VERSION 5.8 ;
BUSBITCHARS "[]" ;
DIVIDERCHAR "/" ;
UNITS
    DATABASE MICRONS 1000 ;
END UNITS

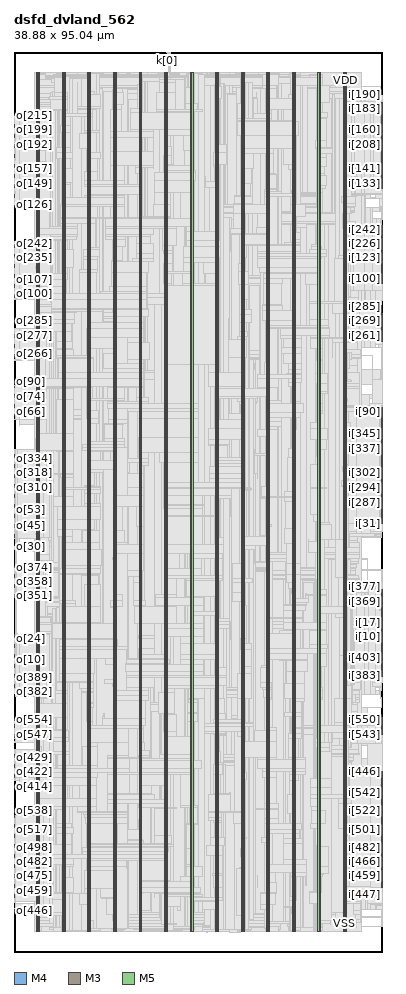
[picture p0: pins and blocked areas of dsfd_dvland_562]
MACRO dsfd_dvland_562
  FOREIGN dsfd_dvland_562 0 0 ;
  CLASS BLOCK ;
  SIZE 38.88 BY 95.04 ;
  PIN ck
    DIRECTION INPUT ;
    USE SIGNAL ;
    PORT
      LAYER M4 ;
        RECT  0 30.576 0.084 30.6 ;
    END
  END ck
  PIN ck_f
    DIRECTION INPUT ;
    USE SIGNAL ;
    PORT
      LAYER M4 ;
        RECT  38.796 32.208 38.88 32.232 ;
    END
  END ck_f
  PIN fault
    DIRECTION OUTPUT ;
    USE SIGNAL ;
    PORT
      LAYER M4 ;
        RECT  0 30.672 0.084 30.696 ;
    END
  END fault
  PIN i[0]
    DIRECTION INPUT ;
    USE SIGNAL ;
    PORT
      LAYER M4 ;
        RECT  38.796 32.304 38.88 32.328 ;
    END
  END i[0]
  PIN i[100]
    DIRECTION INPUT ;
    USE SIGNAL ;
    PORT
      LAYER M4 ;
        RECT  38.796 71.088 38.88 71.112 ;
    END
  END i[100]
  PIN i[101]
    DIRECTION INPUT ;
    USE SIGNAL ;
    PORT
      LAYER M4 ;
        RECT  38.796 71.184 38.88 71.208 ;
    END
  END i[101]
  PIN i[102]
    DIRECTION INPUT ;
    USE SIGNAL ;
    PORT
      LAYER M4 ;
        RECT  38.796 71.28 38.88 71.304 ;
    END
  END i[102]
  PIN i[103]
    DIRECTION INPUT ;
    USE SIGNAL ;
    PORT
      LAYER M4 ;
        RECT  38.796 71.376 38.88 71.4 ;
    END
  END i[103]
  PIN i[104]
    DIRECTION INPUT ;
    USE SIGNAL ;
    PORT
      LAYER M4 ;
        RECT  38.796 71.472 38.88 71.496 ;
    END
  END i[104]
  PIN i[105]
    DIRECTION INPUT ;
    USE SIGNAL ;
    PORT
      LAYER M4 ;
        RECT  38.796 71.568 38.88 71.592 ;
    END
  END i[105]
  PIN i[106]
    DIRECTION INPUT ;
    USE SIGNAL ;
    PORT
      LAYER M4 ;
        RECT  38.796 71.664 38.88 71.688 ;
    END
  END i[106]
  PIN i[107]
    DIRECTION INPUT ;
    USE SIGNAL ;
    PORT
      LAYER M4 ;
        RECT  38.796 71.76 38.88 71.784 ;
    END
  END i[107]
  PIN i[108]
    DIRECTION INPUT ;
    USE SIGNAL ;
    PORT
      LAYER M4 ;
        RECT  38.796 71.856 38.88 71.88 ;
    END
  END i[108]
  PIN i[109]
    DIRECTION INPUT ;
    USE SIGNAL ;
    PORT
      LAYER M4 ;
        RECT  38.796 71.952 38.88 71.976 ;
    END
  END i[109]
  PIN i[10]
    DIRECTION INPUT ;
    USE SIGNAL ;
    PORT
      LAYER M4 ;
        RECT  38.796 33.264 38.88 33.288 ;
    END
  END i[10]
  PIN i[110]
    DIRECTION INPUT ;
    USE SIGNAL ;
    PORT
      LAYER M4 ;
        RECT  38.796 72.048 38.88 72.072 ;
    END
  END i[110]
  PIN i[111]
    DIRECTION INPUT ;
    USE SIGNAL ;
    PORT
      LAYER M4 ;
        RECT  38.796 72.144 38.88 72.168 ;
    END
  END i[111]
  PIN i[112]
    DIRECTION INPUT ;
    USE SIGNAL ;
    PORT
      LAYER M4 ;
        RECT  38.796 72.24 38.88 72.264 ;
    END
  END i[112]
  PIN i[113]
    DIRECTION INPUT ;
    USE SIGNAL ;
    PORT
      LAYER M4 ;
        RECT  38.796 72.336 38.88 72.36 ;
    END
  END i[113]
  PIN i[114]
    DIRECTION INPUT ;
    USE SIGNAL ;
    PORT
      LAYER M4 ;
        RECT  38.796 72.432 38.88 72.456 ;
    END
  END i[114]
  PIN i[115]
    DIRECTION INPUT ;
    USE SIGNAL ;
    PORT
      LAYER M4 ;
        RECT  38.796 72.528 38.88 72.552 ;
    END
  END i[115]
  PIN i[116]
    DIRECTION INPUT ;
    USE SIGNAL ;
    PORT
      LAYER M4 ;
        RECT  38.796 72.624 38.88 72.648 ;
    END
  END i[116]
  PIN i[117]
    DIRECTION INPUT ;
    USE SIGNAL ;
    PORT
      LAYER M4 ;
        RECT  38.796 72.72 38.88 72.744 ;
    END
  END i[117]
  PIN i[118]
    DIRECTION INPUT ;
    USE SIGNAL ;
    PORT
      LAYER M4 ;
        RECT  38.796 72.816 38.88 72.84 ;
    END
  END i[118]
  PIN i[119]
    DIRECTION INPUT ;
    USE SIGNAL ;
    PORT
      LAYER M4 ;
        RECT  38.796 72.912 38.88 72.936 ;
    END
  END i[119]
  PIN i[11]
    DIRECTION INPUT ;
    USE SIGNAL ;
    PORT
      LAYER M4 ;
        RECT  38.796 33.36 38.88 33.384 ;
    END
  END i[11]
  PIN i[120]
    DIRECTION INPUT ;
    USE SIGNAL ;
    PORT
      LAYER M4 ;
        RECT  38.796 73.008 38.88 73.032 ;
    END
  END i[120]
  PIN i[121]
    DIRECTION INPUT ;
    USE SIGNAL ;
    PORT
      LAYER M4 ;
        RECT  38.796 73.104 38.88 73.128 ;
    END
  END i[121]
  PIN i[122]
    DIRECTION INPUT ;
    USE SIGNAL ;
    PORT
      LAYER M4 ;
        RECT  38.796 73.2 38.88 73.224 ;
    END
  END i[122]
  PIN i[123]
    DIRECTION INPUT ;
    USE SIGNAL ;
    PORT
      LAYER M4 ;
        RECT  38.796 73.296 38.88 73.32 ;
    END
  END i[123]
  PIN i[124]
    DIRECTION INPUT ;
    USE SIGNAL ;
    PORT
      LAYER M4 ;
        RECT  38.796 73.392 38.88 73.416 ;
    END
  END i[124]
  PIN i[125]
    DIRECTION INPUT ;
    USE SIGNAL ;
    PORT
      LAYER M4 ;
        RECT  38.796 73.488 38.88 73.512 ;
    END
  END i[125]
  PIN i[126]
    DIRECTION INPUT ;
    USE SIGNAL ;
    PORT
      LAYER M4 ;
        RECT  38.796 73.584 38.88 73.608 ;
    END
  END i[126]
  PIN i[127]
    DIRECTION INPUT ;
    USE SIGNAL ;
    PORT
      LAYER M4 ;
        RECT  38.796 80.592 38.88 80.616 ;
    END
  END i[127]
  PIN i[128]
    DIRECTION INPUT ;
    USE SIGNAL ;
    PORT
      LAYER M4 ;
        RECT  38.796 80.688 38.88 80.712 ;
    END
  END i[128]
  PIN i[129]
    DIRECTION INPUT ;
    USE SIGNAL ;
    PORT
      LAYER M4 ;
        RECT  38.796 80.784 38.88 80.808 ;
    END
  END i[129]
  PIN i[12]
    DIRECTION INPUT ;
    USE SIGNAL ;
    PORT
      LAYER M4 ;
        RECT  38.796 33.456 38.88 33.48 ;
    END
  END i[12]
  PIN i[130]
    DIRECTION INPUT ;
    USE SIGNAL ;
    PORT
      LAYER M4 ;
        RECT  38.796 80.88 38.88 80.904 ;
    END
  END i[130]
  PIN i[131]
    DIRECTION INPUT ;
    USE SIGNAL ;
    PORT
      LAYER M4 ;
        RECT  38.796 80.976 38.88 81 ;
    END
  END i[131]
  PIN i[132]
    DIRECTION INPUT ;
    USE SIGNAL ;
    PORT
      LAYER M4 ;
        RECT  38.796 81.072 38.88 81.096 ;
    END
  END i[132]
  PIN i[133]
    DIRECTION INPUT ;
    USE SIGNAL ;
    PORT
      LAYER M4 ;
        RECT  38.796 81.168 38.88 81.192 ;
    END
  END i[133]
  PIN i[134]
    DIRECTION INPUT ;
    USE SIGNAL ;
    PORT
      LAYER M4 ;
        RECT  38.796 81.264 38.88 81.288 ;
    END
  END i[134]
  PIN i[135]
    DIRECTION INPUT ;
    USE SIGNAL ;
    PORT
      LAYER M4 ;
        RECT  38.796 81.36 38.88 81.384 ;
    END
  END i[135]
  PIN i[136]
    DIRECTION INPUT ;
    USE SIGNAL ;
    PORT
      LAYER M4 ;
        RECT  38.796 81.456 38.88 81.48 ;
    END
  END i[136]
  PIN i[137]
    DIRECTION INPUT ;
    USE SIGNAL ;
    PORT
      LAYER M4 ;
        RECT  38.796 81.552 38.88 81.576 ;
    END
  END i[137]
  PIN i[138]
    DIRECTION INPUT ;
    USE SIGNAL ;
    PORT
      LAYER M4 ;
        RECT  38.796 81.648 38.88 81.672 ;
    END
  END i[138]
  PIN i[139]
    DIRECTION INPUT ;
    USE SIGNAL ;
    PORT
      LAYER M4 ;
        RECT  38.796 81.744 38.88 81.768 ;
    END
  END i[139]
  PIN i[13]
    DIRECTION INPUT ;
    USE SIGNAL ;
    PORT
      LAYER M4 ;
        RECT  38.796 33.552 38.88 33.576 ;
    END
  END i[13]
  PIN i[140]
    DIRECTION INPUT ;
    USE SIGNAL ;
    PORT
      LAYER M4 ;
        RECT  38.796 81.84 38.88 81.864 ;
    END
  END i[140]
  PIN i[141]
    DIRECTION INPUT ;
    USE SIGNAL ;
    PORT
      LAYER M4 ;
        RECT  38.796 81.936 38.88 81.96 ;
    END
  END i[141]
  PIN i[142]
    DIRECTION INPUT ;
    USE SIGNAL ;
    PORT
      LAYER M4 ;
        RECT  38.796 82.032 38.88 82.056 ;
    END
  END i[142]
  PIN i[143]
    DIRECTION INPUT ;
    USE SIGNAL ;
    PORT
      LAYER M4 ;
        RECT  38.796 82.128 38.88 82.152 ;
    END
  END i[143]
  PIN i[144]
    DIRECTION INPUT ;
    USE SIGNAL ;
    PORT
      LAYER M4 ;
        RECT  38.796 82.224 38.88 82.248 ;
    END
  END i[144]
  PIN i[145]
    DIRECTION INPUT ;
    USE SIGNAL ;
    PORT
      LAYER M4 ;
        RECT  38.796 82.32 38.88 82.344 ;
    END
  END i[145]
  PIN i[146]
    DIRECTION INPUT ;
    USE SIGNAL ;
    PORT
      LAYER M4 ;
        RECT  38.796 82.416 38.88 82.44 ;
    END
  END i[146]
  PIN i[147]
    DIRECTION INPUT ;
    USE SIGNAL ;
    PORT
      LAYER M4 ;
        RECT  38.796 82.512 38.88 82.536 ;
    END
  END i[147]
  PIN i[148]
    DIRECTION INPUT ;
    USE SIGNAL ;
    PORT
      LAYER M4 ;
        RECT  38.796 82.608 38.88 82.632 ;
    END
  END i[148]
  PIN i[149]
    DIRECTION INPUT ;
    USE SIGNAL ;
    PORT
      LAYER M4 ;
        RECT  38.796 82.704 38.88 82.728 ;
    END
  END i[149]
  PIN i[14]
    DIRECTION INPUT ;
    USE SIGNAL ;
    PORT
      LAYER M4 ;
        RECT  38.796 33.648 38.88 33.672 ;
    END
  END i[14]
  PIN i[150]
    DIRECTION INPUT ;
    USE SIGNAL ;
    PORT
      LAYER M4 ;
        RECT  38.796 82.8 38.88 82.824 ;
    END
  END i[150]
  PIN i[151]
    DIRECTION INPUT ;
    USE SIGNAL ;
    PORT
      LAYER M4 ;
        RECT  38.796 82.896 38.88 82.92 ;
    END
  END i[151]
  PIN i[152]
    DIRECTION INPUT ;
    USE SIGNAL ;
    PORT
      LAYER M4 ;
        RECT  38.796 82.992 38.88 83.016 ;
    END
  END i[152]
  PIN i[153]
    DIRECTION INPUT ;
    USE SIGNAL ;
    PORT
      LAYER M4 ;
        RECT  38.796 83.088 38.88 83.112 ;
    END
  END i[153]
  PIN i[154]
    DIRECTION INPUT ;
    USE SIGNAL ;
    PORT
      LAYER M4 ;
        RECT  38.796 83.184 38.88 83.208 ;
    END
  END i[154]
  PIN i[155]
    DIRECTION INPUT ;
    USE SIGNAL ;
    PORT
      LAYER M4 ;
        RECT  38.796 83.28 38.88 83.304 ;
    END
  END i[155]
  PIN i[156]
    DIRECTION INPUT ;
    USE SIGNAL ;
    PORT
      LAYER M4 ;
        RECT  38.796 83.376 38.88 83.4 ;
    END
  END i[156]
  PIN i[157]
    DIRECTION INPUT ;
    USE SIGNAL ;
    PORT
      LAYER M4 ;
        RECT  38.796 83.472 38.88 83.496 ;
    END
  END i[157]
  PIN i[158]
    DIRECTION INPUT ;
    USE SIGNAL ;
    PORT
      LAYER M4 ;
        RECT  38.796 83.568 38.88 83.592 ;
    END
  END i[158]
  PIN i[159]
    DIRECTION INPUT ;
    USE SIGNAL ;
    PORT
      LAYER M4 ;
        RECT  38.796 86.736 38.88 86.76 ;
    END
  END i[159]
  PIN i[15]
    DIRECTION INPUT ;
    USE SIGNAL ;
    PORT
      LAYER M4 ;
        RECT  38.796 33.744 38.88 33.768 ;
    END
  END i[15]
  PIN i[160]
    DIRECTION INPUT ;
    USE SIGNAL ;
    PORT
      LAYER M4 ;
        RECT  38.796 86.832 38.88 86.856 ;
    END
  END i[160]
  PIN i[161]
    DIRECTION INPUT ;
    USE SIGNAL ;
    PORT
      LAYER M4 ;
        RECT  38.796 86.928 38.88 86.952 ;
    END
  END i[161]
  PIN i[162]
    DIRECTION INPUT ;
    USE SIGNAL ;
    PORT
      LAYER M4 ;
        RECT  38.796 87.024 38.88 87.048 ;
    END
  END i[162]
  PIN i[163]
    DIRECTION INPUT ;
    USE SIGNAL ;
    PORT
      LAYER M4 ;
        RECT  38.796 87.12 38.88 87.144 ;
    END
  END i[163]
  PIN i[164]
    DIRECTION INPUT ;
    USE SIGNAL ;
    PORT
      LAYER M4 ;
        RECT  38.796 87.216 38.88 87.24 ;
    END
  END i[164]
  PIN i[165]
    DIRECTION INPUT ;
    USE SIGNAL ;
    PORT
      LAYER M4 ;
        RECT  38.796 87.312 38.88 87.336 ;
    END
  END i[165]
  PIN i[166]
    DIRECTION INPUT ;
    USE SIGNAL ;
    PORT
      LAYER M4 ;
        RECT  38.796 87.408 38.88 87.432 ;
    END
  END i[166]
  PIN i[167]
    DIRECTION INPUT ;
    USE SIGNAL ;
    PORT
      LAYER M4 ;
        RECT  38.796 87.504 38.88 87.528 ;
    END
  END i[167]
  PIN i[168]
    DIRECTION INPUT ;
    USE SIGNAL ;
    PORT
      LAYER M4 ;
        RECT  38.796 87.6 38.88 87.624 ;
    END
  END i[168]
  PIN i[169]
    DIRECTION INPUT ;
    USE SIGNAL ;
    PORT
      LAYER M4 ;
        RECT  38.796 87.696 38.88 87.72 ;
    END
  END i[169]
  PIN i[16]
    DIRECTION INPUT ;
    USE SIGNAL ;
    PORT
      LAYER M4 ;
        RECT  38.796 33.84 38.88 33.864 ;
    END
  END i[16]
  PIN i[170]
    DIRECTION INPUT ;
    USE SIGNAL ;
    PORT
      LAYER M4 ;
        RECT  38.796 87.792 38.88 87.816 ;
    END
  END i[170]
  PIN i[171]
    DIRECTION INPUT ;
    USE SIGNAL ;
    PORT
      LAYER M4 ;
        RECT  38.796 87.888 38.88 87.912 ;
    END
  END i[171]
  PIN i[172]
    DIRECTION INPUT ;
    USE SIGNAL ;
    PORT
      LAYER M4 ;
        RECT  38.796 87.984 38.88 88.008 ;
    END
  END i[172]
  PIN i[173]
    DIRECTION INPUT ;
    USE SIGNAL ;
    PORT
      LAYER M4 ;
        RECT  38.796 88.08 38.88 88.104 ;
    END
  END i[173]
  PIN i[174]
    DIRECTION INPUT ;
    USE SIGNAL ;
    PORT
      LAYER M4 ;
        RECT  38.796 88.176 38.88 88.2 ;
    END
  END i[174]
  PIN i[175]
    DIRECTION INPUT ;
    USE SIGNAL ;
    PORT
      LAYER M4 ;
        RECT  38.796 88.272 38.88 88.296 ;
    END
  END i[175]
  PIN i[176]
    DIRECTION INPUT ;
    USE SIGNAL ;
    PORT
      LAYER M4 ;
        RECT  38.796 88.368 38.88 88.392 ;
    END
  END i[176]
  PIN i[177]
    DIRECTION INPUT ;
    USE SIGNAL ;
    PORT
      LAYER M4 ;
        RECT  38.796 88.464 38.88 88.488 ;
    END
  END i[177]
  PIN i[178]
    DIRECTION INPUT ;
    USE SIGNAL ;
    PORT
      LAYER M4 ;
        RECT  38.796 88.56 38.88 88.584 ;
    END
  END i[178]
  PIN i[179]
    DIRECTION INPUT ;
    USE SIGNAL ;
    PORT
      LAYER M4 ;
        RECT  38.796 88.656 38.88 88.68 ;
    END
  END i[179]
  PIN i[17]
    DIRECTION INPUT ;
    USE SIGNAL ;
    PORT
      LAYER M4 ;
        RECT  38.796 33.936 38.88 33.96 ;
    END
  END i[17]
  PIN i[180]
    DIRECTION INPUT ;
    USE SIGNAL ;
    PORT
      LAYER M4 ;
        RECT  38.796 88.752 38.88 88.776 ;
    END
  END i[180]
  PIN i[181]
    DIRECTION INPUT ;
    USE SIGNAL ;
    PORT
      LAYER M4 ;
        RECT  38.796 88.848 38.88 88.872 ;
    END
  END i[181]
  PIN i[182]
    DIRECTION INPUT ;
    USE SIGNAL ;
    PORT
      LAYER M4 ;
        RECT  38.796 88.944 38.88 88.968 ;
    END
  END i[182]
  PIN i[183]
    DIRECTION INPUT ;
    USE SIGNAL ;
    PORT
      LAYER M4 ;
        RECT  38.796 89.04 38.88 89.064 ;
    END
  END i[183]
  PIN i[184]
    DIRECTION INPUT ;
    USE SIGNAL ;
    PORT
      LAYER M4 ;
        RECT  38.796 89.136 38.88 89.16 ;
    END
  END i[184]
  PIN i[185]
    DIRECTION INPUT ;
    USE SIGNAL ;
    PORT
      LAYER M4 ;
        RECT  38.796 89.232 38.88 89.256 ;
    END
  END i[185]
  PIN i[186]
    DIRECTION INPUT ;
    USE SIGNAL ;
    PORT
      LAYER M4 ;
        RECT  38.796 89.328 38.88 89.352 ;
    END
  END i[186]
  PIN i[187]
    DIRECTION INPUT ;
    USE SIGNAL ;
    PORT
      LAYER M4 ;
        RECT  38.796 89.424 38.88 89.448 ;
    END
  END i[187]
  PIN i[188]
    DIRECTION INPUT ;
    USE SIGNAL ;
    PORT
      LAYER M4 ;
        RECT  38.796 89.52 38.88 89.544 ;
    END
  END i[188]
  PIN i[189]
    DIRECTION INPUT ;
    USE SIGNAL ;
    PORT
      LAYER M4 ;
        RECT  38.796 89.616 38.88 89.64 ;
    END
  END i[189]
  PIN i[18]
    DIRECTION INPUT ;
    USE SIGNAL ;
    PORT
      LAYER M4 ;
        RECT  38.796 34.032 38.88 34.056 ;
    END
  END i[18]
  PIN i[190]
    DIRECTION INPUT ;
    USE SIGNAL ;
    PORT
      LAYER M4 ;
        RECT  38.796 89.712 38.88 89.736 ;
    END
  END i[190]
  PIN i[191]
    DIRECTION INPUT ;
    USE SIGNAL ;
    PORT
      LAYER M4 ;
        RECT  38.796 83.664 38.88 83.688 ;
    END
  END i[191]
  PIN i[192]
    DIRECTION INPUT ;
    USE SIGNAL ;
    PORT
      LAYER M4 ;
        RECT  38.796 83.76 38.88 83.784 ;
    END
  END i[192]
  PIN i[193]
    DIRECTION INPUT ;
    USE SIGNAL ;
    PORT
      LAYER M4 ;
        RECT  38.796 83.856 38.88 83.88 ;
    END
  END i[193]
  PIN i[194]
    DIRECTION INPUT ;
    USE SIGNAL ;
    PORT
      LAYER M4 ;
        RECT  38.796 83.952 38.88 83.976 ;
    END
  END i[194]
  PIN i[195]
    DIRECTION INPUT ;
    USE SIGNAL ;
    PORT
      LAYER M4 ;
        RECT  38.796 84.048 38.88 84.072 ;
    END
  END i[195]
  PIN i[196]
    DIRECTION INPUT ;
    USE SIGNAL ;
    PORT
      LAYER M4 ;
        RECT  38.796 84.144 38.88 84.168 ;
    END
  END i[196]
  PIN i[197]
    DIRECTION INPUT ;
    USE SIGNAL ;
    PORT
      LAYER M4 ;
        RECT  38.796 84.24 38.88 84.264 ;
    END
  END i[197]
  PIN i[198]
    DIRECTION INPUT ;
    USE SIGNAL ;
    PORT
      LAYER M4 ;
        RECT  38.796 84.336 38.88 84.36 ;
    END
  END i[198]
  PIN i[199]
    DIRECTION INPUT ;
    USE SIGNAL ;
    PORT
      LAYER M4 ;
        RECT  38.796 84.432 38.88 84.456 ;
    END
  END i[199]
  PIN i[19]
    DIRECTION INPUT ;
    USE SIGNAL ;
    PORT
      LAYER M4 ;
        RECT  38.796 34.128 38.88 34.152 ;
    END
  END i[19]
  PIN i[1]
    DIRECTION INPUT ;
    USE SIGNAL ;
    PORT
      LAYER M4 ;
        RECT  38.796 32.4 38.88 32.424 ;
    END
  END i[1]
  PIN i[200]
    DIRECTION INPUT ;
    USE SIGNAL ;
    PORT
      LAYER M4 ;
        RECT  38.796 84.528 38.88 84.552 ;
    END
  END i[200]
  PIN i[201]
    DIRECTION INPUT ;
    USE SIGNAL ;
    PORT
      LAYER M4 ;
        RECT  38.796 84.624 38.88 84.648 ;
    END
  END i[201]
  PIN i[202]
    DIRECTION INPUT ;
    USE SIGNAL ;
    PORT
      LAYER M4 ;
        RECT  38.796 84.72 38.88 84.744 ;
    END
  END i[202]
  PIN i[203]
    DIRECTION INPUT ;
    USE SIGNAL ;
    PORT
      LAYER M4 ;
        RECT  38.796 84.816 38.88 84.84 ;
    END
  END i[203]
  PIN i[204]
    DIRECTION INPUT ;
    USE SIGNAL ;
    PORT
      LAYER M4 ;
        RECT  38.796 84.912 38.88 84.936 ;
    END
  END i[204]
  PIN i[205]
    DIRECTION INPUT ;
    USE SIGNAL ;
    PORT
      LAYER M4 ;
        RECT  38.796 85.008 38.88 85.032 ;
    END
  END i[205]
  PIN i[206]
    DIRECTION INPUT ;
    USE SIGNAL ;
    PORT
      LAYER M4 ;
        RECT  38.796 85.104 38.88 85.128 ;
    END
  END i[206]
  PIN i[207]
    DIRECTION INPUT ;
    USE SIGNAL ;
    PORT
      LAYER M4 ;
        RECT  38.796 85.2 38.88 85.224 ;
    END
  END i[207]
  PIN i[208]
    DIRECTION INPUT ;
    USE SIGNAL ;
    PORT
      LAYER M4 ;
        RECT  38.796 85.296 38.88 85.32 ;
    END
  END i[208]
  PIN i[209]
    DIRECTION INPUT ;
    USE SIGNAL ;
    PORT
      LAYER M4 ;
        RECT  38.796 85.392 38.88 85.416 ;
    END
  END i[209]
  PIN i[20]
    DIRECTION INPUT ;
    USE SIGNAL ;
    PORT
      LAYER M4 ;
        RECT  38.796 34.224 38.88 34.248 ;
    END
  END i[20]
  PIN i[210]
    DIRECTION INPUT ;
    USE SIGNAL ;
    PORT
      LAYER M4 ;
        RECT  38.796 85.488 38.88 85.512 ;
    END
  END i[210]
  PIN i[211]
    DIRECTION INPUT ;
    USE SIGNAL ;
    PORT
      LAYER M4 ;
        RECT  38.796 85.584 38.88 85.608 ;
    END
  END i[211]
  PIN i[212]
    DIRECTION INPUT ;
    USE SIGNAL ;
    PORT
      LAYER M4 ;
        RECT  38.796 85.68 38.88 85.704 ;
    END
  END i[212]
  PIN i[213]
    DIRECTION INPUT ;
    USE SIGNAL ;
    PORT
      LAYER M4 ;
        RECT  38.796 85.776 38.88 85.8 ;
    END
  END i[213]
  PIN i[214]
    DIRECTION INPUT ;
    USE SIGNAL ;
    PORT
      LAYER M4 ;
        RECT  38.796 85.872 38.88 85.896 ;
    END
  END i[214]
  PIN i[215]
    DIRECTION INPUT ;
    USE SIGNAL ;
    PORT
      LAYER M4 ;
        RECT  38.796 85.968 38.88 85.992 ;
    END
  END i[215]
  PIN i[216]
    DIRECTION INPUT ;
    USE SIGNAL ;
    PORT
      LAYER M4 ;
        RECT  38.796 86.064 38.88 86.088 ;
    END
  END i[216]
  PIN i[217]
    DIRECTION INPUT ;
    USE SIGNAL ;
    PORT
      LAYER M4 ;
        RECT  38.796 86.16 38.88 86.184 ;
    END
  END i[217]
  PIN i[218]
    DIRECTION INPUT ;
    USE SIGNAL ;
    PORT
      LAYER M4 ;
        RECT  38.796 86.256 38.88 86.28 ;
    END
  END i[218]
  PIN i[219]
    DIRECTION INPUT ;
    USE SIGNAL ;
    PORT
      LAYER M4 ;
        RECT  38.796 86.352 38.88 86.376 ;
    END
  END i[219]
  PIN i[21]
    DIRECTION INPUT ;
    USE SIGNAL ;
    PORT
      LAYER M4 ;
        RECT  38.796 34.32 38.88 34.344 ;
    END
  END i[21]
  PIN i[220]
    DIRECTION INPUT ;
    USE SIGNAL ;
    PORT
      LAYER M4 ;
        RECT  38.796 86.448 38.88 86.472 ;
    END
  END i[220]
  PIN i[221]
    DIRECTION INPUT ;
    USE SIGNAL ;
    PORT
      LAYER M4 ;
        RECT  38.796 86.544 38.88 86.568 ;
    END
  END i[221]
  PIN i[222]
    DIRECTION INPUT ;
    USE SIGNAL ;
    PORT
      LAYER M4 ;
        RECT  38.796 86.64 38.88 86.664 ;
    END
  END i[222]
  PIN i[223]
    DIRECTION INPUT ;
    USE SIGNAL ;
    PORT
      LAYER M4 ;
        RECT  38.796 73.68 38.88 73.704 ;
    END
  END i[223]
  PIN i[224]
    DIRECTION INPUT ;
    USE SIGNAL ;
    PORT
      LAYER M4 ;
        RECT  38.796 73.776 38.88 73.8 ;
    END
  END i[224]
  PIN i[225]
    DIRECTION INPUT ;
    USE SIGNAL ;
    PORT
      LAYER M4 ;
        RECT  38.796 73.872 38.88 73.896 ;
    END
  END i[225]
  PIN i[226]
    DIRECTION INPUT ;
    USE SIGNAL ;
    PORT
      LAYER M4 ;
        RECT  38.796 73.968 38.88 73.992 ;
    END
  END i[226]
  PIN i[227]
    DIRECTION INPUT ;
    USE SIGNAL ;
    PORT
      LAYER M4 ;
        RECT  38.796 74.064 38.88 74.088 ;
    END
  END i[227]
  PIN i[228]
    DIRECTION INPUT ;
    USE SIGNAL ;
    PORT
      LAYER M4 ;
        RECT  38.796 74.16 38.88 74.184 ;
    END
  END i[228]
  PIN i[229]
    DIRECTION INPUT ;
    USE SIGNAL ;
    PORT
      LAYER M4 ;
        RECT  38.796 74.256 38.88 74.28 ;
    END
  END i[229]
  PIN i[22]
    DIRECTION INPUT ;
    USE SIGNAL ;
    PORT
      LAYER M4 ;
        RECT  38.796 34.416 38.88 34.44 ;
    END
  END i[22]
  PIN i[230]
    DIRECTION INPUT ;
    USE SIGNAL ;
    PORT
      LAYER M4 ;
        RECT  38.796 74.352 38.88 74.376 ;
    END
  END i[230]
  PIN i[231]
    DIRECTION INPUT ;
    USE SIGNAL ;
    PORT
      LAYER M4 ;
        RECT  38.796 74.448 38.88 74.472 ;
    END
  END i[231]
  PIN i[232]
    DIRECTION INPUT ;
    USE SIGNAL ;
    PORT
      LAYER M4 ;
        RECT  38.796 74.544 38.88 74.568 ;
    END
  END i[232]
  PIN i[233]
    DIRECTION INPUT ;
    USE SIGNAL ;
    PORT
      LAYER M4 ;
        RECT  38.796 74.64 38.88 74.664 ;
    END
  END i[233]
  PIN i[234]
    DIRECTION INPUT ;
    USE SIGNAL ;
    PORT
      LAYER M4 ;
        RECT  38.796 74.736 38.88 74.76 ;
    END
  END i[234]
  PIN i[235]
    DIRECTION INPUT ;
    USE SIGNAL ;
    PORT
      LAYER M4 ;
        RECT  38.796 74.832 38.88 74.856 ;
    END
  END i[235]
  PIN i[236]
    DIRECTION INPUT ;
    USE SIGNAL ;
    PORT
      LAYER M4 ;
        RECT  38.796 74.928 38.88 74.952 ;
    END
  END i[236]
  PIN i[237]
    DIRECTION INPUT ;
    USE SIGNAL ;
    PORT
      LAYER M4 ;
        RECT  38.796 75.024 38.88 75.048 ;
    END
  END i[237]
  PIN i[238]
    DIRECTION INPUT ;
    USE SIGNAL ;
    PORT
      LAYER M4 ;
        RECT  38.796 75.12 38.88 75.144 ;
    END
  END i[238]
  PIN i[239]
    DIRECTION INPUT ;
    USE SIGNAL ;
    PORT
      LAYER M4 ;
        RECT  38.796 75.216 38.88 75.24 ;
    END
  END i[239]
  PIN i[23]
    DIRECTION INPUT ;
    USE SIGNAL ;
    PORT
      LAYER M4 ;
        RECT  38.796 34.512 38.88 34.536 ;
    END
  END i[23]
  PIN i[240]
    DIRECTION INPUT ;
    USE SIGNAL ;
    PORT
      LAYER M4 ;
        RECT  38.796 75.312 38.88 75.336 ;
    END
  END i[240]
  PIN i[241]
    DIRECTION INPUT ;
    USE SIGNAL ;
    PORT
      LAYER M4 ;
        RECT  38.796 75.408 38.88 75.432 ;
    END
  END i[241]
  PIN i[242]
    DIRECTION INPUT ;
    USE SIGNAL ;
    PORT
      LAYER M4 ;
        RECT  38.796 75.504 38.88 75.528 ;
    END
  END i[242]
  PIN i[243]
    DIRECTION INPUT ;
    USE SIGNAL ;
    PORT
      LAYER M4 ;
        RECT  38.796 75.6 38.88 75.624 ;
    END
  END i[243]
  PIN i[244]
    DIRECTION INPUT ;
    USE SIGNAL ;
    PORT
      LAYER M4 ;
        RECT  38.796 75.696 38.88 75.72 ;
    END
  END i[244]
  PIN i[245]
    DIRECTION INPUT ;
    USE SIGNAL ;
    PORT
      LAYER M4 ;
        RECT  38.796 75.792 38.88 75.816 ;
    END
  END i[245]
  PIN i[246]
    DIRECTION INPUT ;
    USE SIGNAL ;
    PORT
      LAYER M4 ;
        RECT  38.796 75.888 38.88 75.912 ;
    END
  END i[246]
  PIN i[247]
    DIRECTION INPUT ;
    USE SIGNAL ;
    PORT
      LAYER M4 ;
        RECT  38.796 75.984 38.88 76.008 ;
    END
  END i[247]
  PIN i[248]
    DIRECTION INPUT ;
    USE SIGNAL ;
    PORT
      LAYER M4 ;
        RECT  38.796 76.08 38.88 76.104 ;
    END
  END i[248]
  PIN i[249]
    DIRECTION INPUT ;
    USE SIGNAL ;
    PORT
      LAYER M4 ;
        RECT  38.796 76.176 38.88 76.2 ;
    END
  END i[249]
  PIN i[24]
    DIRECTION INPUT ;
    USE SIGNAL ;
    PORT
      LAYER M4 ;
        RECT  38.796 34.608 38.88 34.632 ;
    END
  END i[24]
  PIN i[250]
    DIRECTION INPUT ;
    USE SIGNAL ;
    PORT
      LAYER M4 ;
        RECT  38.796 76.272 38.88 76.296 ;
    END
  END i[250]
  PIN i[251]
    DIRECTION INPUT ;
    USE SIGNAL ;
    PORT
      LAYER M4 ;
        RECT  38.796 76.368 38.88 76.392 ;
    END
  END i[251]
  PIN i[252]
    DIRECTION INPUT ;
    USE SIGNAL ;
    PORT
      LAYER M4 ;
        RECT  38.796 76.464 38.88 76.488 ;
    END
  END i[252]
  PIN i[253]
    DIRECTION INPUT ;
    USE SIGNAL ;
    PORT
      LAYER M4 ;
        RECT  38.796 76.56 38.88 76.584 ;
    END
  END i[253]
  PIN i[254]
    DIRECTION INPUT ;
    USE SIGNAL ;
    PORT
      LAYER M4 ;
        RECT  38.796 76.656 38.88 76.68 ;
    END
  END i[254]
  PIN i[255]
    DIRECTION INPUT ;
    USE SIGNAL ;
    PORT
      LAYER M4 ;
        RECT  38.796 64.464 38.88 64.488 ;
    END
  END i[255]
  PIN i[256]
    DIRECTION INPUT ;
    USE SIGNAL ;
    PORT
      LAYER M4 ;
        RECT  38.796 64.56 38.88 64.584 ;
    END
  END i[256]
  PIN i[257]
    DIRECTION INPUT ;
    USE SIGNAL ;
    PORT
      LAYER M4 ;
        RECT  38.796 64.656 38.88 64.68 ;
    END
  END i[257]
  PIN i[258]
    DIRECTION INPUT ;
    USE SIGNAL ;
    PORT
      LAYER M4 ;
        RECT  38.796 64.752 38.88 64.776 ;
    END
  END i[258]
  PIN i[259]
    DIRECTION INPUT ;
    USE SIGNAL ;
    PORT
      LAYER M4 ;
        RECT  38.796 64.848 38.88 64.872 ;
    END
  END i[259]
  PIN i[25]
    DIRECTION INPUT ;
    USE SIGNAL ;
    PORT
      LAYER M4 ;
        RECT  38.796 34.704 38.88 34.728 ;
    END
  END i[25]
  PIN i[260]
    DIRECTION INPUT ;
    USE SIGNAL ;
    PORT
      LAYER M4 ;
        RECT  38.796 64.944 38.88 64.968 ;
    END
  END i[260]
  PIN i[261]
    DIRECTION INPUT ;
    USE SIGNAL ;
    PORT
      LAYER M4 ;
        RECT  38.796 65.04 38.88 65.064 ;
    END
  END i[261]
  PIN i[262]
    DIRECTION INPUT ;
    USE SIGNAL ;
    PORT
      LAYER M4 ;
        RECT  38.796 65.136 38.88 65.16 ;
    END
  END i[262]
  PIN i[263]
    DIRECTION INPUT ;
    USE SIGNAL ;
    PORT
      LAYER M4 ;
        RECT  38.796 65.232 38.88 65.256 ;
    END
  END i[263]
  PIN i[264]
    DIRECTION INPUT ;
    USE SIGNAL ;
    PORT
      LAYER M4 ;
        RECT  38.796 65.328 38.88 65.352 ;
    END
  END i[264]
  PIN i[265]
    DIRECTION INPUT ;
    USE SIGNAL ;
    PORT
      LAYER M4 ;
        RECT  38.796 65.424 38.88 65.448 ;
    END
  END i[265]
  PIN i[266]
    DIRECTION INPUT ;
    USE SIGNAL ;
    PORT
      LAYER M4 ;
        RECT  38.796 65.52 38.88 65.544 ;
    END
  END i[266]
  PIN i[267]
    DIRECTION INPUT ;
    USE SIGNAL ;
    PORT
      LAYER M4 ;
        RECT  38.796 65.616 38.88 65.64 ;
    END
  END i[267]
  PIN i[268]
    DIRECTION INPUT ;
    USE SIGNAL ;
    PORT
      LAYER M4 ;
        RECT  38.796 65.712 38.88 65.736 ;
    END
  END i[268]
  PIN i[269]
    DIRECTION INPUT ;
    USE SIGNAL ;
    PORT
      LAYER M4 ;
        RECT  38.796 65.808 38.88 65.832 ;
    END
  END i[269]
  PIN i[26]
    DIRECTION INPUT ;
    USE SIGNAL ;
    PORT
      LAYER M4 ;
        RECT  38.796 34.8 38.88 34.824 ;
    END
  END i[26]
  PIN i[270]
    DIRECTION INPUT ;
    USE SIGNAL ;
    PORT
      LAYER M4 ;
        RECT  38.796 65.904 38.88 65.928 ;
    END
  END i[270]
  PIN i[271]
    DIRECTION INPUT ;
    USE SIGNAL ;
    PORT
      LAYER M4 ;
        RECT  38.796 66 38.88 66.024 ;
    END
  END i[271]
  PIN i[272]
    DIRECTION INPUT ;
    USE SIGNAL ;
    PORT
      LAYER M4 ;
        RECT  38.796 66.096 38.88 66.12 ;
    END
  END i[272]
  PIN i[273]
    DIRECTION INPUT ;
    USE SIGNAL ;
    PORT
      LAYER M4 ;
        RECT  38.796 66.192 38.88 66.216 ;
    END
  END i[273]
  PIN i[274]
    DIRECTION INPUT ;
    USE SIGNAL ;
    PORT
      LAYER M4 ;
        RECT  38.796 66.288 38.88 66.312 ;
    END
  END i[274]
  PIN i[275]
    DIRECTION INPUT ;
    USE SIGNAL ;
    PORT
      LAYER M4 ;
        RECT  38.796 66.384 38.88 66.408 ;
    END
  END i[275]
  PIN i[276]
    DIRECTION INPUT ;
    USE SIGNAL ;
    PORT
      LAYER M4 ;
        RECT  38.796 66.48 38.88 66.504 ;
    END
  END i[276]
  PIN i[277]
    DIRECTION INPUT ;
    USE SIGNAL ;
    PORT
      LAYER M4 ;
        RECT  38.796 66.576 38.88 66.6 ;
    END
  END i[277]
  PIN i[278]
    DIRECTION INPUT ;
    USE SIGNAL ;
    PORT
      LAYER M4 ;
        RECT  38.796 66.672 38.88 66.696 ;
    END
  END i[278]
  PIN i[279]
    DIRECTION INPUT ;
    USE SIGNAL ;
    PORT
      LAYER M4 ;
        RECT  38.796 66.768 38.88 66.792 ;
    END
  END i[279]
  PIN i[27]
    DIRECTION INPUT ;
    USE SIGNAL ;
    PORT
      LAYER M4 ;
        RECT  38.796 34.896 38.88 34.92 ;
    END
  END i[27]
  PIN i[280]
    DIRECTION INPUT ;
    USE SIGNAL ;
    PORT
      LAYER M4 ;
        RECT  38.796 66.864 38.88 66.888 ;
    END
  END i[280]
  PIN i[281]
    DIRECTION INPUT ;
    USE SIGNAL ;
    PORT
      LAYER M4 ;
        RECT  38.796 66.96 38.88 66.984 ;
    END
  END i[281]
  PIN i[282]
    DIRECTION INPUT ;
    USE SIGNAL ;
    PORT
      LAYER M4 ;
        RECT  38.796 67.056 38.88 67.08 ;
    END
  END i[282]
  PIN i[283]
    DIRECTION INPUT ;
    USE SIGNAL ;
    PORT
      LAYER M4 ;
        RECT  38.796 67.152 38.88 67.176 ;
    END
  END i[283]
  PIN i[284]
    DIRECTION INPUT ;
    USE SIGNAL ;
    PORT
      LAYER M4 ;
        RECT  38.796 67.248 38.88 67.272 ;
    END
  END i[284]
  PIN i[285]
    DIRECTION INPUT ;
    USE SIGNAL ;
    PORT
      LAYER M4 ;
        RECT  38.796 67.344 38.88 67.368 ;
    END
  END i[285]
  PIN i[286]
    DIRECTION INPUT ;
    USE SIGNAL ;
    PORT
      LAYER M4 ;
        RECT  38.796 67.44 38.88 67.464 ;
    END
  END i[286]
  PIN i[287]
    DIRECTION INPUT ;
    USE SIGNAL ;
    PORT
      LAYER M4 ;
        RECT  38.796 48.336 38.88 48.36 ;
    END
  END i[287]
  PIN i[288]
    DIRECTION INPUT ;
    USE SIGNAL ;
    PORT
      LAYER M4 ;
        RECT  38.796 48.432 38.88 48.456 ;
    END
  END i[288]
  PIN i[289]
    DIRECTION INPUT ;
    USE SIGNAL ;
    PORT
      LAYER M4 ;
        RECT  38.796 48.528 38.88 48.552 ;
    END
  END i[289]
  PIN i[28]
    DIRECTION INPUT ;
    USE SIGNAL ;
    PORT
      LAYER M4 ;
        RECT  38.796 34.992 38.88 35.016 ;
    END
  END i[28]
  PIN i[290]
    DIRECTION INPUT ;
    USE SIGNAL ;
    PORT
      LAYER M4 ;
        RECT  38.796 48.624 38.88 48.648 ;
    END
  END i[290]
  PIN i[291]
    DIRECTION INPUT ;
    USE SIGNAL ;
    PORT
      LAYER M4 ;
        RECT  38.796 48.72 38.88 48.744 ;
    END
  END i[291]
  PIN i[292]
    DIRECTION INPUT ;
    USE SIGNAL ;
    PORT
      LAYER M4 ;
        RECT  38.796 48.816 38.88 48.84 ;
    END
  END i[292]
  PIN i[293]
    DIRECTION INPUT ;
    USE SIGNAL ;
    PORT
      LAYER M4 ;
        RECT  38.796 48.912 38.88 48.936 ;
    END
  END i[293]
  PIN i[294]
    DIRECTION INPUT ;
    USE SIGNAL ;
    PORT
      LAYER M4 ;
        RECT  38.796 49.008 38.88 49.032 ;
    END
  END i[294]
  PIN i[295]
    DIRECTION INPUT ;
    USE SIGNAL ;
    PORT
      LAYER M4 ;
        RECT  38.796 49.104 38.88 49.128 ;
    END
  END i[295]
  PIN i[296]
    DIRECTION INPUT ;
    USE SIGNAL ;
    PORT
      LAYER M4 ;
        RECT  38.796 49.2 38.88 49.224 ;
    END
  END i[296]
  PIN i[297]
    DIRECTION INPUT ;
    USE SIGNAL ;
    PORT
      LAYER M4 ;
        RECT  38.796 49.296 38.88 49.32 ;
    END
  END i[297]
  PIN i[298]
    DIRECTION INPUT ;
    USE SIGNAL ;
    PORT
      LAYER M4 ;
        RECT  38.796 49.392 38.88 49.416 ;
    END
  END i[298]
  PIN i[299]
    DIRECTION INPUT ;
    USE SIGNAL ;
    PORT
      LAYER M4 ;
        RECT  38.796 49.488 38.88 49.512 ;
    END
  END i[299]
  PIN i[29]
    DIRECTION INPUT ;
    USE SIGNAL ;
    PORT
      LAYER M4 ;
        RECT  38.796 35.088 38.88 35.112 ;
    END
  END i[29]
  PIN i[2]
    DIRECTION INPUT ;
    USE SIGNAL ;
    PORT
      LAYER M4 ;
        RECT  38.796 32.496 38.88 32.52 ;
    END
  END i[2]
  PIN i[300]
    DIRECTION INPUT ;
    USE SIGNAL ;
    PORT
      LAYER M4 ;
        RECT  38.796 49.584 38.88 49.608 ;
    END
  END i[300]
  PIN i[301]
    DIRECTION INPUT ;
    USE SIGNAL ;
    PORT
      LAYER M4 ;
        RECT  38.796 49.68 38.88 49.704 ;
    END
  END i[301]
  PIN i[302]
    DIRECTION INPUT ;
    USE SIGNAL ;
    PORT
      LAYER M4 ;
        RECT  38.796 49.776 38.88 49.8 ;
    END
  END i[302]
  PIN i[303]
    DIRECTION INPUT ;
    USE SIGNAL ;
    PORT
      LAYER M4 ;
        RECT  38.796 49.872 38.88 49.896 ;
    END
  END i[303]
  PIN i[304]
    DIRECTION INPUT ;
    USE SIGNAL ;
    PORT
      LAYER M4 ;
        RECT  38.796 49.968 38.88 49.992 ;
    END
  END i[304]
  PIN i[305]
    DIRECTION INPUT ;
    USE SIGNAL ;
    PORT
      LAYER M4 ;
        RECT  38.796 50.064 38.88 50.088 ;
    END
  END i[305]
  PIN i[306]
    DIRECTION INPUT ;
    USE SIGNAL ;
    PORT
      LAYER M4 ;
        RECT  38.796 50.16 38.88 50.184 ;
    END
  END i[306]
  PIN i[307]
    DIRECTION INPUT ;
    USE SIGNAL ;
    PORT
      LAYER M4 ;
        RECT  38.796 50.256 38.88 50.28 ;
    END
  END i[307]
  PIN i[308]
    DIRECTION INPUT ;
    USE SIGNAL ;
    PORT
      LAYER M4 ;
        RECT  38.796 50.352 38.88 50.376 ;
    END
  END i[308]
  PIN i[309]
    DIRECTION INPUT ;
    USE SIGNAL ;
    PORT
      LAYER M4 ;
        RECT  38.796 50.448 38.88 50.472 ;
    END
  END i[309]
  PIN i[30]
    DIRECTION INPUT ;
    USE SIGNAL ;
    PORT
      LAYER M4 ;
        RECT  38.796 35.184 38.88 35.208 ;
    END
  END i[30]
  PIN i[310]
    DIRECTION INPUT ;
    USE SIGNAL ;
    PORT
      LAYER M4 ;
        RECT  38.796 50.544 38.88 50.568 ;
    END
  END i[310]
  PIN i[311]
    DIRECTION INPUT ;
    USE SIGNAL ;
    PORT
      LAYER M4 ;
        RECT  38.796 50.64 38.88 50.664 ;
    END
  END i[311]
  PIN i[312]
    DIRECTION INPUT ;
    USE SIGNAL ;
    PORT
      LAYER M4 ;
        RECT  38.796 50.736 38.88 50.76 ;
    END
  END i[312]
  PIN i[313]
    DIRECTION INPUT ;
    USE SIGNAL ;
    PORT
      LAYER M4 ;
        RECT  38.796 50.832 38.88 50.856 ;
    END
  END i[313]
  PIN i[314]
    DIRECTION INPUT ;
    USE SIGNAL ;
    PORT
      LAYER M4 ;
        RECT  38.796 50.928 38.88 50.952 ;
    END
  END i[314]
  PIN i[315]
    DIRECTION INPUT ;
    USE SIGNAL ;
    PORT
      LAYER M4 ;
        RECT  38.796 51.024 38.88 51.048 ;
    END
  END i[315]
  PIN i[316]
    DIRECTION INPUT ;
    USE SIGNAL ;
    PORT
      LAYER M4 ;
        RECT  38.796 51.12 38.88 51.144 ;
    END
  END i[316]
  PIN i[317]
    DIRECTION INPUT ;
    USE SIGNAL ;
    PORT
      LAYER M4 ;
        RECT  38.796 51.216 38.88 51.24 ;
    END
  END i[317]
  PIN i[318]
    DIRECTION INPUT ;
    USE SIGNAL ;
    PORT
      LAYER M4 ;
        RECT  38.796 51.312 38.88 51.336 ;
    END
  END i[318]
  PIN i[319]
    DIRECTION INPUT ;
    USE SIGNAL ;
    PORT
      LAYER M4 ;
        RECT  38.796 51.408 38.88 51.432 ;
    END
  END i[319]
  PIN i[31]
    DIRECTION INPUT ;
    USE SIGNAL ;
    PORT
      LAYER M4 ;
        RECT  38.796 45.264 38.88 45.288 ;
    END
  END i[31]
  PIN i[320]
    DIRECTION INPUT ;
    USE SIGNAL ;
    PORT
      LAYER M4 ;
        RECT  38.796 51.504 38.88 51.528 ;
    END
  END i[320]
  PIN i[321]
    DIRECTION INPUT ;
    USE SIGNAL ;
    PORT
      LAYER M4 ;
        RECT  38.796 51.6 38.88 51.624 ;
    END
  END i[321]
  PIN i[322]
    DIRECTION INPUT ;
    USE SIGNAL ;
    PORT
      LAYER M4 ;
        RECT  38.796 51.696 38.88 51.72 ;
    END
  END i[322]
  PIN i[323]
    DIRECTION INPUT ;
    USE SIGNAL ;
    PORT
      LAYER M4 ;
        RECT  38.796 51.792 38.88 51.816 ;
    END
  END i[323]
  PIN i[324]
    DIRECTION INPUT ;
    USE SIGNAL ;
    PORT
      LAYER M4 ;
        RECT  38.796 51.888 38.88 51.912 ;
    END
  END i[324]
  PIN i[325]
    DIRECTION INPUT ;
    USE SIGNAL ;
    PORT
      LAYER M4 ;
        RECT  38.796 51.984 38.88 52.008 ;
    END
  END i[325]
  PIN i[326]
    DIRECTION INPUT ;
    USE SIGNAL ;
    PORT
      LAYER M4 ;
        RECT  38.796 52.08 38.88 52.104 ;
    END
  END i[326]
  PIN i[327]
    DIRECTION INPUT ;
    USE SIGNAL ;
    PORT
      LAYER M4 ;
        RECT  38.796 52.176 38.88 52.2 ;
    END
  END i[327]
  PIN i[328]
    DIRECTION INPUT ;
    USE SIGNAL ;
    PORT
      LAYER M4 ;
        RECT  38.796 52.272 38.88 52.296 ;
    END
  END i[328]
  PIN i[329]
    DIRECTION INPUT ;
    USE SIGNAL ;
    PORT
      LAYER M4 ;
        RECT  38.796 52.368 38.88 52.392 ;
    END
  END i[329]
  PIN i[32]
    DIRECTION INPUT ;
    USE SIGNAL ;
    PORT
      LAYER M4 ;
        RECT  38.796 45.36 38.88 45.384 ;
    END
  END i[32]
  PIN i[330]
    DIRECTION INPUT ;
    USE SIGNAL ;
    PORT
      LAYER M4 ;
        RECT  38.796 52.464 38.88 52.488 ;
    END
  END i[330]
  PIN i[331]
    DIRECTION INPUT ;
    USE SIGNAL ;
    PORT
      LAYER M4 ;
        RECT  38.796 52.56 38.88 52.584 ;
    END
  END i[331]
  PIN i[332]
    DIRECTION INPUT ;
    USE SIGNAL ;
    PORT
      LAYER M4 ;
        RECT  38.796 52.656 38.88 52.68 ;
    END
  END i[332]
  PIN i[333]
    DIRECTION INPUT ;
    USE SIGNAL ;
    PORT
      LAYER M4 ;
        RECT  38.796 52.752 38.88 52.776 ;
    END
  END i[333]
  PIN i[334]
    DIRECTION INPUT ;
    USE SIGNAL ;
    PORT
      LAYER M4 ;
        RECT  38.796 52.848 38.88 52.872 ;
    END
  END i[334]
  PIN i[335]
    DIRECTION INPUT ;
    USE SIGNAL ;
    PORT
      LAYER M4 ;
        RECT  38.796 52.944 38.88 52.968 ;
    END
  END i[335]
  PIN i[336]
    DIRECTION INPUT ;
    USE SIGNAL ;
    PORT
      LAYER M4 ;
        RECT  38.796 53.04 38.88 53.064 ;
    END
  END i[336]
  PIN i[337]
    DIRECTION INPUT ;
    USE SIGNAL ;
    PORT
      LAYER M4 ;
        RECT  38.796 53.136 38.88 53.16 ;
    END
  END i[337]
  PIN i[338]
    DIRECTION INPUT ;
    USE SIGNAL ;
    PORT
      LAYER M4 ;
        RECT  38.796 53.232 38.88 53.256 ;
    END
  END i[338]
  PIN i[339]
    DIRECTION INPUT ;
    USE SIGNAL ;
    PORT
      LAYER M4 ;
        RECT  38.796 53.328 38.88 53.352 ;
    END
  END i[339]
  PIN i[33]
    DIRECTION INPUT ;
    USE SIGNAL ;
    PORT
      LAYER M4 ;
        RECT  38.796 45.456 38.88 45.48 ;
    END
  END i[33]
  PIN i[340]
    DIRECTION INPUT ;
    USE SIGNAL ;
    PORT
      LAYER M4 ;
        RECT  38.796 53.424 38.88 53.448 ;
    END
  END i[340]
  PIN i[341]
    DIRECTION INPUT ;
    USE SIGNAL ;
    PORT
      LAYER M4 ;
        RECT  38.796 53.52 38.88 53.544 ;
    END
  END i[341]
  PIN i[342]
    DIRECTION INPUT ;
    USE SIGNAL ;
    PORT
      LAYER M4 ;
        RECT  38.796 53.616 38.88 53.64 ;
    END
  END i[342]
  PIN i[343]
    DIRECTION INPUT ;
    USE SIGNAL ;
    PORT
      LAYER M4 ;
        RECT  38.796 53.712 38.88 53.736 ;
    END
  END i[343]
  PIN i[344]
    DIRECTION INPUT ;
    USE SIGNAL ;
    PORT
      LAYER M4 ;
        RECT  38.796 53.808 38.88 53.832 ;
    END
  END i[344]
  PIN i[345]
    DIRECTION INPUT ;
    USE SIGNAL ;
    PORT
      LAYER M4 ;
        RECT  38.796 53.904 38.88 53.928 ;
    END
  END i[345]
  PIN i[346]
    DIRECTION INPUT ;
    USE SIGNAL ;
    PORT
      LAYER M4 ;
        RECT  38.796 54 38.88 54.024 ;
    END
  END i[346]
  PIN i[347]
    DIRECTION INPUT ;
    USE SIGNAL ;
    PORT
      LAYER M4 ;
        RECT  38.796 54.096 38.88 54.12 ;
    END
  END i[347]
  PIN i[348]
    DIRECTION INPUT ;
    USE SIGNAL ;
    PORT
      LAYER M4 ;
        RECT  38.796 54.192 38.88 54.216 ;
    END
  END i[348]
  PIN i[349]
    DIRECTION INPUT ;
    USE SIGNAL ;
    PORT
      LAYER M4 ;
        RECT  38.796 54.288 38.88 54.312 ;
    END
  END i[349]
  PIN i[34]
    DIRECTION INPUT ;
    USE SIGNAL ;
    PORT
      LAYER M4 ;
        RECT  38.796 45.552 38.88 45.576 ;
    END
  END i[34]
  PIN i[350]
    DIRECTION INPUT ;
    USE SIGNAL ;
    PORT
      LAYER M4 ;
        RECT  38.796 54.384 38.88 54.408 ;
    END
  END i[350]
  PIN i[351]
    DIRECTION INPUT ;
    USE SIGNAL ;
    PORT
      LAYER M4 ;
        RECT  38.796 35.28 38.88 35.304 ;
    END
  END i[351]
  PIN i[352]
    DIRECTION INPUT ;
    USE SIGNAL ;
    PORT
      LAYER M4 ;
        RECT  38.796 35.376 38.88 35.4 ;
    END
  END i[352]
  PIN i[353]
    DIRECTION INPUT ;
    USE SIGNAL ;
    PORT
      LAYER M4 ;
        RECT  38.796 35.472 38.88 35.496 ;
    END
  END i[353]
  PIN i[354]
    DIRECTION INPUT ;
    USE SIGNAL ;
    PORT
      LAYER M4 ;
        RECT  38.796 35.568 38.88 35.592 ;
    END
  END i[354]
  PIN i[355]
    DIRECTION INPUT ;
    USE SIGNAL ;
    PORT
      LAYER M4 ;
        RECT  38.796 35.664 38.88 35.688 ;
    END
  END i[355]
  PIN i[356]
    DIRECTION INPUT ;
    USE SIGNAL ;
    PORT
      LAYER M4 ;
        RECT  38.796 35.76 38.88 35.784 ;
    END
  END i[356]
  PIN i[357]
    DIRECTION INPUT ;
    USE SIGNAL ;
    PORT
      LAYER M4 ;
        RECT  38.796 35.856 38.88 35.88 ;
    END
  END i[357]
  PIN i[358]
    DIRECTION INPUT ;
    USE SIGNAL ;
    PORT
      LAYER M4 ;
        RECT  38.796 35.952 38.88 35.976 ;
    END
  END i[358]
  PIN i[359]
    DIRECTION INPUT ;
    USE SIGNAL ;
    PORT
      LAYER M4 ;
        RECT  38.796 36.048 38.88 36.072 ;
    END
  END i[359]
  PIN i[35]
    DIRECTION INPUT ;
    USE SIGNAL ;
    PORT
      LAYER M4 ;
        RECT  38.796 45.648 38.88 45.672 ;
    END
  END i[35]
  PIN i[360]
    DIRECTION INPUT ;
    USE SIGNAL ;
    PORT
      LAYER M4 ;
        RECT  38.796 36.144 38.88 36.168 ;
    END
  END i[360]
  PIN i[361]
    DIRECTION INPUT ;
    USE SIGNAL ;
    PORT
      LAYER M4 ;
        RECT  38.796 36.24 38.88 36.264 ;
    END
  END i[361]
  PIN i[362]
    DIRECTION INPUT ;
    USE SIGNAL ;
    PORT
      LAYER M4 ;
        RECT  38.796 36.336 38.88 36.36 ;
    END
  END i[362]
  PIN i[363]
    DIRECTION INPUT ;
    USE SIGNAL ;
    PORT
      LAYER M4 ;
        RECT  38.796 36.432 38.88 36.456 ;
    END
  END i[363]
  PIN i[364]
    DIRECTION INPUT ;
    USE SIGNAL ;
    PORT
      LAYER M4 ;
        RECT  38.796 36.528 38.88 36.552 ;
    END
  END i[364]
  PIN i[365]
    DIRECTION INPUT ;
    USE SIGNAL ;
    PORT
      LAYER M4 ;
        RECT  38.796 36.624 38.88 36.648 ;
    END
  END i[365]
  PIN i[366]
    DIRECTION INPUT ;
    USE SIGNAL ;
    PORT
      LAYER M4 ;
        RECT  38.796 36.72 38.88 36.744 ;
    END
  END i[366]
  PIN i[367]
    DIRECTION INPUT ;
    USE SIGNAL ;
    PORT
      LAYER M4 ;
        RECT  38.796 36.816 38.88 36.84 ;
    END
  END i[367]
  PIN i[368]
    DIRECTION INPUT ;
    USE SIGNAL ;
    PORT
      LAYER M4 ;
        RECT  38.796 36.912 38.88 36.936 ;
    END
  END i[368]
  PIN i[369]
    DIRECTION INPUT ;
    USE SIGNAL ;
    PORT
      LAYER M4 ;
        RECT  38.796 37.008 38.88 37.032 ;
    END
  END i[369]
  PIN i[36]
    DIRECTION INPUT ;
    USE SIGNAL ;
    PORT
      LAYER M4 ;
        RECT  38.796 45.744 38.88 45.768 ;
    END
  END i[36]
  PIN i[370]
    DIRECTION INPUT ;
    USE SIGNAL ;
    PORT
      LAYER M4 ;
        RECT  38.796 37.104 38.88 37.128 ;
    END
  END i[370]
  PIN i[371]
    DIRECTION INPUT ;
    USE SIGNAL ;
    PORT
      LAYER M4 ;
        RECT  38.796 37.2 38.88 37.224 ;
    END
  END i[371]
  PIN i[372]
    DIRECTION INPUT ;
    USE SIGNAL ;
    PORT
      LAYER M4 ;
        RECT  38.796 37.296 38.88 37.32 ;
    END
  END i[372]
  PIN i[373]
    DIRECTION INPUT ;
    USE SIGNAL ;
    PORT
      LAYER M4 ;
        RECT  38.796 37.392 38.88 37.416 ;
    END
  END i[373]
  PIN i[374]
    DIRECTION INPUT ;
    USE SIGNAL ;
    PORT
      LAYER M4 ;
        RECT  38.796 37.488 38.88 37.512 ;
    END
  END i[374]
  PIN i[375]
    DIRECTION INPUT ;
    USE SIGNAL ;
    PORT
      LAYER M4 ;
        RECT  38.796 37.584 38.88 37.608 ;
    END
  END i[375]
  PIN i[376]
    DIRECTION INPUT ;
    USE SIGNAL ;
    PORT
      LAYER M4 ;
        RECT  38.796 37.68 38.88 37.704 ;
    END
  END i[376]
  PIN i[377]
    DIRECTION INPUT ;
    USE SIGNAL ;
    PORT
      LAYER M4 ;
        RECT  38.796 37.776 38.88 37.8 ;
    END
  END i[377]
  PIN i[378]
    DIRECTION INPUT ;
    USE SIGNAL ;
    PORT
      LAYER M4 ;
        RECT  38.796 37.872 38.88 37.896 ;
    END
  END i[378]
  PIN i[379]
    DIRECTION INPUT ;
    USE SIGNAL ;
    PORT
      LAYER M4 ;
        RECT  38.796 37.968 38.88 37.992 ;
    END
  END i[379]
  PIN i[37]
    DIRECTION INPUT ;
    USE SIGNAL ;
    PORT
      LAYER M4 ;
        RECT  38.796 45.84 38.88 45.864 ;
    END
  END i[37]
  PIN i[380]
    DIRECTION INPUT ;
    USE SIGNAL ;
    PORT
      LAYER M4 ;
        RECT  38.796 38.064 38.88 38.088 ;
    END
  END i[380]
  PIN i[381]
    DIRECTION INPUT ;
    USE SIGNAL ;
    PORT
      LAYER M4 ;
        RECT  38.796 38.16 38.88 38.184 ;
    END
  END i[381]
  PIN i[382]
    DIRECTION INPUT ;
    USE SIGNAL ;
    PORT
      LAYER M4 ;
        RECT  38.796 38.256 38.88 38.28 ;
    END
  END i[382]
  PIN i[383]
    DIRECTION INPUT ;
    USE SIGNAL ;
    PORT
      LAYER M4 ;
        RECT  38.796 29.136 38.88 29.16 ;
    END
  END i[383]
  PIN i[384]
    DIRECTION INPUT ;
    USE SIGNAL ;
    PORT
      LAYER M4 ;
        RECT  38.796 29.232 38.88 29.256 ;
    END
  END i[384]
  PIN i[385]
    DIRECTION INPUT ;
    USE SIGNAL ;
    PORT
      LAYER M4 ;
        RECT  38.796 29.328 38.88 29.352 ;
    END
  END i[385]
  PIN i[386]
    DIRECTION INPUT ;
    USE SIGNAL ;
    PORT
      LAYER M4 ;
        RECT  38.796 29.424 38.88 29.448 ;
    END
  END i[386]
  PIN i[387]
    DIRECTION INPUT ;
    USE SIGNAL ;
    PORT
      LAYER M4 ;
        RECT  38.796 29.52 38.88 29.544 ;
    END
  END i[387]
  PIN i[388]
    DIRECTION INPUT ;
    USE SIGNAL ;
    PORT
      LAYER M4 ;
        RECT  38.796 29.616 38.88 29.64 ;
    END
  END i[388]
  PIN i[389]
    DIRECTION INPUT ;
    USE SIGNAL ;
    PORT
      LAYER M4 ;
        RECT  38.796 29.712 38.88 29.736 ;
    END
  END i[389]
  PIN i[38]
    DIRECTION INPUT ;
    USE SIGNAL ;
    PORT
      LAYER M4 ;
        RECT  38.796 45.936 38.88 45.96 ;
    END
  END i[38]
  PIN i[390]
    DIRECTION INPUT ;
    USE SIGNAL ;
    PORT
      LAYER M4 ;
        RECT  38.796 29.808 38.88 29.832 ;
    END
  END i[390]
  PIN i[391]
    DIRECTION INPUT ;
    USE SIGNAL ;
    PORT
      LAYER M4 ;
        RECT  38.796 29.904 38.88 29.928 ;
    END
  END i[391]
  PIN i[392]
    DIRECTION INPUT ;
    USE SIGNAL ;
    PORT
      LAYER M4 ;
        RECT  38.796 30 38.88 30.024 ;
    END
  END i[392]
  PIN i[393]
    DIRECTION INPUT ;
    USE SIGNAL ;
    PORT
      LAYER M4 ;
        RECT  38.796 30.096 38.88 30.12 ;
    END
  END i[393]
  PIN i[394]
    DIRECTION INPUT ;
    USE SIGNAL ;
    PORT
      LAYER M4 ;
        RECT  38.796 30.192 38.88 30.216 ;
    END
  END i[394]
  PIN i[395]
    DIRECTION INPUT ;
    USE SIGNAL ;
    PORT
      LAYER M4 ;
        RECT  38.796 30.288 38.88 30.312 ;
    END
  END i[395]
  PIN i[396]
    DIRECTION INPUT ;
    USE SIGNAL ;
    PORT
      LAYER M4 ;
        RECT  38.796 30.384 38.88 30.408 ;
    END
  END i[396]
  PIN i[397]
    DIRECTION INPUT ;
    USE SIGNAL ;
    PORT
      LAYER M4 ;
        RECT  38.796 30.48 38.88 30.504 ;
    END
  END i[397]
  PIN i[398]
    DIRECTION INPUT ;
    USE SIGNAL ;
    PORT
      LAYER M4 ;
        RECT  38.796 30.576 38.88 30.6 ;
    END
  END i[398]
  PIN i[399]
    DIRECTION INPUT ;
    USE SIGNAL ;
    PORT
      LAYER M4 ;
        RECT  38.796 30.672 38.88 30.696 ;
    END
  END i[399]
  PIN i[39]
    DIRECTION INPUT ;
    USE SIGNAL ;
    PORT
      LAYER M4 ;
        RECT  38.796 46.032 38.88 46.056 ;
    END
  END i[39]
  PIN i[3]
    DIRECTION INPUT ;
    USE SIGNAL ;
    PORT
      LAYER M4 ;
        RECT  38.796 32.592 38.88 32.616 ;
    END
  END i[3]
  PIN i[400]
    DIRECTION INPUT ;
    USE SIGNAL ;
    PORT
      LAYER M4 ;
        RECT  38.796 30.768 38.88 30.792 ;
    END
  END i[400]
  PIN i[401]
    DIRECTION INPUT ;
    USE SIGNAL ;
    PORT
      LAYER M4 ;
        RECT  38.796 30.864 38.88 30.888 ;
    END
  END i[401]
  PIN i[402]
    DIRECTION INPUT ;
    USE SIGNAL ;
    PORT
      LAYER M4 ;
        RECT  38.796 30.96 38.88 30.984 ;
    END
  END i[402]
  PIN i[403]
    DIRECTION INPUT ;
    USE SIGNAL ;
    PORT
      LAYER M4 ;
        RECT  38.796 31.056 38.88 31.08 ;
    END
  END i[403]
  PIN i[404]
    DIRECTION INPUT ;
    USE SIGNAL ;
    PORT
      LAYER M4 ;
        RECT  38.796 31.152 38.88 31.176 ;
    END
  END i[404]
  PIN i[405]
    DIRECTION INPUT ;
    USE SIGNAL ;
    PORT
      LAYER M4 ;
        RECT  38.796 31.248 38.88 31.272 ;
    END
  END i[405]
  PIN i[406]
    DIRECTION INPUT ;
    USE SIGNAL ;
    PORT
      LAYER M4 ;
        RECT  38.796 31.344 38.88 31.368 ;
    END
  END i[406]
  PIN i[407]
    DIRECTION INPUT ;
    USE SIGNAL ;
    PORT
      LAYER M4 ;
        RECT  38.796 31.44 38.88 31.464 ;
    END
  END i[407]
  PIN i[408]
    DIRECTION INPUT ;
    USE SIGNAL ;
    PORT
      LAYER M4 ;
        RECT  38.796 31.536 38.88 31.56 ;
    END
  END i[408]
  PIN i[409]
    DIRECTION INPUT ;
    USE SIGNAL ;
    PORT
      LAYER M4 ;
        RECT  38.796 31.632 38.88 31.656 ;
    END
  END i[409]
  PIN i[40]
    DIRECTION INPUT ;
    USE SIGNAL ;
    PORT
      LAYER M4 ;
        RECT  38.796 46.128 38.88 46.152 ;
    END
  END i[40]
  PIN i[410]
    DIRECTION INPUT ;
    USE SIGNAL ;
    PORT
      LAYER M4 ;
        RECT  38.796 31.728 38.88 31.752 ;
    END
  END i[410]
  PIN i[411]
    DIRECTION INPUT ;
    USE SIGNAL ;
    PORT
      LAYER M4 ;
        RECT  38.796 31.824 38.88 31.848 ;
    END
  END i[411]
  PIN i[412]
    DIRECTION INPUT ;
    USE SIGNAL ;
    PORT
      LAYER M4 ;
        RECT  38.796 31.92 38.88 31.944 ;
    END
  END i[412]
  PIN i[413]
    DIRECTION INPUT ;
    USE SIGNAL ;
    PORT
      LAYER M4 ;
        RECT  38.796 32.016 38.88 32.04 ;
    END
  END i[413]
  PIN i[414]
    DIRECTION INPUT ;
    USE SIGNAL ;
    PORT
      LAYER M4 ;
        RECT  38.796 32.112 38.88 32.136 ;
    END
  END i[414]
  PIN i[415]
    DIRECTION INPUT ;
    USE SIGNAL ;
    PORT
      LAYER M4 ;
        RECT  38.796 16.08 38.88 16.104 ;
    END
  END i[415]
  PIN i[416]
    DIRECTION INPUT ;
    USE SIGNAL ;
    PORT
      LAYER M4 ;
        RECT  38.796 16.176 38.88 16.2 ;
    END
  END i[416]
  PIN i[417]
    DIRECTION INPUT ;
    USE SIGNAL ;
    PORT
      LAYER M4 ;
        RECT  38.796 16.272 38.88 16.296 ;
    END
  END i[417]
  PIN i[418]
    DIRECTION INPUT ;
    USE SIGNAL ;
    PORT
      LAYER M4 ;
        RECT  38.796 16.368 38.88 16.392 ;
    END
  END i[418]
  PIN i[419]
    DIRECTION INPUT ;
    USE SIGNAL ;
    PORT
      LAYER M4 ;
        RECT  38.796 16.464 38.88 16.488 ;
    END
  END i[419]
  PIN i[41]
    DIRECTION INPUT ;
    USE SIGNAL ;
    PORT
      LAYER M4 ;
        RECT  38.796 46.224 38.88 46.248 ;
    END
  END i[41]
  PIN i[420]
    DIRECTION INPUT ;
    USE SIGNAL ;
    PORT
      LAYER M4 ;
        RECT  38.796 16.56 38.88 16.584 ;
    END
  END i[420]
  PIN i[421]
    DIRECTION INPUT ;
    USE SIGNAL ;
    PORT
      LAYER M4 ;
        RECT  38.796 16.656 38.88 16.68 ;
    END
  END i[421]
  PIN i[422]
    DIRECTION INPUT ;
    USE SIGNAL ;
    PORT
      LAYER M4 ;
        RECT  38.796 16.752 38.88 16.776 ;
    END
  END i[422]
  PIN i[423]
    DIRECTION INPUT ;
    USE SIGNAL ;
    PORT
      LAYER M4 ;
        RECT  38.796 16.848 38.88 16.872 ;
    END
  END i[423]
  PIN i[424]
    DIRECTION INPUT ;
    USE SIGNAL ;
    PORT
      LAYER M4 ;
        RECT  38.796 16.944 38.88 16.968 ;
    END
  END i[424]
  PIN i[425]
    DIRECTION INPUT ;
    USE SIGNAL ;
    PORT
      LAYER M4 ;
        RECT  38.796 17.04 38.88 17.064 ;
    END
  END i[425]
  PIN i[426]
    DIRECTION INPUT ;
    USE SIGNAL ;
    PORT
      LAYER M4 ;
        RECT  38.796 17.136 38.88 17.16 ;
    END
  END i[426]
  PIN i[427]
    DIRECTION INPUT ;
    USE SIGNAL ;
    PORT
      LAYER M4 ;
        RECT  38.796 17.232 38.88 17.256 ;
    END
  END i[427]
  PIN i[428]
    DIRECTION INPUT ;
    USE SIGNAL ;
    PORT
      LAYER M4 ;
        RECT  38.796 17.328 38.88 17.352 ;
    END
  END i[428]
  PIN i[429]
    DIRECTION INPUT ;
    USE SIGNAL ;
    PORT
      LAYER M4 ;
        RECT  38.796 17.424 38.88 17.448 ;
    END
  END i[429]
  PIN i[42]
    DIRECTION INPUT ;
    USE SIGNAL ;
    PORT
      LAYER M4 ;
        RECT  38.796 46.32 38.88 46.344 ;
    END
  END i[42]
  PIN i[430]
    DIRECTION INPUT ;
    USE SIGNAL ;
    PORT
      LAYER M4 ;
        RECT  38.796 17.52 38.88 17.544 ;
    END
  END i[430]
  PIN i[431]
    DIRECTION INPUT ;
    USE SIGNAL ;
    PORT
      LAYER M4 ;
        RECT  38.796 17.616 38.88 17.64 ;
    END
  END i[431]
  PIN i[432]
    DIRECTION INPUT ;
    USE SIGNAL ;
    PORT
      LAYER M4 ;
        RECT  38.796 17.712 38.88 17.736 ;
    END
  END i[432]
  PIN i[433]
    DIRECTION INPUT ;
    USE SIGNAL ;
    PORT
      LAYER M4 ;
        RECT  38.796 17.808 38.88 17.832 ;
    END
  END i[433]
  PIN i[434]
    DIRECTION INPUT ;
    USE SIGNAL ;
    PORT
      LAYER M4 ;
        RECT  38.796 17.904 38.88 17.928 ;
    END
  END i[434]
  PIN i[435]
    DIRECTION INPUT ;
    USE SIGNAL ;
    PORT
      LAYER M4 ;
        RECT  38.796 18 38.88 18.024 ;
    END
  END i[435]
  PIN i[436]
    DIRECTION INPUT ;
    USE SIGNAL ;
    PORT
      LAYER M4 ;
        RECT  38.796 18.096 38.88 18.12 ;
    END
  END i[436]
  PIN i[437]
    DIRECTION INPUT ;
    USE SIGNAL ;
    PORT
      LAYER M4 ;
        RECT  38.796 18.192 38.88 18.216 ;
    END
  END i[437]
  PIN i[438]
    DIRECTION INPUT ;
    USE SIGNAL ;
    PORT
      LAYER M4 ;
        RECT  38.796 18.288 38.88 18.312 ;
    END
  END i[438]
  PIN i[439]
    DIRECTION INPUT ;
    USE SIGNAL ;
    PORT
      LAYER M4 ;
        RECT  38.796 18.384 38.88 18.408 ;
    END
  END i[439]
  PIN i[43]
    DIRECTION INPUT ;
    USE SIGNAL ;
    PORT
      LAYER M4 ;
        RECT  38.796 46.416 38.88 46.44 ;
    END
  END i[43]
  PIN i[440]
    DIRECTION INPUT ;
    USE SIGNAL ;
    PORT
      LAYER M4 ;
        RECT  38.796 18.48 38.88 18.504 ;
    END
  END i[440]
  PIN i[441]
    DIRECTION INPUT ;
    USE SIGNAL ;
    PORT
      LAYER M4 ;
        RECT  38.796 18.576 38.88 18.6 ;
    END
  END i[441]
  PIN i[442]
    DIRECTION INPUT ;
    USE SIGNAL ;
    PORT
      LAYER M4 ;
        RECT  38.796 18.672 38.88 18.696 ;
    END
  END i[442]
  PIN i[443]
    DIRECTION INPUT ;
    USE SIGNAL ;
    PORT
      LAYER M4 ;
        RECT  38.796 18.768 38.88 18.792 ;
    END
  END i[443]
  PIN i[444]
    DIRECTION INPUT ;
    USE SIGNAL ;
    PORT
      LAYER M4 ;
        RECT  38.796 18.864 38.88 18.888 ;
    END
  END i[444]
  PIN i[445]
    DIRECTION INPUT ;
    USE SIGNAL ;
    PORT
      LAYER M4 ;
        RECT  38.796 18.96 38.88 18.984 ;
    END
  END i[445]
  PIN i[446]
    DIRECTION INPUT ;
    USE SIGNAL ;
    PORT
      LAYER M4 ;
        RECT  38.796 19.056 38.88 19.08 ;
    END
  END i[446]
  PIN i[447]
    DIRECTION INPUT ;
    USE SIGNAL ;
    PORT
      LAYER M4 ;
        RECT  38.796 6.864 38.88 6.888 ;
    END
  END i[447]
  PIN i[448]
    DIRECTION INPUT ;
    USE SIGNAL ;
    PORT
      LAYER M4 ;
        RECT  38.796 6.96 38.88 6.984 ;
    END
  END i[448]
  PIN i[449]
    DIRECTION INPUT ;
    USE SIGNAL ;
    PORT
      LAYER M4 ;
        RECT  38.796 7.056 38.88 7.08 ;
    END
  END i[449]
  PIN i[44]
    DIRECTION INPUT ;
    USE SIGNAL ;
    PORT
      LAYER M4 ;
        RECT  38.796 46.512 38.88 46.536 ;
    END
  END i[44]
  PIN i[450]
    DIRECTION INPUT ;
    USE SIGNAL ;
    PORT
      LAYER M4 ;
        RECT  38.796 7.152 38.88 7.176 ;
    END
  END i[450]
  PIN i[451]
    DIRECTION INPUT ;
    USE SIGNAL ;
    PORT
      LAYER M4 ;
        RECT  38.796 7.248 38.88 7.272 ;
    END
  END i[451]
  PIN i[452]
    DIRECTION INPUT ;
    USE SIGNAL ;
    PORT
      LAYER M4 ;
        RECT  38.796 7.344 38.88 7.368 ;
    END
  END i[452]
  PIN i[453]
    DIRECTION INPUT ;
    USE SIGNAL ;
    PORT
      LAYER M4 ;
        RECT  38.796 7.44 38.88 7.464 ;
    END
  END i[453]
  PIN i[454]
    DIRECTION INPUT ;
    USE SIGNAL ;
    PORT
      LAYER M4 ;
        RECT  38.796 7.536 38.88 7.56 ;
    END
  END i[454]
  PIN i[455]
    DIRECTION INPUT ;
    USE SIGNAL ;
    PORT
      LAYER M4 ;
        RECT  38.796 7.632 38.88 7.656 ;
    END
  END i[455]
  PIN i[456]
    DIRECTION INPUT ;
    USE SIGNAL ;
    PORT
      LAYER M4 ;
        RECT  38.796 7.728 38.88 7.752 ;
    END
  END i[456]
  PIN i[457]
    DIRECTION INPUT ;
    USE SIGNAL ;
    PORT
      LAYER M4 ;
        RECT  38.796 7.824 38.88 7.848 ;
    END
  END i[457]
  PIN i[458]
    DIRECTION INPUT ;
    USE SIGNAL ;
    PORT
      LAYER M4 ;
        RECT  38.796 7.92 38.88 7.944 ;
    END
  END i[458]
  PIN i[459]
    DIRECTION INPUT ;
    USE SIGNAL ;
    PORT
      LAYER M4 ;
        RECT  38.796 8.016 38.88 8.04 ;
    END
  END i[459]
  PIN i[45]
    DIRECTION INPUT ;
    USE SIGNAL ;
    PORT
      LAYER M4 ;
        RECT  38.796 46.608 38.88 46.632 ;
    END
  END i[45]
  PIN i[460]
    DIRECTION INPUT ;
    USE SIGNAL ;
    PORT
      LAYER M4 ;
        RECT  38.796 8.112 38.88 8.136 ;
    END
  END i[460]
  PIN i[461]
    DIRECTION INPUT ;
    USE SIGNAL ;
    PORT
      LAYER M4 ;
        RECT  38.796 8.208 38.88 8.232 ;
    END
  END i[461]
  PIN i[462]
    DIRECTION INPUT ;
    USE SIGNAL ;
    PORT
      LAYER M4 ;
        RECT  38.796 8.304 38.88 8.328 ;
    END
  END i[462]
  PIN i[463]
    DIRECTION INPUT ;
    USE SIGNAL ;
    PORT
      LAYER M4 ;
        RECT  38.796 8.4 38.88 8.424 ;
    END
  END i[463]
  PIN i[464]
    DIRECTION INPUT ;
    USE SIGNAL ;
    PORT
      LAYER M4 ;
        RECT  38.796 8.496 38.88 8.52 ;
    END
  END i[464]
  PIN i[465]
    DIRECTION INPUT ;
    USE SIGNAL ;
    PORT
      LAYER M4 ;
        RECT  38.796 8.592 38.88 8.616 ;
    END
  END i[465]
  PIN i[466]
    DIRECTION INPUT ;
    USE SIGNAL ;
    PORT
      LAYER M4 ;
        RECT  38.796 8.688 38.88 8.712 ;
    END
  END i[466]
  PIN i[467]
    DIRECTION INPUT ;
    USE SIGNAL ;
    PORT
      LAYER M4 ;
        RECT  38.796 8.784 38.88 8.808 ;
    END
  END i[467]
  PIN i[468]
    DIRECTION INPUT ;
    USE SIGNAL ;
    PORT
      LAYER M4 ;
        RECT  38.796 8.88 38.88 8.904 ;
    END
  END i[468]
  PIN i[469]
    DIRECTION INPUT ;
    USE SIGNAL ;
    PORT
      LAYER M4 ;
        RECT  38.796 8.976 38.88 9 ;
    END
  END i[469]
  PIN i[46]
    DIRECTION INPUT ;
    USE SIGNAL ;
    PORT
      LAYER M4 ;
        RECT  38.796 46.704 38.88 46.728 ;
    END
  END i[46]
  PIN i[470]
    DIRECTION INPUT ;
    USE SIGNAL ;
    PORT
      LAYER M4 ;
        RECT  38.796 9.072 38.88 9.096 ;
    END
  END i[470]
  PIN i[471]
    DIRECTION INPUT ;
    USE SIGNAL ;
    PORT
      LAYER M4 ;
        RECT  38.796 9.168 38.88 9.192 ;
    END
  END i[471]
  PIN i[472]
    DIRECTION INPUT ;
    USE SIGNAL ;
    PORT
      LAYER M4 ;
        RECT  38.796 9.264 38.88 9.288 ;
    END
  END i[472]
  PIN i[473]
    DIRECTION INPUT ;
    USE SIGNAL ;
    PORT
      LAYER M4 ;
        RECT  38.796 9.36 38.88 9.384 ;
    END
  END i[473]
  PIN i[474]
    DIRECTION INPUT ;
    USE SIGNAL ;
    PORT
      LAYER M4 ;
        RECT  38.796 9.456 38.88 9.48 ;
    END
  END i[474]
  PIN i[475]
    DIRECTION INPUT ;
    USE SIGNAL ;
    PORT
      LAYER M4 ;
        RECT  38.796 9.552 38.88 9.576 ;
    END
  END i[475]
  PIN i[476]
    DIRECTION INPUT ;
    USE SIGNAL ;
    PORT
      LAYER M4 ;
        RECT  38.796 9.648 38.88 9.672 ;
    END
  END i[476]
  PIN i[477]
    DIRECTION INPUT ;
    USE SIGNAL ;
    PORT
      LAYER M4 ;
        RECT  38.796 9.744 38.88 9.768 ;
    END
  END i[477]
  PIN i[478]
    DIRECTION INPUT ;
    USE SIGNAL ;
    PORT
      LAYER M4 ;
        RECT  38.796 9.84 38.88 9.864 ;
    END
  END i[478]
  PIN i[479]
    DIRECTION INPUT ;
    USE SIGNAL ;
    PORT
      LAYER M4 ;
        RECT  38.796 9.936 38.88 9.96 ;
    END
  END i[479]
  PIN i[47]
    DIRECTION INPUT ;
    USE SIGNAL ;
    PORT
      LAYER M4 ;
        RECT  38.796 46.8 38.88 46.824 ;
    END
  END i[47]
  PIN i[480]
    DIRECTION INPUT ;
    USE SIGNAL ;
    PORT
      LAYER M4 ;
        RECT  38.796 10.032 38.88 10.056 ;
    END
  END i[480]
  PIN i[481]
    DIRECTION INPUT ;
    USE SIGNAL ;
    PORT
      LAYER M4 ;
        RECT  38.796 10.128 38.88 10.152 ;
    END
  END i[481]
  PIN i[482]
    DIRECTION INPUT ;
    USE SIGNAL ;
    PORT
      LAYER M4 ;
        RECT  38.796 10.224 38.88 10.248 ;
    END
  END i[482]
  PIN i[483]
    DIRECTION INPUT ;
    USE SIGNAL ;
    PORT
      LAYER M4 ;
        RECT  38.796 10.32 38.88 10.344 ;
    END
  END i[483]
  PIN i[484]
    DIRECTION INPUT ;
    USE SIGNAL ;
    PORT
      LAYER M4 ;
        RECT  38.796 10.416 38.88 10.44 ;
    END
  END i[484]
  PIN i[485]
    DIRECTION INPUT ;
    USE SIGNAL ;
    PORT
      LAYER M4 ;
        RECT  38.796 10.512 38.88 10.536 ;
    END
  END i[485]
  PIN i[486]
    DIRECTION INPUT ;
    USE SIGNAL ;
    PORT
      LAYER M4 ;
        RECT  38.796 10.608 38.88 10.632 ;
    END
  END i[486]
  PIN i[487]
    DIRECTION INPUT ;
    USE SIGNAL ;
    PORT
      LAYER M4 ;
        RECT  38.796 10.704 38.88 10.728 ;
    END
  END i[487]
  PIN i[488]
    DIRECTION INPUT ;
    USE SIGNAL ;
    PORT
      LAYER M4 ;
        RECT  38.796 10.8 38.88 10.824 ;
    END
  END i[488]
  PIN i[489]
    DIRECTION INPUT ;
    USE SIGNAL ;
    PORT
      LAYER M4 ;
        RECT  38.796 10.896 38.88 10.92 ;
    END
  END i[489]
  PIN i[48]
    DIRECTION INPUT ;
    USE SIGNAL ;
    PORT
      LAYER M4 ;
        RECT  38.796 46.896 38.88 46.92 ;
    END
  END i[48]
  PIN i[490]
    DIRECTION INPUT ;
    USE SIGNAL ;
    PORT
      LAYER M4 ;
        RECT  38.796 10.992 38.88 11.016 ;
    END
  END i[490]
  PIN i[491]
    DIRECTION INPUT ;
    USE SIGNAL ;
    PORT
      LAYER M4 ;
        RECT  38.796 11.088 38.88 11.112 ;
    END
  END i[491]
  PIN i[492]
    DIRECTION INPUT ;
    USE SIGNAL ;
    PORT
      LAYER M4 ;
        RECT  38.796 11.184 38.88 11.208 ;
    END
  END i[492]
  PIN i[493]
    DIRECTION INPUT ;
    USE SIGNAL ;
    PORT
      LAYER M4 ;
        RECT  38.796 11.28 38.88 11.304 ;
    END
  END i[493]
  PIN i[494]
    DIRECTION INPUT ;
    USE SIGNAL ;
    PORT
      LAYER M4 ;
        RECT  38.796 11.376 38.88 11.4 ;
    END
  END i[494]
  PIN i[495]
    DIRECTION INPUT ;
    USE SIGNAL ;
    PORT
      LAYER M4 ;
        RECT  38.796 11.472 38.88 11.496 ;
    END
  END i[495]
  PIN i[496]
    DIRECTION INPUT ;
    USE SIGNAL ;
    PORT
      LAYER M4 ;
        RECT  38.796 11.568 38.88 11.592 ;
    END
  END i[496]
  PIN i[497]
    DIRECTION INPUT ;
    USE SIGNAL ;
    PORT
      LAYER M4 ;
        RECT  38.796 11.664 38.88 11.688 ;
    END
  END i[497]
  PIN i[498]
    DIRECTION INPUT ;
    USE SIGNAL ;
    PORT
      LAYER M4 ;
        RECT  38.796 11.76 38.88 11.784 ;
    END
  END i[498]
  PIN i[499]
    DIRECTION INPUT ;
    USE SIGNAL ;
    PORT
      LAYER M4 ;
        RECT  38.796 11.856 38.88 11.88 ;
    END
  END i[499]
  PIN i[49]
    DIRECTION INPUT ;
    USE SIGNAL ;
    PORT
      LAYER M4 ;
        RECT  38.796 46.992 38.88 47.016 ;
    END
  END i[49]
  PIN i[4]
    DIRECTION INPUT ;
    USE SIGNAL ;
    PORT
      LAYER M4 ;
        RECT  38.796 32.688 38.88 32.712 ;
    END
  END i[4]
  PIN i[500]
    DIRECTION INPUT ;
    USE SIGNAL ;
    PORT
      LAYER M4 ;
        RECT  38.796 11.952 38.88 11.976 ;
    END
  END i[500]
  PIN i[501]
    DIRECTION INPUT ;
    USE SIGNAL ;
    PORT
      LAYER M4 ;
        RECT  38.796 12.048 38.88 12.072 ;
    END
  END i[501]
  PIN i[502]
    DIRECTION INPUT ;
    USE SIGNAL ;
    PORT
      LAYER M4 ;
        RECT  38.796 12.144 38.88 12.168 ;
    END
  END i[502]
  PIN i[503]
    DIRECTION INPUT ;
    USE SIGNAL ;
    PORT
      LAYER M4 ;
        RECT  38.796 12.24 38.88 12.264 ;
    END
  END i[503]
  PIN i[504]
    DIRECTION INPUT ;
    USE SIGNAL ;
    PORT
      LAYER M4 ;
        RECT  38.796 12.336 38.88 12.36 ;
    END
  END i[504]
  PIN i[505]
    DIRECTION INPUT ;
    USE SIGNAL ;
    PORT
      LAYER M4 ;
        RECT  38.796 12.432 38.88 12.456 ;
    END
  END i[505]
  PIN i[506]
    DIRECTION INPUT ;
    USE SIGNAL ;
    PORT
      LAYER M4 ;
        RECT  38.796 12.528 38.88 12.552 ;
    END
  END i[506]
  PIN i[507]
    DIRECTION INPUT ;
    USE SIGNAL ;
    PORT
      LAYER M4 ;
        RECT  38.796 12.624 38.88 12.648 ;
    END
  END i[507]
  PIN i[508]
    DIRECTION INPUT ;
    USE SIGNAL ;
    PORT
      LAYER M4 ;
        RECT  38.796 12.72 38.88 12.744 ;
    END
  END i[508]
  PIN i[509]
    DIRECTION INPUT ;
    USE SIGNAL ;
    PORT
      LAYER M4 ;
        RECT  38.796 12.816 38.88 12.84 ;
    END
  END i[509]
  PIN i[50]
    DIRECTION INPUT ;
    USE SIGNAL ;
    PORT
      LAYER M4 ;
        RECT  38.796 47.088 38.88 47.112 ;
    END
  END i[50]
  PIN i[510]
    DIRECTION INPUT ;
    USE SIGNAL ;
    PORT
      LAYER M4 ;
        RECT  38.796 12.912 38.88 12.936 ;
    END
  END i[510]
  PIN i[511]
    DIRECTION INPUT ;
    USE SIGNAL ;
    PORT
      LAYER M4 ;
        RECT  38.796 13.008 38.88 13.032 ;
    END
  END i[511]
  PIN i[512]
    DIRECTION INPUT ;
    USE SIGNAL ;
    PORT
      LAYER M4 ;
        RECT  38.796 13.104 38.88 13.128 ;
    END
  END i[512]
  PIN i[513]
    DIRECTION INPUT ;
    USE SIGNAL ;
    PORT
      LAYER M4 ;
        RECT  38.796 13.2 38.88 13.224 ;
    END
  END i[513]
  PIN i[514]
    DIRECTION INPUT ;
    USE SIGNAL ;
    PORT
      LAYER M4 ;
        RECT  38.796 13.296 38.88 13.32 ;
    END
  END i[514]
  PIN i[515]
    DIRECTION INPUT ;
    USE SIGNAL ;
    PORT
      LAYER M4 ;
        RECT  38.796 13.392 38.88 13.416 ;
    END
  END i[515]
  PIN i[516]
    DIRECTION INPUT ;
    USE SIGNAL ;
    PORT
      LAYER M4 ;
        RECT  38.796 13.488 38.88 13.512 ;
    END
  END i[516]
  PIN i[517]
    DIRECTION INPUT ;
    USE SIGNAL ;
    PORT
      LAYER M4 ;
        RECT  38.796 13.584 38.88 13.608 ;
    END
  END i[517]
  PIN i[518]
    DIRECTION INPUT ;
    USE SIGNAL ;
    PORT
      LAYER M4 ;
        RECT  38.796 13.68 38.88 13.704 ;
    END
  END i[518]
  PIN i[519]
    DIRECTION INPUT ;
    USE SIGNAL ;
    PORT
      LAYER M4 ;
        RECT  38.796 13.776 38.88 13.8 ;
    END
  END i[519]
  PIN i[51]
    DIRECTION INPUT ;
    USE SIGNAL ;
    PORT
      LAYER M4 ;
        RECT  38.796 47.184 38.88 47.208 ;
    END
  END i[51]
  PIN i[520]
    DIRECTION INPUT ;
    USE SIGNAL ;
    PORT
      LAYER M4 ;
        RECT  38.796 13.872 38.88 13.896 ;
    END
  END i[520]
  PIN i[521]
    DIRECTION INPUT ;
    USE SIGNAL ;
    PORT
      LAYER M4 ;
        RECT  38.796 13.968 38.88 13.992 ;
    END
  END i[521]
  PIN i[522]
    DIRECTION INPUT ;
    USE SIGNAL ;
    PORT
      LAYER M4 ;
        RECT  38.796 14.064 38.88 14.088 ;
    END
  END i[522]
  PIN i[523]
    DIRECTION INPUT ;
    USE SIGNAL ;
    PORT
      LAYER M4 ;
        RECT  38.796 14.16 38.88 14.184 ;
    END
  END i[523]
  PIN i[524]
    DIRECTION INPUT ;
    USE SIGNAL ;
    PORT
      LAYER M4 ;
        RECT  38.796 14.256 38.88 14.28 ;
    END
  END i[524]
  PIN i[525]
    DIRECTION INPUT ;
    USE SIGNAL ;
    PORT
      LAYER M4 ;
        RECT  38.796 14.352 38.88 14.376 ;
    END
  END i[525]
  PIN i[526]
    DIRECTION INPUT ;
    USE SIGNAL ;
    PORT
      LAYER M4 ;
        RECT  38.796 14.448 38.88 14.472 ;
    END
  END i[526]
  PIN i[527]
    DIRECTION INPUT ;
    USE SIGNAL ;
    PORT
      LAYER M4 ;
        RECT  38.796 14.544 38.88 14.568 ;
    END
  END i[527]
  PIN i[528]
    DIRECTION INPUT ;
    USE SIGNAL ;
    PORT
      LAYER M4 ;
        RECT  38.796 14.64 38.88 14.664 ;
    END
  END i[528]
  PIN i[529]
    DIRECTION INPUT ;
    USE SIGNAL ;
    PORT
      LAYER M4 ;
        RECT  38.796 14.736 38.88 14.76 ;
    END
  END i[529]
  PIN i[52]
    DIRECTION INPUT ;
    USE SIGNAL ;
    PORT
      LAYER M4 ;
        RECT  38.796 47.28 38.88 47.304 ;
    END
  END i[52]
  PIN i[530]
    DIRECTION INPUT ;
    USE SIGNAL ;
    PORT
      LAYER M4 ;
        RECT  38.796 14.832 38.88 14.856 ;
    END
  END i[530]
  PIN i[531]
    DIRECTION INPUT ;
    USE SIGNAL ;
    PORT
      LAYER M4 ;
        RECT  38.796 14.928 38.88 14.952 ;
    END
  END i[531]
  PIN i[532]
    DIRECTION INPUT ;
    USE SIGNAL ;
    PORT
      LAYER M4 ;
        RECT  38.796 15.024 38.88 15.048 ;
    END
  END i[532]
  PIN i[533]
    DIRECTION INPUT ;
    USE SIGNAL ;
    PORT
      LAYER M4 ;
        RECT  38.796 15.12 38.88 15.144 ;
    END
  END i[533]
  PIN i[534]
    DIRECTION INPUT ;
    USE SIGNAL ;
    PORT
      LAYER M4 ;
        RECT  38.796 15.216 38.88 15.24 ;
    END
  END i[534]
  PIN i[535]
    DIRECTION INPUT ;
    USE SIGNAL ;
    PORT
      LAYER M4 ;
        RECT  38.796 15.312 38.88 15.336 ;
    END
  END i[535]
  PIN i[536]
    DIRECTION INPUT ;
    USE SIGNAL ;
    PORT
      LAYER M4 ;
        RECT  38.796 15.408 38.88 15.432 ;
    END
  END i[536]
  PIN i[537]
    DIRECTION INPUT ;
    USE SIGNAL ;
    PORT
      LAYER M4 ;
        RECT  38.796 15.504 38.88 15.528 ;
    END
  END i[537]
  PIN i[538]
    DIRECTION INPUT ;
    USE SIGNAL ;
    PORT
      LAYER M4 ;
        RECT  38.796 15.6 38.88 15.624 ;
    END
  END i[538]
  PIN i[539]
    DIRECTION INPUT ;
    USE SIGNAL ;
    PORT
      LAYER M4 ;
        RECT  38.796 15.696 38.88 15.72 ;
    END
  END i[539]
  PIN i[53]
    DIRECTION INPUT ;
    USE SIGNAL ;
    PORT
      LAYER M4 ;
        RECT  38.796 47.376 38.88 47.4 ;
    END
  END i[53]
  PIN i[540]
    DIRECTION INPUT ;
    USE SIGNAL ;
    PORT
      LAYER M4 ;
        RECT  38.796 15.792 38.88 15.816 ;
    END
  END i[540]
  PIN i[541]
    DIRECTION INPUT ;
    USE SIGNAL ;
    PORT
      LAYER M4 ;
        RECT  38.796 15.888 38.88 15.912 ;
    END
  END i[541]
  PIN i[542]
    DIRECTION INPUT ;
    USE SIGNAL ;
    PORT
      LAYER M4 ;
        RECT  38.796 15.984 38.88 16.008 ;
    END
  END i[542]
  PIN i[543]
    DIRECTION INPUT ;
    USE SIGNAL ;
    PORT
      LAYER M4 ;
        RECT  38.796 22.992 38.88 23.016 ;
    END
  END i[543]
  PIN i[544]
    DIRECTION INPUT ;
    USE SIGNAL ;
    PORT
      LAYER M4 ;
        RECT  38.796 23.088 38.88 23.112 ;
    END
  END i[544]
  PIN i[545]
    DIRECTION INPUT ;
    USE SIGNAL ;
    PORT
      LAYER M4 ;
        RECT  38.796 23.184 38.88 23.208 ;
    END
  END i[545]
  PIN i[546]
    DIRECTION INPUT ;
    USE SIGNAL ;
    PORT
      LAYER M4 ;
        RECT  38.796 23.28 38.88 23.304 ;
    END
  END i[546]
  PIN i[547]
    DIRECTION INPUT ;
    USE SIGNAL ;
    PORT
      LAYER M4 ;
        RECT  38.796 23.376 38.88 23.4 ;
    END
  END i[547]
  PIN i[548]
    DIRECTION INPUT ;
    USE SIGNAL ;
    PORT
      LAYER M4 ;
        RECT  38.796 23.472 38.88 23.496 ;
    END
  END i[548]
  PIN i[549]
    DIRECTION INPUT ;
    USE SIGNAL ;
    PORT
      LAYER M4 ;
        RECT  38.796 23.568 38.88 23.592 ;
    END
  END i[549]
  PIN i[54]
    DIRECTION INPUT ;
    USE SIGNAL ;
    PORT
      LAYER M4 ;
        RECT  38.796 47.472 38.88 47.496 ;
    END
  END i[54]
  PIN i[550]
    DIRECTION INPUT ;
    USE SIGNAL ;
    PORT
      LAYER M4 ;
        RECT  38.796 23.664 38.88 23.688 ;
    END
  END i[550]
  PIN i[551]
    DIRECTION INPUT ;
    USE SIGNAL ;
    PORT
      LAYER M4 ;
        RECT  38.796 23.76 38.88 23.784 ;
    END
  END i[551]
  PIN i[552]
    DIRECTION INPUT ;
    USE SIGNAL ;
    PORT
      LAYER M4 ;
        RECT  38.796 23.856 38.88 23.88 ;
    END
  END i[552]
  PIN i[553]
    DIRECTION INPUT ;
    USE SIGNAL ;
    PORT
      LAYER M4 ;
        RECT  38.796 23.952 38.88 23.976 ;
    END
  END i[553]
  PIN i[554]
    DIRECTION INPUT ;
    USE SIGNAL ;
    PORT
      LAYER M4 ;
        RECT  38.796 24.048 38.88 24.072 ;
    END
  END i[554]
  PIN i[555]
    DIRECTION INPUT ;
    USE SIGNAL ;
    PORT
      LAYER M4 ;
        RECT  38.796 24.144 38.88 24.168 ;
    END
  END i[555]
  PIN i[556]
    DIRECTION INPUT ;
    USE SIGNAL ;
    PORT
      LAYER M4 ;
        RECT  38.796 24.24 38.88 24.264 ;
    END
  END i[556]
  PIN i[557]
    DIRECTION INPUT ;
    USE SIGNAL ;
    PORT
      LAYER M4 ;
        RECT  38.796 24.336 38.88 24.36 ;
    END
  END i[557]
  PIN i[558]
    DIRECTION INPUT ;
    USE SIGNAL ;
    PORT
      LAYER M4 ;
        RECT  38.796 24.432 38.88 24.456 ;
    END
  END i[558]
  PIN i[559]
    DIRECTION INPUT ;
    USE SIGNAL ;
    PORT
      LAYER M4 ;
        RECT  38.796 24.528 38.88 24.552 ;
    END
  END i[559]
  PIN i[55]
    DIRECTION INPUT ;
    USE SIGNAL ;
    PORT
      LAYER M4 ;
        RECT  38.796 47.568 38.88 47.592 ;
    END
  END i[55]
  PIN i[560]
    DIRECTION INPUT ;
    USE SIGNAL ;
    PORT
      LAYER M4 ;
        RECT  38.796 24.624 38.88 24.648 ;
    END
  END i[560]
  PIN i[561]
    DIRECTION INPUT ;
    USE SIGNAL ;
    PORT
      LAYER M4 ;
        RECT  38.796 24.72 38.88 24.744 ;
    END
  END i[561]
  PIN i[56]
    DIRECTION INPUT ;
    USE SIGNAL ;
    PORT
      LAYER M4 ;
        RECT  38.796 47.664 38.88 47.688 ;
    END
  END i[56]
  PIN i[57]
    DIRECTION INPUT ;
    USE SIGNAL ;
    PORT
      LAYER M4 ;
        RECT  38.796 47.76 38.88 47.784 ;
    END
  END i[57]
  PIN i[58]
    DIRECTION INPUT ;
    USE SIGNAL ;
    PORT
      LAYER M4 ;
        RECT  38.796 47.856 38.88 47.88 ;
    END
  END i[58]
  PIN i[59]
    DIRECTION INPUT ;
    USE SIGNAL ;
    PORT
      LAYER M4 ;
        RECT  38.796 47.952 38.88 47.976 ;
    END
  END i[59]
  PIN i[5]
    DIRECTION INPUT ;
    USE SIGNAL ;
    PORT
      LAYER M4 ;
        RECT  38.796 32.784 38.88 32.808 ;
    END
  END i[5]
  PIN i[60]
    DIRECTION INPUT ;
    USE SIGNAL ;
    PORT
      LAYER M4 ;
        RECT  38.796 48.048 38.88 48.072 ;
    END
  END i[60]
  PIN i[61]
    DIRECTION INPUT ;
    USE SIGNAL ;
    PORT
      LAYER M4 ;
        RECT  38.796 48.144 38.88 48.168 ;
    END
  END i[61]
  PIN i[62]
    DIRECTION INPUT ;
    USE SIGNAL ;
    PORT
      LAYER M4 ;
        RECT  38.796 48.24 38.88 48.264 ;
    END
  END i[62]
  PIN i[63]
    DIRECTION INPUT ;
    USE SIGNAL ;
    PORT
      LAYER M4 ;
        RECT  38.796 54.48 38.88 54.504 ;
    END
  END i[63]
  PIN i[64]
    DIRECTION INPUT ;
    USE SIGNAL ;
    PORT
      LAYER M4 ;
        RECT  38.796 54.576 38.88 54.6 ;
    END
  END i[64]
  PIN i[65]
    DIRECTION INPUT ;
    USE SIGNAL ;
    PORT
      LAYER M4 ;
        RECT  38.796 54.672 38.88 54.696 ;
    END
  END i[65]
  PIN i[66]
    DIRECTION INPUT ;
    USE SIGNAL ;
    PORT
      LAYER M4 ;
        RECT  38.796 54.768 38.88 54.792 ;
    END
  END i[66]
  PIN i[67]
    DIRECTION INPUT ;
    USE SIGNAL ;
    PORT
      LAYER M4 ;
        RECT  38.796 54.864 38.88 54.888 ;
    END
  END i[67]
  PIN i[68]
    DIRECTION INPUT ;
    USE SIGNAL ;
    PORT
      LAYER M4 ;
        RECT  38.796 54.96 38.88 54.984 ;
    END
  END i[68]
  PIN i[69]
    DIRECTION INPUT ;
    USE SIGNAL ;
    PORT
      LAYER M4 ;
        RECT  38.796 55.056 38.88 55.08 ;
    END
  END i[69]
  PIN i[6]
    DIRECTION INPUT ;
    USE SIGNAL ;
    PORT
      LAYER M4 ;
        RECT  38.796 32.88 38.88 32.904 ;
    END
  END i[6]
  PIN i[70]
    DIRECTION INPUT ;
    USE SIGNAL ;
    PORT
      LAYER M4 ;
        RECT  38.796 55.152 38.88 55.176 ;
    END
  END i[70]
  PIN i[71]
    DIRECTION INPUT ;
    USE SIGNAL ;
    PORT
      LAYER M4 ;
        RECT  38.796 55.248 38.88 55.272 ;
    END
  END i[71]
  PIN i[72]
    DIRECTION INPUT ;
    USE SIGNAL ;
    PORT
      LAYER M4 ;
        RECT  38.796 55.344 38.88 55.368 ;
    END
  END i[72]
  PIN i[73]
    DIRECTION INPUT ;
    USE SIGNAL ;
    PORT
      LAYER M4 ;
        RECT  38.796 55.44 38.88 55.464 ;
    END
  END i[73]
  PIN i[74]
    DIRECTION INPUT ;
    USE SIGNAL ;
    PORT
      LAYER M4 ;
        RECT  38.796 55.536 38.88 55.56 ;
    END
  END i[74]
  PIN i[75]
    DIRECTION INPUT ;
    USE SIGNAL ;
    PORT
      LAYER M4 ;
        RECT  38.796 55.632 38.88 55.656 ;
    END
  END i[75]
  PIN i[76]
    DIRECTION INPUT ;
    USE SIGNAL ;
    PORT
      LAYER M4 ;
        RECT  38.796 55.728 38.88 55.752 ;
    END
  END i[76]
  PIN i[77]
    DIRECTION INPUT ;
    USE SIGNAL ;
    PORT
      LAYER M4 ;
        RECT  38.796 55.824 38.88 55.848 ;
    END
  END i[77]
  PIN i[78]
    DIRECTION INPUT ;
    USE SIGNAL ;
    PORT
      LAYER M4 ;
        RECT  38.796 55.92 38.88 55.944 ;
    END
  END i[78]
  PIN i[79]
    DIRECTION INPUT ;
    USE SIGNAL ;
    PORT
      LAYER M4 ;
        RECT  38.796 56.016 38.88 56.04 ;
    END
  END i[79]
  PIN i[7]
    DIRECTION INPUT ;
    USE SIGNAL ;
    PORT
      LAYER M4 ;
        RECT  38.796 32.976 38.88 33 ;
    END
  END i[7]
  PIN i[80]
    DIRECTION INPUT ;
    USE SIGNAL ;
    PORT
      LAYER M4 ;
        RECT  38.796 56.112 38.88 56.136 ;
    END
  END i[80]
  PIN i[81]
    DIRECTION INPUT ;
    USE SIGNAL ;
    PORT
      LAYER M4 ;
        RECT  38.796 56.208 38.88 56.232 ;
    END
  END i[81]
  PIN i[82]
    DIRECTION INPUT ;
    USE SIGNAL ;
    PORT
      LAYER M4 ;
        RECT  38.796 56.304 38.88 56.328 ;
    END
  END i[82]
  PIN i[83]
    DIRECTION INPUT ;
    USE SIGNAL ;
    PORT
      LAYER M4 ;
        RECT  38.796 56.4 38.88 56.424 ;
    END
  END i[83]
  PIN i[84]
    DIRECTION INPUT ;
    USE SIGNAL ;
    PORT
      LAYER M4 ;
        RECT  38.796 56.496 38.88 56.52 ;
    END
  END i[84]
  PIN i[85]
    DIRECTION INPUT ;
    USE SIGNAL ;
    PORT
      LAYER M4 ;
        RECT  38.796 56.592 38.88 56.616 ;
    END
  END i[85]
  PIN i[86]
    DIRECTION INPUT ;
    USE SIGNAL ;
    PORT
      LAYER M4 ;
        RECT  38.796 56.688 38.88 56.712 ;
    END
  END i[86]
  PIN i[87]
    DIRECTION INPUT ;
    USE SIGNAL ;
    PORT
      LAYER M4 ;
        RECT  38.796 56.784 38.88 56.808 ;
    END
  END i[87]
  PIN i[88]
    DIRECTION INPUT ;
    USE SIGNAL ;
    PORT
      LAYER M4 ;
        RECT  38.796 56.88 38.88 56.904 ;
    END
  END i[88]
  PIN i[89]
    DIRECTION INPUT ;
    USE SIGNAL ;
    PORT
      LAYER M4 ;
        RECT  38.796 56.976 38.88 57 ;
    END
  END i[89]
  PIN i[8]
    DIRECTION INPUT ;
    USE SIGNAL ;
    PORT
      LAYER M4 ;
        RECT  38.796 33.072 38.88 33.096 ;
    END
  END i[8]
  PIN i[90]
    DIRECTION INPUT ;
    USE SIGNAL ;
    PORT
      LAYER M4 ;
        RECT  38.796 57.072 38.88 57.096 ;
    END
  END i[90]
  PIN i[91]
    DIRECTION INPUT ;
    USE SIGNAL ;
    PORT
      LAYER M4 ;
        RECT  38.796 57.168 38.88 57.192 ;
    END
  END i[91]
  PIN i[92]
    DIRECTION INPUT ;
    USE SIGNAL ;
    PORT
      LAYER M4 ;
        RECT  38.796 57.264 38.88 57.288 ;
    END
  END i[92]
  PIN i[93]
    DIRECTION INPUT ;
    USE SIGNAL ;
    PORT
      LAYER M4 ;
        RECT  38.796 57.36 38.88 57.384 ;
    END
  END i[93]
  PIN i[94]
    DIRECTION INPUT ;
    USE SIGNAL ;
    PORT
      LAYER M4 ;
        RECT  38.796 57.456 38.88 57.48 ;
    END
  END i[94]
  PIN i[95]
    DIRECTION INPUT ;
    USE SIGNAL ;
    PORT
      LAYER M4 ;
        RECT  38.796 70.608 38.88 70.632 ;
    END
  END i[95]
  PIN i[96]
    DIRECTION INPUT ;
    USE SIGNAL ;
    PORT
      LAYER M4 ;
        RECT  38.796 70.704 38.88 70.728 ;
    END
  END i[96]
  PIN i[97]
    DIRECTION INPUT ;
    USE SIGNAL ;
    PORT
      LAYER M4 ;
        RECT  38.796 70.8 38.88 70.824 ;
    END
  END i[97]
  PIN i[98]
    DIRECTION INPUT ;
    USE SIGNAL ;
    PORT
      LAYER M4 ;
        RECT  38.796 70.896 38.88 70.92 ;
    END
  END i[98]
  PIN i[99]
    DIRECTION INPUT ;
    USE SIGNAL ;
    PORT
      LAYER M4 ;
        RECT  38.796 70.992 38.88 71.016 ;
    END
  END i[99]
  PIN i[9]
    DIRECTION INPUT ;
    USE SIGNAL ;
    PORT
      LAYER M4 ;
        RECT  38.796 33.168 38.88 33.192 ;
    END
  END i[9]
  PIN k[0]
    DIRECTION INPUT ;
    USE SIGNAL ;
    PORT
      LAYER M3 ;
        RECT  16.164 95.003 16.182 95.04 ;
    END
  END k[0]
  PIN k[1]
    DIRECTION INPUT ;
    USE SIGNAL ;
    PORT
      LAYER M3 ;
        RECT  16.236 95.003 16.254 95.04 ;
    END
  END k[1]
  PIN k[2]
    DIRECTION INPUT ;
    USE SIGNAL ;
    PORT
      LAYER M3 ;
        RECT  16.308 95.003 16.326 95.04 ;
    END
  END k[2]
  PIN o[0]
    DIRECTION OUTPUT ;
    USE SIGNAL ;
    PORT
      LAYER M4 ;
        RECT  0 30.768 0.084 30.792 ;
    END
  END o[0]
  PIN o[100]
    DIRECTION OUTPUT ;
    USE SIGNAL ;
    PORT
      LAYER M4 ;
        RECT  0 69.552 0.084 69.576 ;
    END
  END o[100]
  PIN o[101]
    DIRECTION OUTPUT ;
    USE SIGNAL ;
    PORT
      LAYER M4 ;
        RECT  0 69.648 0.084 69.672 ;
    END
  END o[101]
  PIN o[102]
    DIRECTION OUTPUT ;
    USE SIGNAL ;
    PORT
      LAYER M4 ;
        RECT  0 69.744 0.084 69.768 ;
    END
  END o[102]
  PIN o[103]
    DIRECTION OUTPUT ;
    USE SIGNAL ;
    PORT
      LAYER M4 ;
        RECT  0 69.84 0.084 69.864 ;
    END
  END o[103]
  PIN o[104]
    DIRECTION OUTPUT ;
    USE SIGNAL ;
    PORT
      LAYER M4 ;
        RECT  0 69.936 0.084 69.96 ;
    END
  END o[104]
  PIN o[105]
    DIRECTION OUTPUT ;
    USE SIGNAL ;
    PORT
      LAYER M4 ;
        RECT  0 70.032 0.084 70.056 ;
    END
  END o[105]
  PIN o[106]
    DIRECTION OUTPUT ;
    USE SIGNAL ;
    PORT
      LAYER M4 ;
        RECT  0 70.128 0.084 70.152 ;
    END
  END o[106]
  PIN o[107]
    DIRECTION OUTPUT ;
    USE SIGNAL ;
    PORT
      LAYER M4 ;
        RECT  0 70.224 0.084 70.248 ;
    END
  END o[107]
  PIN o[108]
    DIRECTION OUTPUT ;
    USE SIGNAL ;
    PORT
      LAYER M4 ;
        RECT  0 70.32 0.084 70.344 ;
    END
  END o[108]
  PIN o[109]
    DIRECTION OUTPUT ;
    USE SIGNAL ;
    PORT
      LAYER M4 ;
        RECT  0 70.416 0.084 70.44 ;
    END
  END o[109]
  PIN o[10]
    DIRECTION OUTPUT ;
    USE SIGNAL ;
    PORT
      LAYER M4 ;
        RECT  0 31.728 0.084 31.752 ;
    END
  END o[10]
  PIN o[110]
    DIRECTION OUTPUT ;
    USE SIGNAL ;
    PORT
      LAYER M4 ;
        RECT  0 70.512 0.084 70.536 ;
    END
  END o[110]
  PIN o[111]
    DIRECTION OUTPUT ;
    USE SIGNAL ;
    PORT
      LAYER M4 ;
        RECT  0 70.608 0.084 70.632 ;
    END
  END o[111]
  PIN o[112]
    DIRECTION OUTPUT ;
    USE SIGNAL ;
    PORT
      LAYER M4 ;
        RECT  0 70.704 0.084 70.728 ;
    END
  END o[112]
  PIN o[113]
    DIRECTION OUTPUT ;
    USE SIGNAL ;
    PORT
      LAYER M4 ;
        RECT  0 70.8 0.084 70.824 ;
    END
  END o[113]
  PIN o[114]
    DIRECTION OUTPUT ;
    USE SIGNAL ;
    PORT
      LAYER M4 ;
        RECT  0 70.896 0.084 70.92 ;
    END
  END o[114]
  PIN o[115]
    DIRECTION OUTPUT ;
    USE SIGNAL ;
    PORT
      LAYER M4 ;
        RECT  0 70.992 0.084 71.016 ;
    END
  END o[115]
  PIN o[116]
    DIRECTION OUTPUT ;
    USE SIGNAL ;
    PORT
      LAYER M4 ;
        RECT  0 71.088 0.084 71.112 ;
    END
  END o[116]
  PIN o[117]
    DIRECTION OUTPUT ;
    USE SIGNAL ;
    PORT
      LAYER M4 ;
        RECT  0 71.184 0.084 71.208 ;
    END
  END o[117]
  PIN o[118]
    DIRECTION OUTPUT ;
    USE SIGNAL ;
    PORT
      LAYER M4 ;
        RECT  0 71.28 0.084 71.304 ;
    END
  END o[118]
  PIN o[119]
    DIRECTION OUTPUT ;
    USE SIGNAL ;
    PORT
      LAYER M4 ;
        RECT  0 71.376 0.084 71.4 ;
    END
  END o[119]
  PIN o[11]
    DIRECTION OUTPUT ;
    USE SIGNAL ;
    PORT
      LAYER M4 ;
        RECT  0 31.824 0.084 31.848 ;
    END
  END o[11]
  PIN o[120]
    DIRECTION OUTPUT ;
    USE SIGNAL ;
    PORT
      LAYER M4 ;
        RECT  0 71.472 0.084 71.496 ;
    END
  END o[120]
  PIN o[121]
    DIRECTION OUTPUT ;
    USE SIGNAL ;
    PORT
      LAYER M4 ;
        RECT  0 71.568 0.084 71.592 ;
    END
  END o[121]
  PIN o[122]
    DIRECTION OUTPUT ;
    USE SIGNAL ;
    PORT
      LAYER M4 ;
        RECT  0 71.664 0.084 71.688 ;
    END
  END o[122]
  PIN o[123]
    DIRECTION OUTPUT ;
    USE SIGNAL ;
    PORT
      LAYER M4 ;
        RECT  0 71.76 0.084 71.784 ;
    END
  END o[123]
  PIN o[124]
    DIRECTION OUTPUT ;
    USE SIGNAL ;
    PORT
      LAYER M4 ;
        RECT  0 71.856 0.084 71.88 ;
    END
  END o[124]
  PIN o[125]
    DIRECTION OUTPUT ;
    USE SIGNAL ;
    PORT
      LAYER M4 ;
        RECT  0 71.952 0.084 71.976 ;
    END
  END o[125]
  PIN o[126]
    DIRECTION OUTPUT ;
    USE SIGNAL ;
    PORT
      LAYER M4 ;
        RECT  0 78.96 0.084 78.984 ;
    END
  END o[126]
  PIN o[127]
    DIRECTION OUTPUT ;
    USE SIGNAL ;
    PORT
      LAYER M4 ;
        RECT  0 79.056 0.084 79.08 ;
    END
  END o[127]
  PIN o[128]
    DIRECTION OUTPUT ;
    USE SIGNAL ;
    PORT
      LAYER M4 ;
        RECT  0 79.152 0.084 79.176 ;
    END
  END o[128]
  PIN o[129]
    DIRECTION OUTPUT ;
    USE SIGNAL ;
    PORT
      LAYER M4 ;
        RECT  0 79.248 0.084 79.272 ;
    END
  END o[129]
  PIN o[12]
    DIRECTION OUTPUT ;
    USE SIGNAL ;
    PORT
      LAYER M4 ;
        RECT  0 31.92 0.084 31.944 ;
    END
  END o[12]
  PIN o[130]
    DIRECTION OUTPUT ;
    USE SIGNAL ;
    PORT
      LAYER M4 ;
        RECT  0 79.344 0.084 79.368 ;
    END
  END o[130]
  PIN o[131]
    DIRECTION OUTPUT ;
    USE SIGNAL ;
    PORT
      LAYER M4 ;
        RECT  0 79.44 0.084 79.464 ;
    END
  END o[131]
  PIN o[132]
    DIRECTION OUTPUT ;
    USE SIGNAL ;
    PORT
      LAYER M4 ;
        RECT  0 79.536 0.084 79.56 ;
    END
  END o[132]
  PIN o[133]
    DIRECTION OUTPUT ;
    USE SIGNAL ;
    PORT
      LAYER M4 ;
        RECT  0 79.632 0.084 79.656 ;
    END
  END o[133]
  PIN o[134]
    DIRECTION OUTPUT ;
    USE SIGNAL ;
    PORT
      LAYER M4 ;
        RECT  0 79.728 0.084 79.752 ;
    END
  END o[134]
  PIN o[135]
    DIRECTION OUTPUT ;
    USE SIGNAL ;
    PORT
      LAYER M4 ;
        RECT  0 79.824 0.084 79.848 ;
    END
  END o[135]
  PIN o[136]
    DIRECTION OUTPUT ;
    USE SIGNAL ;
    PORT
      LAYER M4 ;
        RECT  0 79.92 0.084 79.944 ;
    END
  END o[136]
  PIN o[137]
    DIRECTION OUTPUT ;
    USE SIGNAL ;
    PORT
      LAYER M4 ;
        RECT  0 80.016 0.084 80.04 ;
    END
  END o[137]
  PIN o[138]
    DIRECTION OUTPUT ;
    USE SIGNAL ;
    PORT
      LAYER M4 ;
        RECT  0 80.112 0.084 80.136 ;
    END
  END o[138]
  PIN o[139]
    DIRECTION OUTPUT ;
    USE SIGNAL ;
    PORT
      LAYER M4 ;
        RECT  0 80.208 0.084 80.232 ;
    END
  END o[139]
  PIN o[13]
    DIRECTION OUTPUT ;
    USE SIGNAL ;
    PORT
      LAYER M4 ;
        RECT  0 32.016 0.084 32.04 ;
    END
  END o[13]
  PIN o[140]
    DIRECTION OUTPUT ;
    USE SIGNAL ;
    PORT
      LAYER M4 ;
        RECT  0 80.304 0.084 80.328 ;
    END
  END o[140]
  PIN o[141]
    DIRECTION OUTPUT ;
    USE SIGNAL ;
    PORT
      LAYER M4 ;
        RECT  0 80.4 0.084 80.424 ;
    END
  END o[141]
  PIN o[142]
    DIRECTION OUTPUT ;
    USE SIGNAL ;
    PORT
      LAYER M4 ;
        RECT  0 80.496 0.084 80.52 ;
    END
  END o[142]
  PIN o[143]
    DIRECTION OUTPUT ;
    USE SIGNAL ;
    PORT
      LAYER M4 ;
        RECT  0 80.592 0.084 80.616 ;
    END
  END o[143]
  PIN o[144]
    DIRECTION OUTPUT ;
    USE SIGNAL ;
    PORT
      LAYER M4 ;
        RECT  0 80.688 0.084 80.712 ;
    END
  END o[144]
  PIN o[145]
    DIRECTION OUTPUT ;
    USE SIGNAL ;
    PORT
      LAYER M4 ;
        RECT  0 80.784 0.084 80.808 ;
    END
  END o[145]
  PIN o[146]
    DIRECTION OUTPUT ;
    USE SIGNAL ;
    PORT
      LAYER M4 ;
        RECT  0 80.88 0.084 80.904 ;
    END
  END o[146]
  PIN o[147]
    DIRECTION OUTPUT ;
    USE SIGNAL ;
    PORT
      LAYER M4 ;
        RECT  0 80.976 0.084 81 ;
    END
  END o[147]
  PIN o[148]
    DIRECTION OUTPUT ;
    USE SIGNAL ;
    PORT
      LAYER M4 ;
        RECT  0 81.072 0.084 81.096 ;
    END
  END o[148]
  PIN o[149]
    DIRECTION OUTPUT ;
    USE SIGNAL ;
    PORT
      LAYER M4 ;
        RECT  0 81.168 0.084 81.192 ;
    END
  END o[149]
  PIN o[14]
    DIRECTION OUTPUT ;
    USE SIGNAL ;
    PORT
      LAYER M4 ;
        RECT  0 32.112 0.084 32.136 ;
    END
  END o[14]
  PIN o[150]
    DIRECTION OUTPUT ;
    USE SIGNAL ;
    PORT
      LAYER M4 ;
        RECT  0 81.264 0.084 81.288 ;
    END
  END o[150]
  PIN o[151]
    DIRECTION OUTPUT ;
    USE SIGNAL ;
    PORT
      LAYER M4 ;
        RECT  0 81.36 0.084 81.384 ;
    END
  END o[151]
  PIN o[152]
    DIRECTION OUTPUT ;
    USE SIGNAL ;
    PORT
      LAYER M4 ;
        RECT  0 81.456 0.084 81.48 ;
    END
  END o[152]
  PIN o[153]
    DIRECTION OUTPUT ;
    USE SIGNAL ;
    PORT
      LAYER M4 ;
        RECT  0 81.552 0.084 81.576 ;
    END
  END o[153]
  PIN o[154]
    DIRECTION OUTPUT ;
    USE SIGNAL ;
    PORT
      LAYER M4 ;
        RECT  0 81.648 0.084 81.672 ;
    END
  END o[154]
  PIN o[155]
    DIRECTION OUTPUT ;
    USE SIGNAL ;
    PORT
      LAYER M4 ;
        RECT  0 81.744 0.084 81.768 ;
    END
  END o[155]
  PIN o[156]
    DIRECTION OUTPUT ;
    USE SIGNAL ;
    PORT
      LAYER M4 ;
        RECT  0 81.84 0.084 81.864 ;
    END
  END o[156]
  PIN o[157]
    DIRECTION OUTPUT ;
    USE SIGNAL ;
    PORT
      LAYER M4 ;
        RECT  0 81.936 0.084 81.96 ;
    END
  END o[157]
  PIN o[158]
    DIRECTION OUTPUT ;
    USE SIGNAL ;
    PORT
      LAYER M4 ;
        RECT  0 82.032 0.084 82.056 ;
    END
  END o[158]
  PIN o[159]
    DIRECTION OUTPUT ;
    USE SIGNAL ;
    PORT
      LAYER M4 ;
        RECT  0 82.128 0.084 82.152 ;
    END
  END o[159]
  PIN o[15]
    DIRECTION OUTPUT ;
    USE SIGNAL ;
    PORT
      LAYER M4 ;
        RECT  0 32.208 0.084 32.232 ;
    END
  END o[15]
  PIN o[160]
    DIRECTION OUTPUT ;
    USE SIGNAL ;
    PORT
      LAYER M4 ;
        RECT  0 82.224 0.084 82.248 ;
    END
  END o[160]
  PIN o[161]
    DIRECTION OUTPUT ;
    USE SIGNAL ;
    PORT
      LAYER M4 ;
        RECT  0 82.32 0.084 82.344 ;
    END
  END o[161]
  PIN o[162]
    DIRECTION OUTPUT ;
    USE SIGNAL ;
    PORT
      LAYER M4 ;
        RECT  0 82.416 0.084 82.44 ;
    END
  END o[162]
  PIN o[163]
    DIRECTION OUTPUT ;
    USE SIGNAL ;
    PORT
      LAYER M4 ;
        RECT  0 82.512 0.084 82.536 ;
    END
  END o[163]
  PIN o[164]
    DIRECTION OUTPUT ;
    USE SIGNAL ;
    PORT
      LAYER M4 ;
        RECT  0 82.608 0.084 82.632 ;
    END
  END o[164]
  PIN o[165]
    DIRECTION OUTPUT ;
    USE SIGNAL ;
    PORT
      LAYER M4 ;
        RECT  0 82.704 0.084 82.728 ;
    END
  END o[165]
  PIN o[166]
    DIRECTION OUTPUT ;
    USE SIGNAL ;
    PORT
      LAYER M4 ;
        RECT  0 82.8 0.084 82.824 ;
    END
  END o[166]
  PIN o[167]
    DIRECTION OUTPUT ;
    USE SIGNAL ;
    PORT
      LAYER M4 ;
        RECT  0 82.896 0.084 82.92 ;
    END
  END o[167]
  PIN o[168]
    DIRECTION OUTPUT ;
    USE SIGNAL ;
    PORT
      LAYER M4 ;
        RECT  0 82.992 0.084 83.016 ;
    END
  END o[168]
  PIN o[169]
    DIRECTION OUTPUT ;
    USE SIGNAL ;
    PORT
      LAYER M4 ;
        RECT  0 83.088 0.084 83.112 ;
    END
  END o[169]
  PIN o[16]
    DIRECTION OUTPUT ;
    USE SIGNAL ;
    PORT
      LAYER M4 ;
        RECT  0 32.304 0.084 32.328 ;
    END
  END o[16]
  PIN o[170]
    DIRECTION OUTPUT ;
    USE SIGNAL ;
    PORT
      LAYER M4 ;
        RECT  0 83.184 0.084 83.208 ;
    END
  END o[170]
  PIN o[171]
    DIRECTION OUTPUT ;
    USE SIGNAL ;
    PORT
      LAYER M4 ;
        RECT  0 83.28 0.084 83.304 ;
    END
  END o[171]
  PIN o[172]
    DIRECTION OUTPUT ;
    USE SIGNAL ;
    PORT
      LAYER M4 ;
        RECT  0 83.376 0.084 83.4 ;
    END
  END o[172]
  PIN o[173]
    DIRECTION OUTPUT ;
    USE SIGNAL ;
    PORT
      LAYER M4 ;
        RECT  0 83.472 0.084 83.496 ;
    END
  END o[173]
  PIN o[174]
    DIRECTION OUTPUT ;
    USE SIGNAL ;
    PORT
      LAYER M4 ;
        RECT  0 83.568 0.084 83.592 ;
    END
  END o[174]
  PIN o[175]
    DIRECTION OUTPUT ;
    USE SIGNAL ;
    PORT
      LAYER M4 ;
        RECT  0 83.664 0.084 83.688 ;
    END
  END o[175]
  PIN o[176]
    DIRECTION OUTPUT ;
    USE SIGNAL ;
    PORT
      LAYER M4 ;
        RECT  0 83.76 0.084 83.784 ;
    END
  END o[176]
  PIN o[177]
    DIRECTION OUTPUT ;
    USE SIGNAL ;
    PORT
      LAYER M4 ;
        RECT  0 83.856 0.084 83.88 ;
    END
  END o[177]
  PIN o[178]
    DIRECTION OUTPUT ;
    USE SIGNAL ;
    PORT
      LAYER M4 ;
        RECT  0 83.952 0.084 83.976 ;
    END
  END o[178]
  PIN o[179]
    DIRECTION OUTPUT ;
    USE SIGNAL ;
    PORT
      LAYER M4 ;
        RECT  0 84.048 0.084 84.072 ;
    END
  END o[179]
  PIN o[17]
    DIRECTION OUTPUT ;
    USE SIGNAL ;
    PORT
      LAYER M4 ;
        RECT  0 32.4 0.084 32.424 ;
    END
  END o[17]
  PIN o[180]
    DIRECTION OUTPUT ;
    USE SIGNAL ;
    PORT
      LAYER M4 ;
        RECT  0 84.144 0.084 84.168 ;
    END
  END o[180]
  PIN o[181]
    DIRECTION OUTPUT ;
    USE SIGNAL ;
    PORT
      LAYER M4 ;
        RECT  0 84.24 0.084 84.264 ;
    END
  END o[181]
  PIN o[182]
    DIRECTION OUTPUT ;
    USE SIGNAL ;
    PORT
      LAYER M4 ;
        RECT  0 84.336 0.084 84.36 ;
    END
  END o[182]
  PIN o[183]
    DIRECTION OUTPUT ;
    USE SIGNAL ;
    PORT
      LAYER M4 ;
        RECT  0 84.432 0.084 84.456 ;
    END
  END o[183]
  PIN o[184]
    DIRECTION OUTPUT ;
    USE SIGNAL ;
    PORT
      LAYER M4 ;
        RECT  0 84.528 0.084 84.552 ;
    END
  END o[184]
  PIN o[185]
    DIRECTION OUTPUT ;
    USE SIGNAL ;
    PORT
      LAYER M4 ;
        RECT  0 84.624 0.084 84.648 ;
    END
  END o[185]
  PIN o[186]
    DIRECTION OUTPUT ;
    USE SIGNAL ;
    PORT
      LAYER M4 ;
        RECT  0 84.72 0.084 84.744 ;
    END
  END o[186]
  PIN o[187]
    DIRECTION OUTPUT ;
    USE SIGNAL ;
    PORT
      LAYER M4 ;
        RECT  0 84.816 0.084 84.84 ;
    END
  END o[187]
  PIN o[188]
    DIRECTION OUTPUT ;
    USE SIGNAL ;
    PORT
      LAYER M4 ;
        RECT  0 84.912 0.084 84.936 ;
    END
  END o[188]
  PIN o[189]
    DIRECTION OUTPUT ;
    USE SIGNAL ;
    PORT
      LAYER M4 ;
        RECT  0 85.008 0.084 85.032 ;
    END
  END o[189]
  PIN o[18]
    DIRECTION OUTPUT ;
    USE SIGNAL ;
    PORT
      LAYER M4 ;
        RECT  0 32.496 0.084 32.52 ;
    END
  END o[18]
  PIN o[190]
    DIRECTION OUTPUT ;
    USE SIGNAL ;
    PORT
      LAYER M4 ;
        RECT  0 85.104 0.084 85.128 ;
    END
  END o[190]
  PIN o[191]
    DIRECTION OUTPUT ;
    USE SIGNAL ;
    PORT
      LAYER M4 ;
        RECT  0 85.2 0.084 85.224 ;
    END
  END o[191]
  PIN o[192]
    DIRECTION OUTPUT ;
    USE SIGNAL ;
    PORT
      LAYER M4 ;
        RECT  0 85.296 0.084 85.32 ;
    END
  END o[192]
  PIN o[193]
    DIRECTION OUTPUT ;
    USE SIGNAL ;
    PORT
      LAYER M4 ;
        RECT  0 85.392 0.084 85.416 ;
    END
  END o[193]
  PIN o[194]
    DIRECTION OUTPUT ;
    USE SIGNAL ;
    PORT
      LAYER M4 ;
        RECT  0 85.488 0.084 85.512 ;
    END
  END o[194]
  PIN o[195]
    DIRECTION OUTPUT ;
    USE SIGNAL ;
    PORT
      LAYER M4 ;
        RECT  0 85.584 0.084 85.608 ;
    END
  END o[195]
  PIN o[196]
    DIRECTION OUTPUT ;
    USE SIGNAL ;
    PORT
      LAYER M4 ;
        RECT  0 85.68 0.084 85.704 ;
    END
  END o[196]
  PIN o[197]
    DIRECTION OUTPUT ;
    USE SIGNAL ;
    PORT
      LAYER M4 ;
        RECT  0 85.776 0.084 85.8 ;
    END
  END o[197]
  PIN o[198]
    DIRECTION OUTPUT ;
    USE SIGNAL ;
    PORT
      LAYER M4 ;
        RECT  0 85.872 0.084 85.896 ;
    END
  END o[198]
  PIN o[199]
    DIRECTION OUTPUT ;
    USE SIGNAL ;
    PORT
      LAYER M4 ;
        RECT  0 85.968 0.084 85.992 ;
    END
  END o[199]
  PIN o[19]
    DIRECTION OUTPUT ;
    USE SIGNAL ;
    PORT
      LAYER M4 ;
        RECT  0 32.592 0.084 32.616 ;
    END
  END o[19]
  PIN o[1]
    DIRECTION OUTPUT ;
    USE SIGNAL ;
    PORT
      LAYER M4 ;
        RECT  0 30.864 0.084 30.888 ;
    END
  END o[1]
  PIN o[200]
    DIRECTION OUTPUT ;
    USE SIGNAL ;
    PORT
      LAYER M4 ;
        RECT  0 86.064 0.084 86.088 ;
    END
  END o[200]
  PIN o[201]
    DIRECTION OUTPUT ;
    USE SIGNAL ;
    PORT
      LAYER M4 ;
        RECT  0 86.16 0.084 86.184 ;
    END
  END o[201]
  PIN o[202]
    DIRECTION OUTPUT ;
    USE SIGNAL ;
    PORT
      LAYER M4 ;
        RECT  0 86.256 0.084 86.28 ;
    END
  END o[202]
  PIN o[203]
    DIRECTION OUTPUT ;
    USE SIGNAL ;
    PORT
      LAYER M4 ;
        RECT  0 86.352 0.084 86.376 ;
    END
  END o[203]
  PIN o[204]
    DIRECTION OUTPUT ;
    USE SIGNAL ;
    PORT
      LAYER M4 ;
        RECT  0 86.448 0.084 86.472 ;
    END
  END o[204]
  PIN o[205]
    DIRECTION OUTPUT ;
    USE SIGNAL ;
    PORT
      LAYER M4 ;
        RECT  0 86.544 0.084 86.568 ;
    END
  END o[205]
  PIN o[206]
    DIRECTION OUTPUT ;
    USE SIGNAL ;
    PORT
      LAYER M4 ;
        RECT  0 86.64 0.084 86.664 ;
    END
  END o[206]
  PIN o[207]
    DIRECTION OUTPUT ;
    USE SIGNAL ;
    PORT
      LAYER M4 ;
        RECT  0 86.736 0.084 86.76 ;
    END
  END o[207]
  PIN o[208]
    DIRECTION OUTPUT ;
    USE SIGNAL ;
    PORT
      LAYER M4 ;
        RECT  0 86.832 0.084 86.856 ;
    END
  END o[208]
  PIN o[209]
    DIRECTION OUTPUT ;
    USE SIGNAL ;
    PORT
      LAYER M4 ;
        RECT  0 86.928 0.084 86.952 ;
    END
  END o[209]
  PIN o[20]
    DIRECTION OUTPUT ;
    USE SIGNAL ;
    PORT
      LAYER M4 ;
        RECT  0 32.688 0.084 32.712 ;
    END
  END o[20]
  PIN o[210]
    DIRECTION OUTPUT ;
    USE SIGNAL ;
    PORT
      LAYER M4 ;
        RECT  0 87.024 0.084 87.048 ;
    END
  END o[210]
  PIN o[211]
    DIRECTION OUTPUT ;
    USE SIGNAL ;
    PORT
      LAYER M4 ;
        RECT  0 87.12 0.084 87.144 ;
    END
  END o[211]
  PIN o[212]
    DIRECTION OUTPUT ;
    USE SIGNAL ;
    PORT
      LAYER M4 ;
        RECT  0 87.216 0.084 87.24 ;
    END
  END o[212]
  PIN o[213]
    DIRECTION OUTPUT ;
    USE SIGNAL ;
    PORT
      LAYER M4 ;
        RECT  0 87.312 0.084 87.336 ;
    END
  END o[213]
  PIN o[214]
    DIRECTION OUTPUT ;
    USE SIGNAL ;
    PORT
      LAYER M4 ;
        RECT  0 87.408 0.084 87.432 ;
    END
  END o[214]
  PIN o[215]
    DIRECTION OUTPUT ;
    USE SIGNAL ;
    PORT
      LAYER M4 ;
        RECT  0 87.504 0.084 87.528 ;
    END
  END o[215]
  PIN o[216]
    DIRECTION OUTPUT ;
    USE SIGNAL ;
    PORT
      LAYER M4 ;
        RECT  0 87.6 0.084 87.624 ;
    END
  END o[216]
  PIN o[217]
    DIRECTION OUTPUT ;
    USE SIGNAL ;
    PORT
      LAYER M4 ;
        RECT  0 87.696 0.084 87.72 ;
    END
  END o[217]
  PIN o[218]
    DIRECTION OUTPUT ;
    USE SIGNAL ;
    PORT
      LAYER M4 ;
        RECT  0 87.792 0.084 87.816 ;
    END
  END o[218]
  PIN o[219]
    DIRECTION OUTPUT ;
    USE SIGNAL ;
    PORT
      LAYER M4 ;
        RECT  0 87.888 0.084 87.912 ;
    END
  END o[219]
  PIN o[21]
    DIRECTION OUTPUT ;
    USE SIGNAL ;
    PORT
      LAYER M4 ;
        RECT  0 32.784 0.084 32.808 ;
    END
  END o[21]
  PIN o[220]
    DIRECTION OUTPUT ;
    USE SIGNAL ;
    PORT
      LAYER M4 ;
        RECT  0 87.984 0.084 88.008 ;
    END
  END o[220]
  PIN o[221]
    DIRECTION OUTPUT ;
    USE SIGNAL ;
    PORT
      LAYER M4 ;
        RECT  0 88.08 0.084 88.104 ;
    END
  END o[221]
  PIN o[222]
    DIRECTION OUTPUT ;
    USE SIGNAL ;
    PORT
      LAYER M4 ;
        RECT  0 72.048 0.084 72.072 ;
    END
  END o[222]
  PIN o[223]
    DIRECTION OUTPUT ;
    USE SIGNAL ;
    PORT
      LAYER M4 ;
        RECT  0 72.144 0.084 72.168 ;
    END
  END o[223]
  PIN o[224]
    DIRECTION OUTPUT ;
    USE SIGNAL ;
    PORT
      LAYER M4 ;
        RECT  0 72.24 0.084 72.264 ;
    END
  END o[224]
  PIN o[225]
    DIRECTION OUTPUT ;
    USE SIGNAL ;
    PORT
      LAYER M4 ;
        RECT  0 72.336 0.084 72.36 ;
    END
  END o[225]
  PIN o[226]
    DIRECTION OUTPUT ;
    USE SIGNAL ;
    PORT
      LAYER M4 ;
        RECT  0 72.432 0.084 72.456 ;
    END
  END o[226]
  PIN o[227]
    DIRECTION OUTPUT ;
    USE SIGNAL ;
    PORT
      LAYER M4 ;
        RECT  0 72.528 0.084 72.552 ;
    END
  END o[227]
  PIN o[228]
    DIRECTION OUTPUT ;
    USE SIGNAL ;
    PORT
      LAYER M4 ;
        RECT  0 72.624 0.084 72.648 ;
    END
  END o[228]
  PIN o[229]
    DIRECTION OUTPUT ;
    USE SIGNAL ;
    PORT
      LAYER M4 ;
        RECT  0 72.72 0.084 72.744 ;
    END
  END o[229]
  PIN o[22]
    DIRECTION OUTPUT ;
    USE SIGNAL ;
    PORT
      LAYER M4 ;
        RECT  0 32.88 0.084 32.904 ;
    END
  END o[22]
  PIN o[230]
    DIRECTION OUTPUT ;
    USE SIGNAL ;
    PORT
      LAYER M4 ;
        RECT  0 72.816 0.084 72.84 ;
    END
  END o[230]
  PIN o[231]
    DIRECTION OUTPUT ;
    USE SIGNAL ;
    PORT
      LAYER M4 ;
        RECT  0 72.912 0.084 72.936 ;
    END
  END o[231]
  PIN o[232]
    DIRECTION OUTPUT ;
    USE SIGNAL ;
    PORT
      LAYER M4 ;
        RECT  0 73.008 0.084 73.032 ;
    END
  END o[232]
  PIN o[233]
    DIRECTION OUTPUT ;
    USE SIGNAL ;
    PORT
      LAYER M4 ;
        RECT  0 73.104 0.084 73.128 ;
    END
  END o[233]
  PIN o[234]
    DIRECTION OUTPUT ;
    USE SIGNAL ;
    PORT
      LAYER M4 ;
        RECT  0 73.2 0.084 73.224 ;
    END
  END o[234]
  PIN o[235]
    DIRECTION OUTPUT ;
    USE SIGNAL ;
    PORT
      LAYER M4 ;
        RECT  0 73.296 0.084 73.32 ;
    END
  END o[235]
  PIN o[236]
    DIRECTION OUTPUT ;
    USE SIGNAL ;
    PORT
      LAYER M4 ;
        RECT  0 73.392 0.084 73.416 ;
    END
  END o[236]
  PIN o[237]
    DIRECTION OUTPUT ;
    USE SIGNAL ;
    PORT
      LAYER M4 ;
        RECT  0 73.488 0.084 73.512 ;
    END
  END o[237]
  PIN o[238]
    DIRECTION OUTPUT ;
    USE SIGNAL ;
    PORT
      LAYER M4 ;
        RECT  0 73.584 0.084 73.608 ;
    END
  END o[238]
  PIN o[239]
    DIRECTION OUTPUT ;
    USE SIGNAL ;
    PORT
      LAYER M4 ;
        RECT  0 73.68 0.084 73.704 ;
    END
  END o[239]
  PIN o[23]
    DIRECTION OUTPUT ;
    USE SIGNAL ;
    PORT
      LAYER M4 ;
        RECT  0 32.976 0.084 33 ;
    END
  END o[23]
  PIN o[240]
    DIRECTION OUTPUT ;
    USE SIGNAL ;
    PORT
      LAYER M4 ;
        RECT  0 73.776 0.084 73.8 ;
    END
  END o[240]
  PIN o[241]
    DIRECTION OUTPUT ;
    USE SIGNAL ;
    PORT
      LAYER M4 ;
        RECT  0 73.872 0.084 73.896 ;
    END
  END o[241]
  PIN o[242]
    DIRECTION OUTPUT ;
    USE SIGNAL ;
    PORT
      LAYER M4 ;
        RECT  0 73.968 0.084 73.992 ;
    END
  END o[242]
  PIN o[243]
    DIRECTION OUTPUT ;
    USE SIGNAL ;
    PORT
      LAYER M4 ;
        RECT  0 74.064 0.084 74.088 ;
    END
  END o[243]
  PIN o[244]
    DIRECTION OUTPUT ;
    USE SIGNAL ;
    PORT
      LAYER M4 ;
        RECT  0 74.16 0.084 74.184 ;
    END
  END o[244]
  PIN o[245]
    DIRECTION OUTPUT ;
    USE SIGNAL ;
    PORT
      LAYER M4 ;
        RECT  0 74.256 0.084 74.28 ;
    END
  END o[245]
  PIN o[246]
    DIRECTION OUTPUT ;
    USE SIGNAL ;
    PORT
      LAYER M4 ;
        RECT  0 74.352 0.084 74.376 ;
    END
  END o[246]
  PIN o[247]
    DIRECTION OUTPUT ;
    USE SIGNAL ;
    PORT
      LAYER M4 ;
        RECT  0 74.448 0.084 74.472 ;
    END
  END o[247]
  PIN o[248]
    DIRECTION OUTPUT ;
    USE SIGNAL ;
    PORT
      LAYER M4 ;
        RECT  0 74.544 0.084 74.568 ;
    END
  END o[248]
  PIN o[249]
    DIRECTION OUTPUT ;
    USE SIGNAL ;
    PORT
      LAYER M4 ;
        RECT  0 74.64 0.084 74.664 ;
    END
  END o[249]
  PIN o[24]
    DIRECTION OUTPUT ;
    USE SIGNAL ;
    PORT
      LAYER M4 ;
        RECT  0 33.072 0.084 33.096 ;
    END
  END o[24]
  PIN o[250]
    DIRECTION OUTPUT ;
    USE SIGNAL ;
    PORT
      LAYER M4 ;
        RECT  0 74.736 0.084 74.76 ;
    END
  END o[250]
  PIN o[251]
    DIRECTION OUTPUT ;
    USE SIGNAL ;
    PORT
      LAYER M4 ;
        RECT  0 74.832 0.084 74.856 ;
    END
  END o[251]
  PIN o[252]
    DIRECTION OUTPUT ;
    USE SIGNAL ;
    PORT
      LAYER M4 ;
        RECT  0 74.928 0.084 74.952 ;
    END
  END o[252]
  PIN o[253]
    DIRECTION OUTPUT ;
    USE SIGNAL ;
    PORT
      LAYER M4 ;
        RECT  0 75.024 0.084 75.048 ;
    END
  END o[253]
  PIN o[254]
    DIRECTION OUTPUT ;
    USE SIGNAL ;
    PORT
      LAYER M4 ;
        RECT  0 62.832 0.084 62.856 ;
    END
  END o[254]
  PIN o[255]
    DIRECTION OUTPUT ;
    USE SIGNAL ;
    PORT
      LAYER M4 ;
        RECT  0 62.928 0.084 62.952 ;
    END
  END o[255]
  PIN o[256]
    DIRECTION OUTPUT ;
    USE SIGNAL ;
    PORT
      LAYER M4 ;
        RECT  0 63.024 0.084 63.048 ;
    END
  END o[256]
  PIN o[257]
    DIRECTION OUTPUT ;
    USE SIGNAL ;
    PORT
      LAYER M4 ;
        RECT  0 63.12 0.084 63.144 ;
    END
  END o[257]
  PIN o[258]
    DIRECTION OUTPUT ;
    USE SIGNAL ;
    PORT
      LAYER M4 ;
        RECT  0 63.216 0.084 63.24 ;
    END
  END o[258]
  PIN o[259]
    DIRECTION OUTPUT ;
    USE SIGNAL ;
    PORT
      LAYER M4 ;
        RECT  0 63.312 0.084 63.336 ;
    END
  END o[259]
  PIN o[25]
    DIRECTION OUTPUT ;
    USE SIGNAL ;
    PORT
      LAYER M4 ;
        RECT  0 33.168 0.084 33.192 ;
    END
  END o[25]
  PIN o[260]
    DIRECTION OUTPUT ;
    USE SIGNAL ;
    PORT
      LAYER M4 ;
        RECT  0 63.408 0.084 63.432 ;
    END
  END o[260]
  PIN o[261]
    DIRECTION OUTPUT ;
    USE SIGNAL ;
    PORT
      LAYER M4 ;
        RECT  0 63.504 0.084 63.528 ;
    END
  END o[261]
  PIN o[262]
    DIRECTION OUTPUT ;
    USE SIGNAL ;
    PORT
      LAYER M4 ;
        RECT  0 63.6 0.084 63.624 ;
    END
  END o[262]
  PIN o[263]
    DIRECTION OUTPUT ;
    USE SIGNAL ;
    PORT
      LAYER M4 ;
        RECT  0 63.696 0.084 63.72 ;
    END
  END o[263]
  PIN o[264]
    DIRECTION OUTPUT ;
    USE SIGNAL ;
    PORT
      LAYER M4 ;
        RECT  0 63.792 0.084 63.816 ;
    END
  END o[264]
  PIN o[265]
    DIRECTION OUTPUT ;
    USE SIGNAL ;
    PORT
      LAYER M4 ;
        RECT  0 63.888 0.084 63.912 ;
    END
  END o[265]
  PIN o[266]
    DIRECTION OUTPUT ;
    USE SIGNAL ;
    PORT
      LAYER M4 ;
        RECT  0 63.984 0.084 64.008 ;
    END
  END o[266]
  PIN o[267]
    DIRECTION OUTPUT ;
    USE SIGNAL ;
    PORT
      LAYER M4 ;
        RECT  0 64.08 0.084 64.104 ;
    END
  END o[267]
  PIN o[268]
    DIRECTION OUTPUT ;
    USE SIGNAL ;
    PORT
      LAYER M4 ;
        RECT  0 64.176 0.084 64.2 ;
    END
  END o[268]
  PIN o[269]
    DIRECTION OUTPUT ;
    USE SIGNAL ;
    PORT
      LAYER M4 ;
        RECT  0 64.272 0.084 64.296 ;
    END
  END o[269]
  PIN o[26]
    DIRECTION OUTPUT ;
    USE SIGNAL ;
    PORT
      LAYER M4 ;
        RECT  0 33.264 0.084 33.288 ;
    END
  END o[26]
  PIN o[270]
    DIRECTION OUTPUT ;
    USE SIGNAL ;
    PORT
      LAYER M4 ;
        RECT  0 64.368 0.084 64.392 ;
    END
  END o[270]
  PIN o[271]
    DIRECTION OUTPUT ;
    USE SIGNAL ;
    PORT
      LAYER M4 ;
        RECT  0 64.464 0.084 64.488 ;
    END
  END o[271]
  PIN o[272]
    DIRECTION OUTPUT ;
    USE SIGNAL ;
    PORT
      LAYER M4 ;
        RECT  0 64.56 0.084 64.584 ;
    END
  END o[272]
  PIN o[273]
    DIRECTION OUTPUT ;
    USE SIGNAL ;
    PORT
      LAYER M4 ;
        RECT  0 64.656 0.084 64.68 ;
    END
  END o[273]
  PIN o[274]
    DIRECTION OUTPUT ;
    USE SIGNAL ;
    PORT
      LAYER M4 ;
        RECT  0 64.752 0.084 64.776 ;
    END
  END o[274]
  PIN o[275]
    DIRECTION OUTPUT ;
    USE SIGNAL ;
    PORT
      LAYER M4 ;
        RECT  0 64.848 0.084 64.872 ;
    END
  END o[275]
  PIN o[276]
    DIRECTION OUTPUT ;
    USE SIGNAL ;
    PORT
      LAYER M4 ;
        RECT  0 64.944 0.084 64.968 ;
    END
  END o[276]
  PIN o[277]
    DIRECTION OUTPUT ;
    USE SIGNAL ;
    PORT
      LAYER M4 ;
        RECT  0 65.04 0.084 65.064 ;
    END
  END o[277]
  PIN o[278]
    DIRECTION OUTPUT ;
    USE SIGNAL ;
    PORT
      LAYER M4 ;
        RECT  0 65.136 0.084 65.16 ;
    END
  END o[278]
  PIN o[279]
    DIRECTION OUTPUT ;
    USE SIGNAL ;
    PORT
      LAYER M4 ;
        RECT  0 65.232 0.084 65.256 ;
    END
  END o[279]
  PIN o[27]
    DIRECTION OUTPUT ;
    USE SIGNAL ;
    PORT
      LAYER M4 ;
        RECT  0 33.36 0.084 33.384 ;
    END
  END o[27]
  PIN o[280]
    DIRECTION OUTPUT ;
    USE SIGNAL ;
    PORT
      LAYER M4 ;
        RECT  0 65.328 0.084 65.352 ;
    END
  END o[280]
  PIN o[281]
    DIRECTION OUTPUT ;
    USE SIGNAL ;
    PORT
      LAYER M4 ;
        RECT  0 65.424 0.084 65.448 ;
    END
  END o[281]
  PIN o[282]
    DIRECTION OUTPUT ;
    USE SIGNAL ;
    PORT
      LAYER M4 ;
        RECT  0 65.52 0.084 65.544 ;
    END
  END o[282]
  PIN o[283]
    DIRECTION OUTPUT ;
    USE SIGNAL ;
    PORT
      LAYER M4 ;
        RECT  0 65.616 0.084 65.64 ;
    END
  END o[283]
  PIN o[284]
    DIRECTION OUTPUT ;
    USE SIGNAL ;
    PORT
      LAYER M4 ;
        RECT  0 65.712 0.084 65.736 ;
    END
  END o[284]
  PIN o[285]
    DIRECTION OUTPUT ;
    USE SIGNAL ;
    PORT
      LAYER M4 ;
        RECT  0 65.808 0.084 65.832 ;
    END
  END o[285]
  PIN o[286]
    DIRECTION OUTPUT ;
    USE SIGNAL ;
    PORT
      LAYER M4 ;
        RECT  0 46.704 0.084 46.728 ;
    END
  END o[286]
  PIN o[287]
    DIRECTION OUTPUT ;
    USE SIGNAL ;
    PORT
      LAYER M4 ;
        RECT  0 46.8 0.084 46.824 ;
    END
  END o[287]
  PIN o[288]
    DIRECTION OUTPUT ;
    USE SIGNAL ;
    PORT
      LAYER M4 ;
        RECT  0 46.896 0.084 46.92 ;
    END
  END o[288]
  PIN o[289]
    DIRECTION OUTPUT ;
    USE SIGNAL ;
    PORT
      LAYER M4 ;
        RECT  0 46.992 0.084 47.016 ;
    END
  END o[289]
  PIN o[28]
    DIRECTION OUTPUT ;
    USE SIGNAL ;
    PORT
      LAYER M4 ;
        RECT  0 33.456 0.084 33.48 ;
    END
  END o[28]
  PIN o[290]
    DIRECTION OUTPUT ;
    USE SIGNAL ;
    PORT
      LAYER M4 ;
        RECT  0 47.088 0.084 47.112 ;
    END
  END o[290]
  PIN o[291]
    DIRECTION OUTPUT ;
    USE SIGNAL ;
    PORT
      LAYER M4 ;
        RECT  0 47.184 0.084 47.208 ;
    END
  END o[291]
  PIN o[292]
    DIRECTION OUTPUT ;
    USE SIGNAL ;
    PORT
      LAYER M4 ;
        RECT  0 47.28 0.084 47.304 ;
    END
  END o[292]
  PIN o[293]
    DIRECTION OUTPUT ;
    USE SIGNAL ;
    PORT
      LAYER M4 ;
        RECT  0 47.376 0.084 47.4 ;
    END
  END o[293]
  PIN o[294]
    DIRECTION OUTPUT ;
    USE SIGNAL ;
    PORT
      LAYER M4 ;
        RECT  0 47.472 0.084 47.496 ;
    END
  END o[294]
  PIN o[295]
    DIRECTION OUTPUT ;
    USE SIGNAL ;
    PORT
      LAYER M4 ;
        RECT  0 47.568 0.084 47.592 ;
    END
  END o[295]
  PIN o[296]
    DIRECTION OUTPUT ;
    USE SIGNAL ;
    PORT
      LAYER M4 ;
        RECT  0 47.664 0.084 47.688 ;
    END
  END o[296]
  PIN o[297]
    DIRECTION OUTPUT ;
    USE SIGNAL ;
    PORT
      LAYER M4 ;
        RECT  0 47.76 0.084 47.784 ;
    END
  END o[297]
  PIN o[298]
    DIRECTION OUTPUT ;
    USE SIGNAL ;
    PORT
      LAYER M4 ;
        RECT  0 47.856 0.084 47.88 ;
    END
  END o[298]
  PIN o[299]
    DIRECTION OUTPUT ;
    USE SIGNAL ;
    PORT
      LAYER M4 ;
        RECT  0 47.952 0.084 47.976 ;
    END
  END o[299]
  PIN o[29]
    DIRECTION OUTPUT ;
    USE SIGNAL ;
    PORT
      LAYER M4 ;
        RECT  0 33.552 0.084 33.576 ;
    END
  END o[29]
  PIN o[2]
    DIRECTION OUTPUT ;
    USE SIGNAL ;
    PORT
      LAYER M4 ;
        RECT  0 30.96 0.084 30.984 ;
    END
  END o[2]
  PIN o[300]
    DIRECTION OUTPUT ;
    USE SIGNAL ;
    PORT
      LAYER M4 ;
        RECT  0 48.048 0.084 48.072 ;
    END
  END o[300]
  PIN o[301]
    DIRECTION OUTPUT ;
    USE SIGNAL ;
    PORT
      LAYER M4 ;
        RECT  0 48.144 0.084 48.168 ;
    END
  END o[301]
  PIN o[302]
    DIRECTION OUTPUT ;
    USE SIGNAL ;
    PORT
      LAYER M4 ;
        RECT  0 48.24 0.084 48.264 ;
    END
  END o[302]
  PIN o[303]
    DIRECTION OUTPUT ;
    USE SIGNAL ;
    PORT
      LAYER M4 ;
        RECT  0 48.336 0.084 48.36 ;
    END
  END o[303]
  PIN o[304]
    DIRECTION OUTPUT ;
    USE SIGNAL ;
    PORT
      LAYER M4 ;
        RECT  0 48.432 0.084 48.456 ;
    END
  END o[304]
  PIN o[305]
    DIRECTION OUTPUT ;
    USE SIGNAL ;
    PORT
      LAYER M4 ;
        RECT  0 48.528 0.084 48.552 ;
    END
  END o[305]
  PIN o[306]
    DIRECTION OUTPUT ;
    USE SIGNAL ;
    PORT
      LAYER M4 ;
        RECT  0 48.624 0.084 48.648 ;
    END
  END o[306]
  PIN o[307]
    DIRECTION OUTPUT ;
    USE SIGNAL ;
    PORT
      LAYER M4 ;
        RECT  0 48.72 0.084 48.744 ;
    END
  END o[307]
  PIN o[308]
    DIRECTION OUTPUT ;
    USE SIGNAL ;
    PORT
      LAYER M4 ;
        RECT  0 48.816 0.084 48.84 ;
    END
  END o[308]
  PIN o[309]
    DIRECTION OUTPUT ;
    USE SIGNAL ;
    PORT
      LAYER M4 ;
        RECT  0 48.912 0.084 48.936 ;
    END
  END o[309]
  PIN o[30]
    DIRECTION OUTPUT ;
    USE SIGNAL ;
    PORT
      LAYER M4 ;
        RECT  0 43.632 0.084 43.656 ;
    END
  END o[30]
  PIN o[310]
    DIRECTION OUTPUT ;
    USE SIGNAL ;
    PORT
      LAYER M4 ;
        RECT  0 49.008 0.084 49.032 ;
    END
  END o[310]
  PIN o[311]
    DIRECTION OUTPUT ;
    USE SIGNAL ;
    PORT
      LAYER M4 ;
        RECT  0 49.104 0.084 49.128 ;
    END
  END o[311]
  PIN o[312]
    DIRECTION OUTPUT ;
    USE SIGNAL ;
    PORT
      LAYER M4 ;
        RECT  0 49.2 0.084 49.224 ;
    END
  END o[312]
  PIN o[313]
    DIRECTION OUTPUT ;
    USE SIGNAL ;
    PORT
      LAYER M4 ;
        RECT  0 49.296 0.084 49.32 ;
    END
  END o[313]
  PIN o[314]
    DIRECTION OUTPUT ;
    USE SIGNAL ;
    PORT
      LAYER M4 ;
        RECT  0 49.392 0.084 49.416 ;
    END
  END o[314]
  PIN o[315]
    DIRECTION OUTPUT ;
    USE SIGNAL ;
    PORT
      LAYER M4 ;
        RECT  0 49.488 0.084 49.512 ;
    END
  END o[315]
  PIN o[316]
    DIRECTION OUTPUT ;
    USE SIGNAL ;
    PORT
      LAYER M4 ;
        RECT  0 49.584 0.084 49.608 ;
    END
  END o[316]
  PIN o[317]
    DIRECTION OUTPUT ;
    USE SIGNAL ;
    PORT
      LAYER M4 ;
        RECT  0 49.68 0.084 49.704 ;
    END
  END o[317]
  PIN o[318]
    DIRECTION OUTPUT ;
    USE SIGNAL ;
    PORT
      LAYER M4 ;
        RECT  0 49.776 0.084 49.8 ;
    END
  END o[318]
  PIN o[319]
    DIRECTION OUTPUT ;
    USE SIGNAL ;
    PORT
      LAYER M4 ;
        RECT  0 49.872 0.084 49.896 ;
    END
  END o[319]
  PIN o[31]
    DIRECTION OUTPUT ;
    USE SIGNAL ;
    PORT
      LAYER M4 ;
        RECT  0 43.728 0.084 43.752 ;
    END
  END o[31]
  PIN o[320]
    DIRECTION OUTPUT ;
    USE SIGNAL ;
    PORT
      LAYER M4 ;
        RECT  0 49.968 0.084 49.992 ;
    END
  END o[320]
  PIN o[321]
    DIRECTION OUTPUT ;
    USE SIGNAL ;
    PORT
      LAYER M4 ;
        RECT  0 50.064 0.084 50.088 ;
    END
  END o[321]
  PIN o[322]
    DIRECTION OUTPUT ;
    USE SIGNAL ;
    PORT
      LAYER M4 ;
        RECT  0 50.16 0.084 50.184 ;
    END
  END o[322]
  PIN o[323]
    DIRECTION OUTPUT ;
    USE SIGNAL ;
    PORT
      LAYER M4 ;
        RECT  0 50.256 0.084 50.28 ;
    END
  END o[323]
  PIN o[324]
    DIRECTION OUTPUT ;
    USE SIGNAL ;
    PORT
      LAYER M4 ;
        RECT  0 50.352 0.084 50.376 ;
    END
  END o[324]
  PIN o[325]
    DIRECTION OUTPUT ;
    USE SIGNAL ;
    PORT
      LAYER M4 ;
        RECT  0 50.448 0.084 50.472 ;
    END
  END o[325]
  PIN o[326]
    DIRECTION OUTPUT ;
    USE SIGNAL ;
    PORT
      LAYER M4 ;
        RECT  0 50.544 0.084 50.568 ;
    END
  END o[326]
  PIN o[327]
    DIRECTION OUTPUT ;
    USE SIGNAL ;
    PORT
      LAYER M4 ;
        RECT  0 50.64 0.084 50.664 ;
    END
  END o[327]
  PIN o[328]
    DIRECTION OUTPUT ;
    USE SIGNAL ;
    PORT
      LAYER M4 ;
        RECT  0 50.736 0.084 50.76 ;
    END
  END o[328]
  PIN o[329]
    DIRECTION OUTPUT ;
    USE SIGNAL ;
    PORT
      LAYER M4 ;
        RECT  0 50.832 0.084 50.856 ;
    END
  END o[329]
  PIN o[32]
    DIRECTION OUTPUT ;
    USE SIGNAL ;
    PORT
      LAYER M4 ;
        RECT  0 43.824 0.084 43.848 ;
    END
  END o[32]
  PIN o[330]
    DIRECTION OUTPUT ;
    USE SIGNAL ;
    PORT
      LAYER M4 ;
        RECT  0 50.928 0.084 50.952 ;
    END
  END o[330]
  PIN o[331]
    DIRECTION OUTPUT ;
    USE SIGNAL ;
    PORT
      LAYER M4 ;
        RECT  0 51.024 0.084 51.048 ;
    END
  END o[331]
  PIN o[332]
    DIRECTION OUTPUT ;
    USE SIGNAL ;
    PORT
      LAYER M4 ;
        RECT  0 51.12 0.084 51.144 ;
    END
  END o[332]
  PIN o[333]
    DIRECTION OUTPUT ;
    USE SIGNAL ;
    PORT
      LAYER M4 ;
        RECT  0 51.216 0.084 51.24 ;
    END
  END o[333]
  PIN o[334]
    DIRECTION OUTPUT ;
    USE SIGNAL ;
    PORT
      LAYER M4 ;
        RECT  0 51.312 0.084 51.336 ;
    END
  END o[334]
  PIN o[335]
    DIRECTION OUTPUT ;
    USE SIGNAL ;
    PORT
      LAYER M4 ;
        RECT  0 51.408 0.084 51.432 ;
    END
  END o[335]
  PIN o[336]
    DIRECTION OUTPUT ;
    USE SIGNAL ;
    PORT
      LAYER M4 ;
        RECT  0 51.504 0.084 51.528 ;
    END
  END o[336]
  PIN o[337]
    DIRECTION OUTPUT ;
    USE SIGNAL ;
    PORT
      LAYER M4 ;
        RECT  0 51.6 0.084 51.624 ;
    END
  END o[337]
  PIN o[338]
    DIRECTION OUTPUT ;
    USE SIGNAL ;
    PORT
      LAYER M4 ;
        RECT  0 51.696 0.084 51.72 ;
    END
  END o[338]
  PIN o[339]
    DIRECTION OUTPUT ;
    USE SIGNAL ;
    PORT
      LAYER M4 ;
        RECT  0 51.792 0.084 51.816 ;
    END
  END o[339]
  PIN o[33]
    DIRECTION OUTPUT ;
    USE SIGNAL ;
    PORT
      LAYER M4 ;
        RECT  0 43.92 0.084 43.944 ;
    END
  END o[33]
  PIN o[340]
    DIRECTION OUTPUT ;
    USE SIGNAL ;
    PORT
      LAYER M4 ;
        RECT  0 51.888 0.084 51.912 ;
    END
  END o[340]
  PIN o[341]
    DIRECTION OUTPUT ;
    USE SIGNAL ;
    PORT
      LAYER M4 ;
        RECT  0 51.984 0.084 52.008 ;
    END
  END o[341]
  PIN o[342]
    DIRECTION OUTPUT ;
    USE SIGNAL ;
    PORT
      LAYER M4 ;
        RECT  0 52.08 0.084 52.104 ;
    END
  END o[342]
  PIN o[343]
    DIRECTION OUTPUT ;
    USE SIGNAL ;
    PORT
      LAYER M4 ;
        RECT  0 52.176 0.084 52.2 ;
    END
  END o[343]
  PIN o[344]
    DIRECTION OUTPUT ;
    USE SIGNAL ;
    PORT
      LAYER M4 ;
        RECT  0 52.272 0.084 52.296 ;
    END
  END o[344]
  PIN o[345]
    DIRECTION OUTPUT ;
    USE SIGNAL ;
    PORT
      LAYER M4 ;
        RECT  0 52.368 0.084 52.392 ;
    END
  END o[345]
  PIN o[346]
    DIRECTION OUTPUT ;
    USE SIGNAL ;
    PORT
      LAYER M4 ;
        RECT  0 52.464 0.084 52.488 ;
    END
  END o[346]
  PIN o[347]
    DIRECTION OUTPUT ;
    USE SIGNAL ;
    PORT
      LAYER M4 ;
        RECT  0 52.56 0.084 52.584 ;
    END
  END o[347]
  PIN o[348]
    DIRECTION OUTPUT ;
    USE SIGNAL ;
    PORT
      LAYER M4 ;
        RECT  0 52.656 0.084 52.68 ;
    END
  END o[348]
  PIN o[349]
    DIRECTION OUTPUT ;
    USE SIGNAL ;
    PORT
      LAYER M4 ;
        RECT  0 52.752 0.084 52.776 ;
    END
  END o[349]
  PIN o[34]
    DIRECTION OUTPUT ;
    USE SIGNAL ;
    PORT
      LAYER M4 ;
        RECT  0 44.016 0.084 44.04 ;
    END
  END o[34]
  PIN o[350]
    DIRECTION OUTPUT ;
    USE SIGNAL ;
    PORT
      LAYER M4 ;
        RECT  0 37.488 0.084 37.512 ;
    END
  END o[350]
  PIN o[351]
    DIRECTION OUTPUT ;
    USE SIGNAL ;
    PORT
      LAYER M4 ;
        RECT  0 37.584 0.084 37.608 ;
    END
  END o[351]
  PIN o[352]
    DIRECTION OUTPUT ;
    USE SIGNAL ;
    PORT
      LAYER M4 ;
        RECT  0 37.68 0.084 37.704 ;
    END
  END o[352]
  PIN o[353]
    DIRECTION OUTPUT ;
    USE SIGNAL ;
    PORT
      LAYER M4 ;
        RECT  0 37.776 0.084 37.8 ;
    END
  END o[353]
  PIN o[354]
    DIRECTION OUTPUT ;
    USE SIGNAL ;
    PORT
      LAYER M4 ;
        RECT  0 37.872 0.084 37.896 ;
    END
  END o[354]
  PIN o[355]
    DIRECTION OUTPUT ;
    USE SIGNAL ;
    PORT
      LAYER M4 ;
        RECT  0 37.968 0.084 37.992 ;
    END
  END o[355]
  PIN o[356]
    DIRECTION OUTPUT ;
    USE SIGNAL ;
    PORT
      LAYER M4 ;
        RECT  0 38.064 0.084 38.088 ;
    END
  END o[356]
  PIN o[357]
    DIRECTION OUTPUT ;
    USE SIGNAL ;
    PORT
      LAYER M4 ;
        RECT  0 38.16 0.084 38.184 ;
    END
  END o[357]
  PIN o[358]
    DIRECTION OUTPUT ;
    USE SIGNAL ;
    PORT
      LAYER M4 ;
        RECT  0 38.256 0.084 38.28 ;
    END
  END o[358]
  PIN o[359]
    DIRECTION OUTPUT ;
    USE SIGNAL ;
    PORT
      LAYER M4 ;
        RECT  0 38.352 0.084 38.376 ;
    END
  END o[359]
  PIN o[35]
    DIRECTION OUTPUT ;
    USE SIGNAL ;
    PORT
      LAYER M4 ;
        RECT  0 44.112 0.084 44.136 ;
    END
  END o[35]
  PIN o[360]
    DIRECTION OUTPUT ;
    USE SIGNAL ;
    PORT
      LAYER M4 ;
        RECT  0 38.448 0.084 38.472 ;
    END
  END o[360]
  PIN o[361]
    DIRECTION OUTPUT ;
    USE SIGNAL ;
    PORT
      LAYER M4 ;
        RECT  0 38.544 0.084 38.568 ;
    END
  END o[361]
  PIN o[362]
    DIRECTION OUTPUT ;
    USE SIGNAL ;
    PORT
      LAYER M4 ;
        RECT  0 38.64 0.084 38.664 ;
    END
  END o[362]
  PIN o[363]
    DIRECTION OUTPUT ;
    USE SIGNAL ;
    PORT
      LAYER M4 ;
        RECT  0 38.736 0.084 38.76 ;
    END
  END o[363]
  PIN o[364]
    DIRECTION OUTPUT ;
    USE SIGNAL ;
    PORT
      LAYER M4 ;
        RECT  0 38.832 0.084 38.856 ;
    END
  END o[364]
  PIN o[365]
    DIRECTION OUTPUT ;
    USE SIGNAL ;
    PORT
      LAYER M4 ;
        RECT  0 38.928 0.084 38.952 ;
    END
  END o[365]
  PIN o[366]
    DIRECTION OUTPUT ;
    USE SIGNAL ;
    PORT
      LAYER M4 ;
        RECT  0 39.024 0.084 39.048 ;
    END
  END o[366]
  PIN o[367]
    DIRECTION OUTPUT ;
    USE SIGNAL ;
    PORT
      LAYER M4 ;
        RECT  0 39.12 0.084 39.144 ;
    END
  END o[367]
  PIN o[368]
    DIRECTION OUTPUT ;
    USE SIGNAL ;
    PORT
      LAYER M4 ;
        RECT  0 39.216 0.084 39.24 ;
    END
  END o[368]
  PIN o[369]
    DIRECTION OUTPUT ;
    USE SIGNAL ;
    PORT
      LAYER M4 ;
        RECT  0 39.312 0.084 39.336 ;
    END
  END o[369]
  PIN o[36]
    DIRECTION OUTPUT ;
    USE SIGNAL ;
    PORT
      LAYER M4 ;
        RECT  0 44.208 0.084 44.232 ;
    END
  END o[36]
  PIN o[370]
    DIRECTION OUTPUT ;
    USE SIGNAL ;
    PORT
      LAYER M4 ;
        RECT  0 39.408 0.084 39.432 ;
    END
  END o[370]
  PIN o[371]
    DIRECTION OUTPUT ;
    USE SIGNAL ;
    PORT
      LAYER M4 ;
        RECT  0 39.504 0.084 39.528 ;
    END
  END o[371]
  PIN o[372]
    DIRECTION OUTPUT ;
    USE SIGNAL ;
    PORT
      LAYER M4 ;
        RECT  0 39.6 0.084 39.624 ;
    END
  END o[372]
  PIN o[373]
    DIRECTION OUTPUT ;
    USE SIGNAL ;
    PORT
      LAYER M4 ;
        RECT  0 39.696 0.084 39.72 ;
    END
  END o[373]
  PIN o[374]
    DIRECTION OUTPUT ;
    USE SIGNAL ;
    PORT
      LAYER M4 ;
        RECT  0 39.792 0.084 39.816 ;
    END
  END o[374]
  PIN o[375]
    DIRECTION OUTPUT ;
    USE SIGNAL ;
    PORT
      LAYER M4 ;
        RECT  0 39.888 0.084 39.912 ;
    END
  END o[375]
  PIN o[376]
    DIRECTION OUTPUT ;
    USE SIGNAL ;
    PORT
      LAYER M4 ;
        RECT  0 39.984 0.084 40.008 ;
    END
  END o[376]
  PIN o[377]
    DIRECTION OUTPUT ;
    USE SIGNAL ;
    PORT
      LAYER M4 ;
        RECT  0 40.08 0.084 40.104 ;
    END
  END o[377]
  PIN o[378]
    DIRECTION OUTPUT ;
    USE SIGNAL ;
    PORT
      LAYER M4 ;
        RECT  0 40.176 0.084 40.2 ;
    END
  END o[378]
  PIN o[379]
    DIRECTION OUTPUT ;
    USE SIGNAL ;
    PORT
      LAYER M4 ;
        RECT  0 40.272 0.084 40.296 ;
    END
  END o[379]
  PIN o[37]
    DIRECTION OUTPUT ;
    USE SIGNAL ;
    PORT
      LAYER M4 ;
        RECT  0 44.304 0.084 44.328 ;
    END
  END o[37]
  PIN o[380]
    DIRECTION OUTPUT ;
    USE SIGNAL ;
    PORT
      LAYER M4 ;
        RECT  0 40.368 0.084 40.392 ;
    END
  END o[380]
  PIN o[381]
    DIRECTION OUTPUT ;
    USE SIGNAL ;
    PORT
      LAYER M4 ;
        RECT  0 40.464 0.084 40.488 ;
    END
  END o[381]
  PIN o[382]
    DIRECTION OUTPUT ;
    USE SIGNAL ;
    PORT
      LAYER M4 ;
        RECT  0 27.504 0.084 27.528 ;
    END
  END o[382]
  PIN o[383]
    DIRECTION OUTPUT ;
    USE SIGNAL ;
    PORT
      LAYER M4 ;
        RECT  0 27.6 0.084 27.624 ;
    END
  END o[383]
  PIN o[384]
    DIRECTION OUTPUT ;
    USE SIGNAL ;
    PORT
      LAYER M4 ;
        RECT  0 27.696 0.084 27.72 ;
    END
  END o[384]
  PIN o[385]
    DIRECTION OUTPUT ;
    USE SIGNAL ;
    PORT
      LAYER M4 ;
        RECT  0 27.792 0.084 27.816 ;
    END
  END o[385]
  PIN o[386]
    DIRECTION OUTPUT ;
    USE SIGNAL ;
    PORT
      LAYER M4 ;
        RECT  0 27.888 0.084 27.912 ;
    END
  END o[386]
  PIN o[387]
    DIRECTION OUTPUT ;
    USE SIGNAL ;
    PORT
      LAYER M4 ;
        RECT  0 27.984 0.084 28.008 ;
    END
  END o[387]
  PIN o[388]
    DIRECTION OUTPUT ;
    USE SIGNAL ;
    PORT
      LAYER M4 ;
        RECT  0 28.08 0.084 28.104 ;
    END
  END o[388]
  PIN o[389]
    DIRECTION OUTPUT ;
    USE SIGNAL ;
    PORT
      LAYER M4 ;
        RECT  0 28.176 0.084 28.2 ;
    END
  END o[389]
  PIN o[38]
    DIRECTION OUTPUT ;
    USE SIGNAL ;
    PORT
      LAYER M4 ;
        RECT  0 44.4 0.084 44.424 ;
    END
  END o[38]
  PIN o[390]
    DIRECTION OUTPUT ;
    USE SIGNAL ;
    PORT
      LAYER M4 ;
        RECT  0 28.272 0.084 28.296 ;
    END
  END o[390]
  PIN o[391]
    DIRECTION OUTPUT ;
    USE SIGNAL ;
    PORT
      LAYER M4 ;
        RECT  0 28.368 0.084 28.392 ;
    END
  END o[391]
  PIN o[392]
    DIRECTION OUTPUT ;
    USE SIGNAL ;
    PORT
      LAYER M4 ;
        RECT  0 28.464 0.084 28.488 ;
    END
  END o[392]
  PIN o[393]
    DIRECTION OUTPUT ;
    USE SIGNAL ;
    PORT
      LAYER M4 ;
        RECT  0 28.56 0.084 28.584 ;
    END
  END o[393]
  PIN o[394]
    DIRECTION OUTPUT ;
    USE SIGNAL ;
    PORT
      LAYER M4 ;
        RECT  0 28.656 0.084 28.68 ;
    END
  END o[394]
  PIN o[395]
    DIRECTION OUTPUT ;
    USE SIGNAL ;
    PORT
      LAYER M4 ;
        RECT  0 28.752 0.084 28.776 ;
    END
  END o[395]
  PIN o[396]
    DIRECTION OUTPUT ;
    USE SIGNAL ;
    PORT
      LAYER M4 ;
        RECT  0 28.848 0.084 28.872 ;
    END
  END o[396]
  PIN o[397]
    DIRECTION OUTPUT ;
    USE SIGNAL ;
    PORT
      LAYER M4 ;
        RECT  0 28.944 0.084 28.968 ;
    END
  END o[397]
  PIN o[398]
    DIRECTION OUTPUT ;
    USE SIGNAL ;
    PORT
      LAYER M4 ;
        RECT  0 29.04 0.084 29.064 ;
    END
  END o[398]
  PIN o[399]
    DIRECTION OUTPUT ;
    USE SIGNAL ;
    PORT
      LAYER M4 ;
        RECT  0 29.136 0.084 29.16 ;
    END
  END o[399]
  PIN o[39]
    DIRECTION OUTPUT ;
    USE SIGNAL ;
    PORT
      LAYER M4 ;
        RECT  0 44.496 0.084 44.52 ;
    END
  END o[39]
  PIN o[3]
    DIRECTION OUTPUT ;
    USE SIGNAL ;
    PORT
      LAYER M4 ;
        RECT  0 31.056 0.084 31.08 ;
    END
  END o[3]
  PIN o[400]
    DIRECTION OUTPUT ;
    USE SIGNAL ;
    PORT
      LAYER M4 ;
        RECT  0 29.232 0.084 29.256 ;
    END
  END o[400]
  PIN o[401]
    DIRECTION OUTPUT ;
    USE SIGNAL ;
    PORT
      LAYER M4 ;
        RECT  0 29.328 0.084 29.352 ;
    END
  END o[401]
  PIN o[402]
    DIRECTION OUTPUT ;
    USE SIGNAL ;
    PORT
      LAYER M4 ;
        RECT  0 29.424 0.084 29.448 ;
    END
  END o[402]
  PIN o[403]
    DIRECTION OUTPUT ;
    USE SIGNAL ;
    PORT
      LAYER M4 ;
        RECT  0 29.52 0.084 29.544 ;
    END
  END o[403]
  PIN o[404]
    DIRECTION OUTPUT ;
    USE SIGNAL ;
    PORT
      LAYER M4 ;
        RECT  0 29.616 0.084 29.64 ;
    END
  END o[404]
  PIN o[405]
    DIRECTION OUTPUT ;
    USE SIGNAL ;
    PORT
      LAYER M4 ;
        RECT  0 29.712 0.084 29.736 ;
    END
  END o[405]
  PIN o[406]
    DIRECTION OUTPUT ;
    USE SIGNAL ;
    PORT
      LAYER M4 ;
        RECT  0 29.808 0.084 29.832 ;
    END
  END o[406]
  PIN o[407]
    DIRECTION OUTPUT ;
    USE SIGNAL ;
    PORT
      LAYER M4 ;
        RECT  0 29.904 0.084 29.928 ;
    END
  END o[407]
  PIN o[408]
    DIRECTION OUTPUT ;
    USE SIGNAL ;
    PORT
      LAYER M4 ;
        RECT  0 30 0.084 30.024 ;
    END
  END o[408]
  PIN o[409]
    DIRECTION OUTPUT ;
    USE SIGNAL ;
    PORT
      LAYER M4 ;
        RECT  0 30.096 0.084 30.12 ;
    END
  END o[409]
  PIN o[40]
    DIRECTION OUTPUT ;
    USE SIGNAL ;
    PORT
      LAYER M4 ;
        RECT  0 44.592 0.084 44.616 ;
    END
  END o[40]
  PIN o[410]
    DIRECTION OUTPUT ;
    USE SIGNAL ;
    PORT
      LAYER M4 ;
        RECT  0 30.192 0.084 30.216 ;
    END
  END o[410]
  PIN o[411]
    DIRECTION OUTPUT ;
    USE SIGNAL ;
    PORT
      LAYER M4 ;
        RECT  0 30.288 0.084 30.312 ;
    END
  END o[411]
  PIN o[412]
    DIRECTION OUTPUT ;
    USE SIGNAL ;
    PORT
      LAYER M4 ;
        RECT  0 30.384 0.084 30.408 ;
    END
  END o[412]
  PIN o[413]
    DIRECTION OUTPUT ;
    USE SIGNAL ;
    PORT
      LAYER M4 ;
        RECT  0 30.48 0.084 30.504 ;
    END
  END o[413]
  PIN o[414]
    DIRECTION OUTPUT ;
    USE SIGNAL ;
    PORT
      LAYER M4 ;
        RECT  0 18.288 0.084 18.312 ;
    END
  END o[414]
  PIN o[415]
    DIRECTION OUTPUT ;
    USE SIGNAL ;
    PORT
      LAYER M4 ;
        RECT  0 18.384 0.084 18.408 ;
    END
  END o[415]
  PIN o[416]
    DIRECTION OUTPUT ;
    USE SIGNAL ;
    PORT
      LAYER M4 ;
        RECT  0 18.48 0.084 18.504 ;
    END
  END o[416]
  PIN o[417]
    DIRECTION OUTPUT ;
    USE SIGNAL ;
    PORT
      LAYER M4 ;
        RECT  0 18.576 0.084 18.6 ;
    END
  END o[417]
  PIN o[418]
    DIRECTION OUTPUT ;
    USE SIGNAL ;
    PORT
      LAYER M4 ;
        RECT  0 18.672 0.084 18.696 ;
    END
  END o[418]
  PIN o[419]
    DIRECTION OUTPUT ;
    USE SIGNAL ;
    PORT
      LAYER M4 ;
        RECT  0 18.768 0.084 18.792 ;
    END
  END o[419]
  PIN o[41]
    DIRECTION OUTPUT ;
    USE SIGNAL ;
    PORT
      LAYER M4 ;
        RECT  0 44.688 0.084 44.712 ;
    END
  END o[41]
  PIN o[420]
    DIRECTION OUTPUT ;
    USE SIGNAL ;
    PORT
      LAYER M4 ;
        RECT  0 18.864 0.084 18.888 ;
    END
  END o[420]
  PIN o[421]
    DIRECTION OUTPUT ;
    USE SIGNAL ;
    PORT
      LAYER M4 ;
        RECT  0 18.96 0.084 18.984 ;
    END
  END o[421]
  PIN o[422]
    DIRECTION OUTPUT ;
    USE SIGNAL ;
    PORT
      LAYER M4 ;
        RECT  0 19.056 0.084 19.08 ;
    END
  END o[422]
  PIN o[423]
    DIRECTION OUTPUT ;
    USE SIGNAL ;
    PORT
      LAYER M4 ;
        RECT  0 19.152 0.084 19.176 ;
    END
  END o[423]
  PIN o[424]
    DIRECTION OUTPUT ;
    USE SIGNAL ;
    PORT
      LAYER M4 ;
        RECT  0 19.248 0.084 19.272 ;
    END
  END o[424]
  PIN o[425]
    DIRECTION OUTPUT ;
    USE SIGNAL ;
    PORT
      LAYER M4 ;
        RECT  0 19.344 0.084 19.368 ;
    END
  END o[425]
  PIN o[426]
    DIRECTION OUTPUT ;
    USE SIGNAL ;
    PORT
      LAYER M4 ;
        RECT  0 19.44 0.084 19.464 ;
    END
  END o[426]
  PIN o[427]
    DIRECTION OUTPUT ;
    USE SIGNAL ;
    PORT
      LAYER M4 ;
        RECT  0 19.536 0.084 19.56 ;
    END
  END o[427]
  PIN o[428]
    DIRECTION OUTPUT ;
    USE SIGNAL ;
    PORT
      LAYER M4 ;
        RECT  0 19.632 0.084 19.656 ;
    END
  END o[428]
  PIN o[429]
    DIRECTION OUTPUT ;
    USE SIGNAL ;
    PORT
      LAYER M4 ;
        RECT  0 19.728 0.084 19.752 ;
    END
  END o[429]
  PIN o[42]
    DIRECTION OUTPUT ;
    USE SIGNAL ;
    PORT
      LAYER M4 ;
        RECT  0 44.784 0.084 44.808 ;
    END
  END o[42]
  PIN o[430]
    DIRECTION OUTPUT ;
    USE SIGNAL ;
    PORT
      LAYER M4 ;
        RECT  0 19.824 0.084 19.848 ;
    END
  END o[430]
  PIN o[431]
    DIRECTION OUTPUT ;
    USE SIGNAL ;
    PORT
      LAYER M4 ;
        RECT  0 19.92 0.084 19.944 ;
    END
  END o[431]
  PIN o[432]
    DIRECTION OUTPUT ;
    USE SIGNAL ;
    PORT
      LAYER M4 ;
        RECT  0 20.016 0.084 20.04 ;
    END
  END o[432]
  PIN o[433]
    DIRECTION OUTPUT ;
    USE SIGNAL ;
    PORT
      LAYER M4 ;
        RECT  0 20.112 0.084 20.136 ;
    END
  END o[433]
  PIN o[434]
    DIRECTION OUTPUT ;
    USE SIGNAL ;
    PORT
      LAYER M4 ;
        RECT  0 20.208 0.084 20.232 ;
    END
  END o[434]
  PIN o[435]
    DIRECTION OUTPUT ;
    USE SIGNAL ;
    PORT
      LAYER M4 ;
        RECT  0 20.304 0.084 20.328 ;
    END
  END o[435]
  PIN o[436]
    DIRECTION OUTPUT ;
    USE SIGNAL ;
    PORT
      LAYER M4 ;
        RECT  0 20.4 0.084 20.424 ;
    END
  END o[436]
  PIN o[437]
    DIRECTION OUTPUT ;
    USE SIGNAL ;
    PORT
      LAYER M4 ;
        RECT  0 20.496 0.084 20.52 ;
    END
  END o[437]
  PIN o[438]
    DIRECTION OUTPUT ;
    USE SIGNAL ;
    PORT
      LAYER M4 ;
        RECT  0 20.592 0.084 20.616 ;
    END
  END o[438]
  PIN o[439]
    DIRECTION OUTPUT ;
    USE SIGNAL ;
    PORT
      LAYER M4 ;
        RECT  0 20.688 0.084 20.712 ;
    END
  END o[439]
  PIN o[43]
    DIRECTION OUTPUT ;
    USE SIGNAL ;
    PORT
      LAYER M4 ;
        RECT  0 44.88 0.084 44.904 ;
    END
  END o[43]
  PIN o[440]
    DIRECTION OUTPUT ;
    USE SIGNAL ;
    PORT
      LAYER M4 ;
        RECT  0 20.784 0.084 20.808 ;
    END
  END o[440]
  PIN o[441]
    DIRECTION OUTPUT ;
    USE SIGNAL ;
    PORT
      LAYER M4 ;
        RECT  0 20.88 0.084 20.904 ;
    END
  END o[441]
  PIN o[442]
    DIRECTION OUTPUT ;
    USE SIGNAL ;
    PORT
      LAYER M4 ;
        RECT  0 20.976 0.084 21 ;
    END
  END o[442]
  PIN o[443]
    DIRECTION OUTPUT ;
    USE SIGNAL ;
    PORT
      LAYER M4 ;
        RECT  0 21.072 0.084 21.096 ;
    END
  END o[443]
  PIN o[444]
    DIRECTION OUTPUT ;
    USE SIGNAL ;
    PORT
      LAYER M4 ;
        RECT  0 21.168 0.084 21.192 ;
    END
  END o[444]
  PIN o[445]
    DIRECTION OUTPUT ;
    USE SIGNAL ;
    PORT
      LAYER M4 ;
        RECT  0 21.264 0.084 21.288 ;
    END
  END o[445]
  PIN o[446]
    DIRECTION OUTPUT ;
    USE SIGNAL ;
    PORT
      LAYER M4 ;
        RECT  0 5.232 0.084 5.256 ;
    END
  END o[446]
  PIN o[447]
    DIRECTION OUTPUT ;
    USE SIGNAL ;
    PORT
      LAYER M4 ;
        RECT  0 5.328 0.084 5.352 ;
    END
  END o[447]
  PIN o[448]
    DIRECTION OUTPUT ;
    USE SIGNAL ;
    PORT
      LAYER M4 ;
        RECT  0 5.424 0.084 5.448 ;
    END
  END o[448]
  PIN o[449]
    DIRECTION OUTPUT ;
    USE SIGNAL ;
    PORT
      LAYER M4 ;
        RECT  0 5.52 0.084 5.544 ;
    END
  END o[449]
  PIN o[44]
    DIRECTION OUTPUT ;
    USE SIGNAL ;
    PORT
      LAYER M4 ;
        RECT  0 44.976 0.084 45 ;
    END
  END o[44]
  PIN o[450]
    DIRECTION OUTPUT ;
    USE SIGNAL ;
    PORT
      LAYER M4 ;
        RECT  0 5.616 0.084 5.64 ;
    END
  END o[450]
  PIN o[451]
    DIRECTION OUTPUT ;
    USE SIGNAL ;
    PORT
      LAYER M4 ;
        RECT  0 5.712 0.084 5.736 ;
    END
  END o[451]
  PIN o[452]
    DIRECTION OUTPUT ;
    USE SIGNAL ;
    PORT
      LAYER M4 ;
        RECT  0 5.808 0.084 5.832 ;
    END
  END o[452]
  PIN o[453]
    DIRECTION OUTPUT ;
    USE SIGNAL ;
    PORT
      LAYER M4 ;
        RECT  0 5.904 0.084 5.928 ;
    END
  END o[453]
  PIN o[454]
    DIRECTION OUTPUT ;
    USE SIGNAL ;
    PORT
      LAYER M4 ;
        RECT  0 6 0.084 6.024 ;
    END
  END o[454]
  PIN o[455]
    DIRECTION OUTPUT ;
    USE SIGNAL ;
    PORT
      LAYER M4 ;
        RECT  0 6.096 0.084 6.12 ;
    END
  END o[455]
  PIN o[456]
    DIRECTION OUTPUT ;
    USE SIGNAL ;
    PORT
      LAYER M4 ;
        RECT  0 6.192 0.084 6.216 ;
    END
  END o[456]
  PIN o[457]
    DIRECTION OUTPUT ;
    USE SIGNAL ;
    PORT
      LAYER M4 ;
        RECT  0 6.288 0.084 6.312 ;
    END
  END o[457]
  PIN o[458]
    DIRECTION OUTPUT ;
    USE SIGNAL ;
    PORT
      LAYER M4 ;
        RECT  0 6.384 0.084 6.408 ;
    END
  END o[458]
  PIN o[459]
    DIRECTION OUTPUT ;
    USE SIGNAL ;
    PORT
      LAYER M4 ;
        RECT  0 6.48 0.084 6.504 ;
    END
  END o[459]
  PIN o[45]
    DIRECTION OUTPUT ;
    USE SIGNAL ;
    PORT
      LAYER M4 ;
        RECT  0 45.072 0.084 45.096 ;
    END
  END o[45]
  PIN o[460]
    DIRECTION OUTPUT ;
    USE SIGNAL ;
    PORT
      LAYER M4 ;
        RECT  0 6.576 0.084 6.6 ;
    END
  END o[460]
  PIN o[461]
    DIRECTION OUTPUT ;
    USE SIGNAL ;
    PORT
      LAYER M4 ;
        RECT  0 6.672 0.084 6.696 ;
    END
  END o[461]
  PIN o[462]
    DIRECTION OUTPUT ;
    USE SIGNAL ;
    PORT
      LAYER M4 ;
        RECT  0 6.768 0.084 6.792 ;
    END
  END o[462]
  PIN o[463]
    DIRECTION OUTPUT ;
    USE SIGNAL ;
    PORT
      LAYER M4 ;
        RECT  0 6.864 0.084 6.888 ;
    END
  END o[463]
  PIN o[464]
    DIRECTION OUTPUT ;
    USE SIGNAL ;
    PORT
      LAYER M4 ;
        RECT  0 6.96 0.084 6.984 ;
    END
  END o[464]
  PIN o[465]
    DIRECTION OUTPUT ;
    USE SIGNAL ;
    PORT
      LAYER M4 ;
        RECT  0 7.056 0.084 7.08 ;
    END
  END o[465]
  PIN o[466]
    DIRECTION OUTPUT ;
    USE SIGNAL ;
    PORT
      LAYER M4 ;
        RECT  0 7.152 0.084 7.176 ;
    END
  END o[466]
  PIN o[467]
    DIRECTION OUTPUT ;
    USE SIGNAL ;
    PORT
      LAYER M4 ;
        RECT  0 7.248 0.084 7.272 ;
    END
  END o[467]
  PIN o[468]
    DIRECTION OUTPUT ;
    USE SIGNAL ;
    PORT
      LAYER M4 ;
        RECT  0 7.344 0.084 7.368 ;
    END
  END o[468]
  PIN o[469]
    DIRECTION OUTPUT ;
    USE SIGNAL ;
    PORT
      LAYER M4 ;
        RECT  0 7.44 0.084 7.464 ;
    END
  END o[469]
  PIN o[46]
    DIRECTION OUTPUT ;
    USE SIGNAL ;
    PORT
      LAYER M4 ;
        RECT  0 45.168 0.084 45.192 ;
    END
  END o[46]
  PIN o[470]
    DIRECTION OUTPUT ;
    USE SIGNAL ;
    PORT
      LAYER M4 ;
        RECT  0 7.536 0.084 7.56 ;
    END
  END o[470]
  PIN o[471]
    DIRECTION OUTPUT ;
    USE SIGNAL ;
    PORT
      LAYER M4 ;
        RECT  0 7.632 0.084 7.656 ;
    END
  END o[471]
  PIN o[472]
    DIRECTION OUTPUT ;
    USE SIGNAL ;
    PORT
      LAYER M4 ;
        RECT  0 7.728 0.084 7.752 ;
    END
  END o[472]
  PIN o[473]
    DIRECTION OUTPUT ;
    USE SIGNAL ;
    PORT
      LAYER M4 ;
        RECT  0 7.824 0.084 7.848 ;
    END
  END o[473]
  PIN o[474]
    DIRECTION OUTPUT ;
    USE SIGNAL ;
    PORT
      LAYER M4 ;
        RECT  0 7.92 0.084 7.944 ;
    END
  END o[474]
  PIN o[475]
    DIRECTION OUTPUT ;
    USE SIGNAL ;
    PORT
      LAYER M4 ;
        RECT  0 8.016 0.084 8.04 ;
    END
  END o[475]
  PIN o[476]
    DIRECTION OUTPUT ;
    USE SIGNAL ;
    PORT
      LAYER M4 ;
        RECT  0 8.112 0.084 8.136 ;
    END
  END o[476]
  PIN o[477]
    DIRECTION OUTPUT ;
    USE SIGNAL ;
    PORT
      LAYER M4 ;
        RECT  0 8.208 0.084 8.232 ;
    END
  END o[477]
  PIN o[478]
    DIRECTION OUTPUT ;
    USE SIGNAL ;
    PORT
      LAYER M4 ;
        RECT  0 8.304 0.084 8.328 ;
    END
  END o[478]
  PIN o[479]
    DIRECTION OUTPUT ;
    USE SIGNAL ;
    PORT
      LAYER M4 ;
        RECT  0 8.4 0.084 8.424 ;
    END
  END o[479]
  PIN o[47]
    DIRECTION OUTPUT ;
    USE SIGNAL ;
    PORT
      LAYER M4 ;
        RECT  0 45.264 0.084 45.288 ;
    END
  END o[47]
  PIN o[480]
    DIRECTION OUTPUT ;
    USE SIGNAL ;
    PORT
      LAYER M4 ;
        RECT  0 8.496 0.084 8.52 ;
    END
  END o[480]
  PIN o[481]
    DIRECTION OUTPUT ;
    USE SIGNAL ;
    PORT
      LAYER M4 ;
        RECT  0 8.592 0.084 8.616 ;
    END
  END o[481]
  PIN o[482]
    DIRECTION OUTPUT ;
    USE SIGNAL ;
    PORT
      LAYER M4 ;
        RECT  0 8.688 0.084 8.712 ;
    END
  END o[482]
  PIN o[483]
    DIRECTION OUTPUT ;
    USE SIGNAL ;
    PORT
      LAYER M4 ;
        RECT  0 8.784 0.084 8.808 ;
    END
  END o[483]
  PIN o[484]
    DIRECTION OUTPUT ;
    USE SIGNAL ;
    PORT
      LAYER M4 ;
        RECT  0 8.88 0.084 8.904 ;
    END
  END o[484]
  PIN o[485]
    DIRECTION OUTPUT ;
    USE SIGNAL ;
    PORT
      LAYER M4 ;
        RECT  0 8.976 0.084 9 ;
    END
  END o[485]
  PIN o[486]
    DIRECTION OUTPUT ;
    USE SIGNAL ;
    PORT
      LAYER M4 ;
        RECT  0 9.072 0.084 9.096 ;
    END
  END o[486]
  PIN o[487]
    DIRECTION OUTPUT ;
    USE SIGNAL ;
    PORT
      LAYER M4 ;
        RECT  0 9.168 0.084 9.192 ;
    END
  END o[487]
  PIN o[488]
    DIRECTION OUTPUT ;
    USE SIGNAL ;
    PORT
      LAYER M4 ;
        RECT  0 9.264 0.084 9.288 ;
    END
  END o[488]
  PIN o[489]
    DIRECTION OUTPUT ;
    USE SIGNAL ;
    PORT
      LAYER M4 ;
        RECT  0 9.36 0.084 9.384 ;
    END
  END o[489]
  PIN o[48]
    DIRECTION OUTPUT ;
    USE SIGNAL ;
    PORT
      LAYER M4 ;
        RECT  0 45.36 0.084 45.384 ;
    END
  END o[48]
  PIN o[490]
    DIRECTION OUTPUT ;
    USE SIGNAL ;
    PORT
      LAYER M4 ;
        RECT  0 9.456 0.084 9.48 ;
    END
  END o[490]
  PIN o[491]
    DIRECTION OUTPUT ;
    USE SIGNAL ;
    PORT
      LAYER M4 ;
        RECT  0 9.552 0.084 9.576 ;
    END
  END o[491]
  PIN o[492]
    DIRECTION OUTPUT ;
    USE SIGNAL ;
    PORT
      LAYER M4 ;
        RECT  0 9.648 0.084 9.672 ;
    END
  END o[492]
  PIN o[493]
    DIRECTION OUTPUT ;
    USE SIGNAL ;
    PORT
      LAYER M4 ;
        RECT  0 9.744 0.084 9.768 ;
    END
  END o[493]
  PIN o[494]
    DIRECTION OUTPUT ;
    USE SIGNAL ;
    PORT
      LAYER M4 ;
        RECT  0 9.84 0.084 9.864 ;
    END
  END o[494]
  PIN o[495]
    DIRECTION OUTPUT ;
    USE SIGNAL ;
    PORT
      LAYER M4 ;
        RECT  0 9.936 0.084 9.96 ;
    END
  END o[495]
  PIN o[496]
    DIRECTION OUTPUT ;
    USE SIGNAL ;
    PORT
      LAYER M4 ;
        RECT  0 10.032 0.084 10.056 ;
    END
  END o[496]
  PIN o[497]
    DIRECTION OUTPUT ;
    USE SIGNAL ;
    PORT
      LAYER M4 ;
        RECT  0 10.128 0.084 10.152 ;
    END
  END o[497]
  PIN o[498]
    DIRECTION OUTPUT ;
    USE SIGNAL ;
    PORT
      LAYER M4 ;
        RECT  0 10.224 0.084 10.248 ;
    END
  END o[498]
  PIN o[499]
    DIRECTION OUTPUT ;
    USE SIGNAL ;
    PORT
      LAYER M4 ;
        RECT  0 10.32 0.084 10.344 ;
    END
  END o[499]
  PIN o[49]
    DIRECTION OUTPUT ;
    USE SIGNAL ;
    PORT
      LAYER M4 ;
        RECT  0 45.456 0.084 45.48 ;
    END
  END o[49]
  PIN o[4]
    DIRECTION OUTPUT ;
    USE SIGNAL ;
    PORT
      LAYER M4 ;
        RECT  0 31.152 0.084 31.176 ;
    END
  END o[4]
  PIN o[500]
    DIRECTION OUTPUT ;
    USE SIGNAL ;
    PORT
      LAYER M4 ;
        RECT  0 10.416 0.084 10.44 ;
    END
  END o[500]
  PIN o[501]
    DIRECTION OUTPUT ;
    USE SIGNAL ;
    PORT
      LAYER M4 ;
        RECT  0 10.512 0.084 10.536 ;
    END
  END o[501]
  PIN o[502]
    DIRECTION OUTPUT ;
    USE SIGNAL ;
    PORT
      LAYER M4 ;
        RECT  0 10.608 0.084 10.632 ;
    END
  END o[502]
  PIN o[503]
    DIRECTION OUTPUT ;
    USE SIGNAL ;
    PORT
      LAYER M4 ;
        RECT  0 10.704 0.084 10.728 ;
    END
  END o[503]
  PIN o[504]
    DIRECTION OUTPUT ;
    USE SIGNAL ;
    PORT
      LAYER M4 ;
        RECT  0 10.8 0.084 10.824 ;
    END
  END o[504]
  PIN o[505]
    DIRECTION OUTPUT ;
    USE SIGNAL ;
    PORT
      LAYER M4 ;
        RECT  0 10.896 0.084 10.92 ;
    END
  END o[505]
  PIN o[506]
    DIRECTION OUTPUT ;
    USE SIGNAL ;
    PORT
      LAYER M4 ;
        RECT  0 10.992 0.084 11.016 ;
    END
  END o[506]
  PIN o[507]
    DIRECTION OUTPUT ;
    USE SIGNAL ;
    PORT
      LAYER M4 ;
        RECT  0 11.088 0.084 11.112 ;
    END
  END o[507]
  PIN o[508]
    DIRECTION OUTPUT ;
    USE SIGNAL ;
    PORT
      LAYER M4 ;
        RECT  0 11.184 0.084 11.208 ;
    END
  END o[508]
  PIN o[509]
    DIRECTION OUTPUT ;
    USE SIGNAL ;
    PORT
      LAYER M4 ;
        RECT  0 11.28 0.084 11.304 ;
    END
  END o[509]
  PIN o[50]
    DIRECTION OUTPUT ;
    USE SIGNAL ;
    PORT
      LAYER M4 ;
        RECT  0 45.552 0.084 45.576 ;
    END
  END o[50]
  PIN o[510]
    DIRECTION OUTPUT ;
    USE SIGNAL ;
    PORT
      LAYER M4 ;
        RECT  0 11.376 0.084 11.4 ;
    END
  END o[510]
  PIN o[511]
    DIRECTION OUTPUT ;
    USE SIGNAL ;
    PORT
      LAYER M4 ;
        RECT  0 11.472 0.084 11.496 ;
    END
  END o[511]
  PIN o[512]
    DIRECTION OUTPUT ;
    USE SIGNAL ;
    PORT
      LAYER M4 ;
        RECT  0 11.568 0.084 11.592 ;
    END
  END o[512]
  PIN o[513]
    DIRECTION OUTPUT ;
    USE SIGNAL ;
    PORT
      LAYER M4 ;
        RECT  0 11.664 0.084 11.688 ;
    END
  END o[513]
  PIN o[514]
    DIRECTION OUTPUT ;
    USE SIGNAL ;
    PORT
      LAYER M4 ;
        RECT  0 11.76 0.084 11.784 ;
    END
  END o[514]
  PIN o[515]
    DIRECTION OUTPUT ;
    USE SIGNAL ;
    PORT
      LAYER M4 ;
        RECT  0 11.856 0.084 11.88 ;
    END
  END o[515]
  PIN o[516]
    DIRECTION OUTPUT ;
    USE SIGNAL ;
    PORT
      LAYER M4 ;
        RECT  0 11.952 0.084 11.976 ;
    END
  END o[516]
  PIN o[517]
    DIRECTION OUTPUT ;
    USE SIGNAL ;
    PORT
      LAYER M4 ;
        RECT  0 12.048 0.084 12.072 ;
    END
  END o[517]
  PIN o[518]
    DIRECTION OUTPUT ;
    USE SIGNAL ;
    PORT
      LAYER M4 ;
        RECT  0 12.144 0.084 12.168 ;
    END
  END o[518]
  PIN o[519]
    DIRECTION OUTPUT ;
    USE SIGNAL ;
    PORT
      LAYER M4 ;
        RECT  0 12.24 0.084 12.264 ;
    END
  END o[519]
  PIN o[51]
    DIRECTION OUTPUT ;
    USE SIGNAL ;
    PORT
      LAYER M4 ;
        RECT  0 45.648 0.084 45.672 ;
    END
  END o[51]
  PIN o[520]
    DIRECTION OUTPUT ;
    USE SIGNAL ;
    PORT
      LAYER M4 ;
        RECT  0 12.336 0.084 12.36 ;
    END
  END o[520]
  PIN o[521]
    DIRECTION OUTPUT ;
    USE SIGNAL ;
    PORT
      LAYER M4 ;
        RECT  0 12.432 0.084 12.456 ;
    END
  END o[521]
  PIN o[522]
    DIRECTION OUTPUT ;
    USE SIGNAL ;
    PORT
      LAYER M4 ;
        RECT  0 12.528 0.084 12.552 ;
    END
  END o[522]
  PIN o[523]
    DIRECTION OUTPUT ;
    USE SIGNAL ;
    PORT
      LAYER M4 ;
        RECT  0 12.624 0.084 12.648 ;
    END
  END o[523]
  PIN o[524]
    DIRECTION OUTPUT ;
    USE SIGNAL ;
    PORT
      LAYER M4 ;
        RECT  0 12.72 0.084 12.744 ;
    END
  END o[524]
  PIN o[525]
    DIRECTION OUTPUT ;
    USE SIGNAL ;
    PORT
      LAYER M4 ;
        RECT  0 12.816 0.084 12.84 ;
    END
  END o[525]
  PIN o[526]
    DIRECTION OUTPUT ;
    USE SIGNAL ;
    PORT
      LAYER M4 ;
        RECT  0 12.912 0.084 12.936 ;
    END
  END o[526]
  PIN o[527]
    DIRECTION OUTPUT ;
    USE SIGNAL ;
    PORT
      LAYER M4 ;
        RECT  0 13.008 0.084 13.032 ;
    END
  END o[527]
  PIN o[528]
    DIRECTION OUTPUT ;
    USE SIGNAL ;
    PORT
      LAYER M4 ;
        RECT  0 13.104 0.084 13.128 ;
    END
  END o[528]
  PIN o[529]
    DIRECTION OUTPUT ;
    USE SIGNAL ;
    PORT
      LAYER M4 ;
        RECT  0 13.2 0.084 13.224 ;
    END
  END o[529]
  PIN o[52]
    DIRECTION OUTPUT ;
    USE SIGNAL ;
    PORT
      LAYER M4 ;
        RECT  0 45.744 0.084 45.768 ;
    END
  END o[52]
  PIN o[530]
    DIRECTION OUTPUT ;
    USE SIGNAL ;
    PORT
      LAYER M4 ;
        RECT  0 13.296 0.084 13.32 ;
    END
  END o[530]
  PIN o[531]
    DIRECTION OUTPUT ;
    USE SIGNAL ;
    PORT
      LAYER M4 ;
        RECT  0 13.392 0.084 13.416 ;
    END
  END o[531]
  PIN o[532]
    DIRECTION OUTPUT ;
    USE SIGNAL ;
    PORT
      LAYER M4 ;
        RECT  0 13.488 0.084 13.512 ;
    END
  END o[532]
  PIN o[533]
    DIRECTION OUTPUT ;
    USE SIGNAL ;
    PORT
      LAYER M4 ;
        RECT  0 13.584 0.084 13.608 ;
    END
  END o[533]
  PIN o[534]
    DIRECTION OUTPUT ;
    USE SIGNAL ;
    PORT
      LAYER M4 ;
        RECT  0 13.68 0.084 13.704 ;
    END
  END o[534]
  PIN o[535]
    DIRECTION OUTPUT ;
    USE SIGNAL ;
    PORT
      LAYER M4 ;
        RECT  0 13.776 0.084 13.8 ;
    END
  END o[535]
  PIN o[536]
    DIRECTION OUTPUT ;
    USE SIGNAL ;
    PORT
      LAYER M4 ;
        RECT  0 13.872 0.084 13.896 ;
    END
  END o[536]
  PIN o[537]
    DIRECTION OUTPUT ;
    USE SIGNAL ;
    PORT
      LAYER M4 ;
        RECT  0 13.968 0.084 13.992 ;
    END
  END o[537]
  PIN o[538]
    DIRECTION OUTPUT ;
    USE SIGNAL ;
    PORT
      LAYER M4 ;
        RECT  0 14.064 0.084 14.088 ;
    END
  END o[538]
  PIN o[539]
    DIRECTION OUTPUT ;
    USE SIGNAL ;
    PORT
      LAYER M4 ;
        RECT  0 14.16 0.084 14.184 ;
    END
  END o[539]
  PIN o[53]
    DIRECTION OUTPUT ;
    USE SIGNAL ;
    PORT
      LAYER M4 ;
        RECT  0 45.84 0.084 45.864 ;
    END
  END o[53]
  PIN o[540]
    DIRECTION OUTPUT ;
    USE SIGNAL ;
    PORT
      LAYER M4 ;
        RECT  0 14.256 0.084 14.28 ;
    END
  END o[540]
  PIN o[541]
    DIRECTION OUTPUT ;
    USE SIGNAL ;
    PORT
      LAYER M4 ;
        RECT  0 14.352 0.084 14.376 ;
    END
  END o[541]
  PIN o[542]
    DIRECTION OUTPUT ;
    USE SIGNAL ;
    PORT
      LAYER M4 ;
        RECT  0 22.512 0.084 22.536 ;
    END
  END o[542]
  PIN o[543]
    DIRECTION OUTPUT ;
    USE SIGNAL ;
    PORT
      LAYER M4 ;
        RECT  0 22.608 0.084 22.632 ;
    END
  END o[543]
  PIN o[544]
    DIRECTION OUTPUT ;
    USE SIGNAL ;
    PORT
      LAYER M4 ;
        RECT  0 22.704 0.084 22.728 ;
    END
  END o[544]
  PIN o[545]
    DIRECTION OUTPUT ;
    USE SIGNAL ;
    PORT
      LAYER M4 ;
        RECT  0 22.8 0.084 22.824 ;
    END
  END o[545]
  PIN o[546]
    DIRECTION OUTPUT ;
    USE SIGNAL ;
    PORT
      LAYER M4 ;
        RECT  0 22.896 0.084 22.92 ;
    END
  END o[546]
  PIN o[547]
    DIRECTION OUTPUT ;
    USE SIGNAL ;
    PORT
      LAYER M4 ;
        RECT  0 22.992 0.084 23.016 ;
    END
  END o[547]
  PIN o[548]
    DIRECTION OUTPUT ;
    USE SIGNAL ;
    PORT
      LAYER M4 ;
        RECT  0 23.088 0.084 23.112 ;
    END
  END o[548]
  PIN o[549]
    DIRECTION OUTPUT ;
    USE SIGNAL ;
    PORT
      LAYER M4 ;
        RECT  0 23.184 0.084 23.208 ;
    END
  END o[549]
  PIN o[54]
    DIRECTION OUTPUT ;
    USE SIGNAL ;
    PORT
      LAYER M4 ;
        RECT  0 45.936 0.084 45.96 ;
    END
  END o[54]
  PIN o[550]
    DIRECTION OUTPUT ;
    USE SIGNAL ;
    PORT
      LAYER M4 ;
        RECT  0 23.28 0.084 23.304 ;
    END
  END o[550]
  PIN o[551]
    DIRECTION OUTPUT ;
    USE SIGNAL ;
    PORT
      LAYER M4 ;
        RECT  0 23.376 0.084 23.4 ;
    END
  END o[551]
  PIN o[552]
    DIRECTION OUTPUT ;
    USE SIGNAL ;
    PORT
      LAYER M4 ;
        RECT  0 23.472 0.084 23.496 ;
    END
  END o[552]
  PIN o[553]
    DIRECTION OUTPUT ;
    USE SIGNAL ;
    PORT
      LAYER M4 ;
        RECT  0 23.568 0.084 23.592 ;
    END
  END o[553]
  PIN o[554]
    DIRECTION OUTPUT ;
    USE SIGNAL ;
    PORT
      LAYER M4 ;
        RECT  0 23.664 0.084 23.688 ;
    END
  END o[554]
  PIN o[555]
    DIRECTION OUTPUT ;
    USE SIGNAL ;
    PORT
      LAYER M4 ;
        RECT  0 23.76 0.084 23.784 ;
    END
  END o[555]
  PIN o[556]
    DIRECTION OUTPUT ;
    USE SIGNAL ;
    PORT
      LAYER M4 ;
        RECT  0 23.856 0.084 23.88 ;
    END
  END o[556]
  PIN o[557]
    DIRECTION OUTPUT ;
    USE SIGNAL ;
    PORT
      LAYER M4 ;
        RECT  0 23.952 0.084 23.976 ;
    END
  END o[557]
  PIN o[558]
    DIRECTION OUTPUT ;
    USE SIGNAL ;
    PORT
      LAYER M4 ;
        RECT  0 24.048 0.084 24.072 ;
    END
  END o[558]
  PIN o[559]
    DIRECTION OUTPUT ;
    USE SIGNAL ;
    PORT
      LAYER M4 ;
        RECT  0 24.144 0.084 24.168 ;
    END
  END o[559]
  PIN o[55]
    DIRECTION OUTPUT ;
    USE SIGNAL ;
    PORT
      LAYER M4 ;
        RECT  0 46.032 0.084 46.056 ;
    END
  END o[55]
  PIN o[560]
    DIRECTION OUTPUT ;
    USE SIGNAL ;
    PORT
      LAYER M4 ;
        RECT  0 24.24 0.084 24.264 ;
    END
  END o[560]
  PIN o[561]
    DIRECTION OUTPUT ;
    USE SIGNAL ;
    PORT
      LAYER M4 ;
        RECT  0 24.336 0.084 24.36 ;
    END
  END o[561]
  PIN o[56]
    DIRECTION OUTPUT ;
    USE SIGNAL ;
    PORT
      LAYER M4 ;
        RECT  0 46.128 0.084 46.152 ;
    END
  END o[56]
  PIN o[57]
    DIRECTION OUTPUT ;
    USE SIGNAL ;
    PORT
      LAYER M4 ;
        RECT  0 46.224 0.084 46.248 ;
    END
  END o[57]
  PIN o[58]
    DIRECTION OUTPUT ;
    USE SIGNAL ;
    PORT
      LAYER M4 ;
        RECT  0 46.32 0.084 46.344 ;
    END
  END o[58]
  PIN o[59]
    DIRECTION OUTPUT ;
    USE SIGNAL ;
    PORT
      LAYER M4 ;
        RECT  0 46.416 0.084 46.44 ;
    END
  END o[59]
  PIN o[5]
    DIRECTION OUTPUT ;
    USE SIGNAL ;
    PORT
      LAYER M4 ;
        RECT  0 31.248 0.084 31.272 ;
    END
  END o[5]
  PIN o[60]
    DIRECTION OUTPUT ;
    USE SIGNAL ;
    PORT
      LAYER M4 ;
        RECT  0 46.512 0.084 46.536 ;
    END
  END o[60]
  PIN o[61]
    DIRECTION OUTPUT ;
    USE SIGNAL ;
    PORT
      LAYER M4 ;
        RECT  0 46.608 0.084 46.632 ;
    END
  END o[61]
  PIN o[62]
    DIRECTION OUTPUT ;
    USE SIGNAL ;
    PORT
      LAYER M4 ;
        RECT  0 56.688 0.084 56.712 ;
    END
  END o[62]
  PIN o[63]
    DIRECTION OUTPUT ;
    USE SIGNAL ;
    PORT
      LAYER M4 ;
        RECT  0 56.784 0.084 56.808 ;
    END
  END o[63]
  PIN o[64]
    DIRECTION OUTPUT ;
    USE SIGNAL ;
    PORT
      LAYER M4 ;
        RECT  0 56.88 0.084 56.904 ;
    END
  END o[64]
  PIN o[65]
    DIRECTION OUTPUT ;
    USE SIGNAL ;
    PORT
      LAYER M4 ;
        RECT  0 56.976 0.084 57 ;
    END
  END o[65]
  PIN o[66]
    DIRECTION OUTPUT ;
    USE SIGNAL ;
    PORT
      LAYER M4 ;
        RECT  0 57.072 0.084 57.096 ;
    END
  END o[66]
  PIN o[67]
    DIRECTION OUTPUT ;
    USE SIGNAL ;
    PORT
      LAYER M4 ;
        RECT  0 57.168 0.084 57.192 ;
    END
  END o[67]
  PIN o[68]
    DIRECTION OUTPUT ;
    USE SIGNAL ;
    PORT
      LAYER M4 ;
        RECT  0 57.264 0.084 57.288 ;
    END
  END o[68]
  PIN o[69]
    DIRECTION OUTPUT ;
    USE SIGNAL ;
    PORT
      LAYER M4 ;
        RECT  0 57.36 0.084 57.384 ;
    END
  END o[69]
  PIN o[6]
    DIRECTION OUTPUT ;
    USE SIGNAL ;
    PORT
      LAYER M4 ;
        RECT  0 31.344 0.084 31.368 ;
    END
  END o[6]
  PIN o[70]
    DIRECTION OUTPUT ;
    USE SIGNAL ;
    PORT
      LAYER M4 ;
        RECT  0 57.456 0.084 57.48 ;
    END
  END o[70]
  PIN o[71]
    DIRECTION OUTPUT ;
    USE SIGNAL ;
    PORT
      LAYER M4 ;
        RECT  0 57.552 0.084 57.576 ;
    END
  END o[71]
  PIN o[72]
    DIRECTION OUTPUT ;
    USE SIGNAL ;
    PORT
      LAYER M4 ;
        RECT  0 57.648 0.084 57.672 ;
    END
  END o[72]
  PIN o[73]
    DIRECTION OUTPUT ;
    USE SIGNAL ;
    PORT
      LAYER M4 ;
        RECT  0 57.744 0.084 57.768 ;
    END
  END o[73]
  PIN o[74]
    DIRECTION OUTPUT ;
    USE SIGNAL ;
    PORT
      LAYER M4 ;
        RECT  0 57.84 0.084 57.864 ;
    END
  END o[74]
  PIN o[75]
    DIRECTION OUTPUT ;
    USE SIGNAL ;
    PORT
      LAYER M4 ;
        RECT  0 57.936 0.084 57.96 ;
    END
  END o[75]
  PIN o[76]
    DIRECTION OUTPUT ;
    USE SIGNAL ;
    PORT
      LAYER M4 ;
        RECT  0 58.032 0.084 58.056 ;
    END
  END o[76]
  PIN o[77]
    DIRECTION OUTPUT ;
    USE SIGNAL ;
    PORT
      LAYER M4 ;
        RECT  0 58.128 0.084 58.152 ;
    END
  END o[77]
  PIN o[78]
    DIRECTION OUTPUT ;
    USE SIGNAL ;
    PORT
      LAYER M4 ;
        RECT  0 58.224 0.084 58.248 ;
    END
  END o[78]
  PIN o[79]
    DIRECTION OUTPUT ;
    USE SIGNAL ;
    PORT
      LAYER M4 ;
        RECT  0 58.32 0.084 58.344 ;
    END
  END o[79]
  PIN o[7]
    DIRECTION OUTPUT ;
    USE SIGNAL ;
    PORT
      LAYER M4 ;
        RECT  0 31.44 0.084 31.464 ;
    END
  END o[7]
  PIN o[80]
    DIRECTION OUTPUT ;
    USE SIGNAL ;
    PORT
      LAYER M4 ;
        RECT  0 58.416 0.084 58.44 ;
    END
  END o[80]
  PIN o[81]
    DIRECTION OUTPUT ;
    USE SIGNAL ;
    PORT
      LAYER M4 ;
        RECT  0 58.512 0.084 58.536 ;
    END
  END o[81]
  PIN o[82]
    DIRECTION OUTPUT ;
    USE SIGNAL ;
    PORT
      LAYER M4 ;
        RECT  0 58.608 0.084 58.632 ;
    END
  END o[82]
  PIN o[83]
    DIRECTION OUTPUT ;
    USE SIGNAL ;
    PORT
      LAYER M4 ;
        RECT  0 58.704 0.084 58.728 ;
    END
  END o[83]
  PIN o[84]
    DIRECTION OUTPUT ;
    USE SIGNAL ;
    PORT
      LAYER M4 ;
        RECT  0 58.8 0.084 58.824 ;
    END
  END o[84]
  PIN o[85]
    DIRECTION OUTPUT ;
    USE SIGNAL ;
    PORT
      LAYER M4 ;
        RECT  0 58.896 0.084 58.92 ;
    END
  END o[85]
  PIN o[86]
    DIRECTION OUTPUT ;
    USE SIGNAL ;
    PORT
      LAYER M4 ;
        RECT  0 58.992 0.084 59.016 ;
    END
  END o[86]
  PIN o[87]
    DIRECTION OUTPUT ;
    USE SIGNAL ;
    PORT
      LAYER M4 ;
        RECT  0 59.088 0.084 59.112 ;
    END
  END o[87]
  PIN o[88]
    DIRECTION OUTPUT ;
    USE SIGNAL ;
    PORT
      LAYER M4 ;
        RECT  0 59.184 0.084 59.208 ;
    END
  END o[88]
  PIN o[89]
    DIRECTION OUTPUT ;
    USE SIGNAL ;
    PORT
      LAYER M4 ;
        RECT  0 59.28 0.084 59.304 ;
    END
  END o[89]
  PIN o[8]
    DIRECTION OUTPUT ;
    USE SIGNAL ;
    PORT
      LAYER M4 ;
        RECT  0 31.536 0.084 31.56 ;
    END
  END o[8]
  PIN o[90]
    DIRECTION OUTPUT ;
    USE SIGNAL ;
    PORT
      LAYER M4 ;
        RECT  0 59.376 0.084 59.4 ;
    END
  END o[90]
  PIN o[91]
    DIRECTION OUTPUT ;
    USE SIGNAL ;
    PORT
      LAYER M4 ;
        RECT  0 59.472 0.084 59.496 ;
    END
  END o[91]
  PIN o[92]
    DIRECTION OUTPUT ;
    USE SIGNAL ;
    PORT
      LAYER M4 ;
        RECT  0 59.568 0.084 59.592 ;
    END
  END o[92]
  PIN o[93]
    DIRECTION OUTPUT ;
    USE SIGNAL ;
    PORT
      LAYER M4 ;
        RECT  0 59.664 0.084 59.688 ;
    END
  END o[93]
  PIN o[94]
    DIRECTION OUTPUT ;
    USE SIGNAL ;
    PORT
      LAYER M4 ;
        RECT  0 68.976 0.084 69 ;
    END
  END o[94]
  PIN o[95]
    DIRECTION OUTPUT ;
    USE SIGNAL ;
    PORT
      LAYER M4 ;
        RECT  0 69.072 0.084 69.096 ;
    END
  END o[95]
  PIN o[96]
    DIRECTION OUTPUT ;
    USE SIGNAL ;
    PORT
      LAYER M4 ;
        RECT  0 69.168 0.084 69.192 ;
    END
  END o[96]
  PIN o[97]
    DIRECTION OUTPUT ;
    USE SIGNAL ;
    PORT
      LAYER M4 ;
        RECT  0 69.264 0.084 69.288 ;
    END
  END o[97]
  PIN o[98]
    DIRECTION OUTPUT ;
    USE SIGNAL ;
    PORT
      LAYER M4 ;
        RECT  0 69.36 0.084 69.384 ;
    END
  END o[98]
  PIN o[99]
    DIRECTION OUTPUT ;
    USE SIGNAL ;
    PORT
      LAYER M4 ;
        RECT  0 69.456 0.084 69.48 ;
    END
  END o[99]
  PIN o[9]
    DIRECTION OUTPUT ;
    USE SIGNAL ;
    PORT
      LAYER M4 ;
        RECT  0 31.632 0.084 31.656 ;
    END
  END o[9]
  PIN rs
    DIRECTION INPUT ;
    USE SIGNAL ;
    PORT
      LAYER M3 ;
        RECT  16.38 95.003 16.398 95.04 ;
    END
  END rs
  PIN VDD
    DIRECTION INOUT ;
    USE POWER ;
    PORT
      LAYER M5 ;
        RECT  34.992 2.151 35.112 92.889 ;
        RECT  32.292 2.151 32.412 92.889 ;
        RECT  29.592 2.151 29.712 92.889 ;
        RECT  26.892 2.151 27.012 92.889 ;
        RECT  24.192 2.151 24.312 92.889 ;
        RECT  21.492 2.151 21.612 92.889 ;
        RECT  18.792 2.151 18.912 92.889 ;
        RECT  16.092 2.151 16.212 92.889 ;
        RECT  13.392 2.151 13.512 92.889 ;
        RECT  10.692 2.151 10.812 92.889 ;
        RECT  7.992 2.151 8.112 92.889 ;
        RECT  5.292 2.151 5.412 92.889 ;
        RECT  2.592 2.151 2.712 92.889 ;
    END
  END VDD
  PIN VSS
    DIRECTION INOUT ;
    USE GROUND ;
    PORT
      LAYER M5 ;
        RECT  34.8 2.137 34.92 92.903 ;
        RECT  32.1 2.137 32.22 92.903 ;
        RECT  29.4 2.137 29.52 92.903 ;
        RECT  26.7 2.137 26.82 92.903 ;
        RECT  24 2.137 24.12 92.903 ;
        RECT  21.3 2.137 21.42 92.903 ;
        RECT  18.6 2.137 18.72 92.903 ;
        RECT  15.9 2.137 16.02 92.903 ;
        RECT  13.2 2.137 13.32 92.903 ;
        RECT  10.5 2.137 10.62 92.903 ;
        RECT  7.8 2.137 7.92 92.903 ;
        RECT  5.1 2.137 5.22 92.903 ;
        RECT  2.4 2.137 2.52 92.903 ;
    END
  END VSS
  OBS
    LAYER RVTN ;
     RECT  2.16 2.16 36.72 2.295 ;
     RECT  2.16 2.565 36.72 2.835 ;
     RECT  2.16 3.105 36.72 3.375 ;
     RECT  2.16 3.645 36.72 3.915 ;
     RECT  2.16 4.185 36.72 4.455 ;
     RECT  2.16 4.725 36.72 4.995 ;
     RECT  2.16 5.265 36.72 5.535 ;
     RECT  2.16 5.805 36.72 6.075 ;
     RECT  2.16 6.345 36.72 6.615 ;
     RECT  2.16 6.885 36.72 7.155 ;
     RECT  2.16 7.425 36.72 7.695 ;
     RECT  2.16 7.965 36.72 8.235 ;
     RECT  2.16 8.505 36.72 8.775 ;
     RECT  2.16 9.045 36.72 9.315 ;
     RECT  2.16 9.585 36.72 9.855 ;
     RECT  2.16 10.125 36.72 10.395 ;
     RECT  2.16 10.665 36.72 10.935 ;
     RECT  2.16 11.205 36.72 11.475 ;
     RECT  2.16 11.745 36.72 12.015 ;
     RECT  2.16 12.285 36.72 12.555 ;
     RECT  2.16 12.825 36.72 13.095 ;
     RECT  2.16 13.365 36.72 13.635 ;
     RECT  2.16 13.905 36.72 14.175 ;
     RECT  2.16 14.445 36.72 14.715 ;
     RECT  2.16 14.985 36.72 15.255 ;
     RECT  2.16 15.525 36.72 15.795 ;
     RECT  2.16 16.065 36.72 16.335 ;
     RECT  2.16 16.605 36.72 16.875 ;
     RECT  2.16 17.145 36.72 17.415 ;
     RECT  2.16 17.685 36.72 17.955 ;
     RECT  2.16 18.225 36.72 18.495 ;
     RECT  2.16 18.765 36.72 19.035 ;
     RECT  2.16 19.305 36.72 19.575 ;
     RECT  2.16 19.845 36.72 20.115 ;
     RECT  2.16 20.385 36.72 20.655 ;
     RECT  2.16 20.925 36.72 21.195 ;
     RECT  2.16 21.465 36.72 21.735 ;
     RECT  2.16 22.005 36.72 22.275 ;
     RECT  2.16 22.545 36.72 22.815 ;
     RECT  2.16 23.085 36.72 23.355 ;
     RECT  2.16 23.625 36.72 23.895 ;
     RECT  2.16 24.165 36.72 24.435 ;
     RECT  2.16 24.705 36.72 24.975 ;
     RECT  2.16 25.245 36.72 25.515 ;
     RECT  2.16 25.785 36.72 26.055 ;
     RECT  2.16 26.325 36.72 26.595 ;
     RECT  2.16 26.865 36.72 27.135 ;
     RECT  2.16 27.405 36.72 27.675 ;
     RECT  2.16 27.945 36.72 28.215 ;
     RECT  2.16 28.485 36.72 28.755 ;
     RECT  2.16 29.025 36.72 29.295 ;
     RECT  2.16 29.565 36.72 29.835 ;
     RECT  2.16 30.105 36.72 30.375 ;
     RECT  2.16 30.645 36.72 30.915 ;
     RECT  2.16 31.185 36.72 31.455 ;
     RECT  2.16 31.725 36.72 31.995 ;
     RECT  2.16 32.265 36.72 32.535 ;
     RECT  2.16 32.805 36.72 33.075 ;
     RECT  2.16 33.345 36.72 33.615 ;
     RECT  2.16 33.885 36.72 34.155 ;
     RECT  2.16 34.425 36.72 34.695 ;
     RECT  2.16 34.965 36.72 35.235 ;
     RECT  2.16 35.505 36.72 35.775 ;
     RECT  2.16 36.045 36.72 36.315 ;
     RECT  2.16 36.585 36.72 36.855 ;
     RECT  2.16 37.125 36.72 37.395 ;
     RECT  2.16 37.665 36.72 37.935 ;
     RECT  2.16 38.205 36.72 38.475 ;
     RECT  2.16 38.745 36.72 39.015 ;
     RECT  2.16 39.285 36.72 39.555 ;
     RECT  2.16 39.825 36.72 40.095 ;
     RECT  2.16 40.365 36.72 40.635 ;
     RECT  2.16 40.905 36.72 41.175 ;
     RECT  2.16 41.445 36.72 41.715 ;
     RECT  2.16 41.985 36.72 42.255 ;
     RECT  2.16 42.525 36.72 42.795 ;
     RECT  2.16 43.065 36.72 43.335 ;
     RECT  2.16 43.605 36.72 43.875 ;
     RECT  2.16 44.145 36.72 44.415 ;
     RECT  2.16 44.685 36.72 44.955 ;
     RECT  2.16 45.225 36.72 45.495 ;
     RECT  2.16 45.765 36.72 46.035 ;
     RECT  2.16 46.305 36.72 46.575 ;
     RECT  2.16 46.845 36.72 47.115 ;
     RECT  2.16 47.385 36.72 47.655 ;
     RECT  2.16 47.925 36.72 48.195 ;
     RECT  2.16 48.465 36.72 48.735 ;
     RECT  2.16 49.005 36.72 49.275 ;
     RECT  2.16 49.545 36.72 49.815 ;
     RECT  2.16 50.085 36.72 50.355 ;
     RECT  2.16 50.625 36.72 50.895 ;
     RECT  2.16 51.165 36.72 51.435 ;
     RECT  2.16 51.705 36.72 51.975 ;
     RECT  2.16 52.245 36.72 52.515 ;
     RECT  2.16 52.785 36.72 53.055 ;
     RECT  2.16 53.325 36.72 53.595 ;
     RECT  2.16 53.865 36.72 54.135 ;
     RECT  2.16 54.405 36.72 54.675 ;
     RECT  2.16 54.945 36.72 55.215 ;
     RECT  2.16 55.485 36.72 55.755 ;
     RECT  2.16 56.025 36.72 56.295 ;
     RECT  2.16 56.565 36.72 56.835 ;
     RECT  2.16 57.105 36.72 57.375 ;
     RECT  2.16 57.645 36.72 57.915 ;
     RECT  2.16 58.185 36.72 58.455 ;
     RECT  2.16 58.725 36.72 58.995 ;
     RECT  2.16 59.265 36.72 59.535 ;
     RECT  2.16 59.805 36.72 60.075 ;
     RECT  2.16 60.345 36.72 60.615 ;
     RECT  2.16 60.885 36.72 61.155 ;
     RECT  2.16 61.425 36.72 61.695 ;
     RECT  2.16 61.965 36.72 62.235 ;
     RECT  2.16 62.505 36.72 62.775 ;
     RECT  2.16 63.045 36.72 63.315 ;
     RECT  2.16 63.585 36.72 63.855 ;
     RECT  2.16 64.125 36.72 64.395 ;
     RECT  2.16 64.665 36.72 64.935 ;
     RECT  2.16 65.205 36.72 65.475 ;
     RECT  2.16 65.745 36.72 66.015 ;
     RECT  2.16 66.285 36.72 66.555 ;
     RECT  2.16 66.825 36.72 67.095 ;
     RECT  2.16 67.365 36.72 67.635 ;
     RECT  2.16 67.905 36.72 68.175 ;
     RECT  2.16 68.445 36.72 68.715 ;
     RECT  2.16 68.985 36.72 69.255 ;
     RECT  2.16 69.525 36.72 69.795 ;
     RECT  2.16 70.065 36.72 70.335 ;
     RECT  2.16 70.605 36.72 70.875 ;
     RECT  2.16 71.145 36.72 71.415 ;
     RECT  2.16 71.685 36.72 71.955 ;
     RECT  2.16 72.225 36.72 72.495 ;
     RECT  2.16 72.765 36.72 73.035 ;
     RECT  2.16 73.305 36.72 73.575 ;
     RECT  2.16 73.845 36.72 74.115 ;
     RECT  2.16 74.385 36.72 74.655 ;
     RECT  2.16 74.925 36.72 75.195 ;
     RECT  2.16 75.465 36.72 75.735 ;
     RECT  2.16 76.005 36.72 76.275 ;
     RECT  2.16 76.545 36.72 76.815 ;
     RECT  2.16 77.085 36.72 77.355 ;
     RECT  2.16 77.625 36.72 77.895 ;
     RECT  2.16 78.165 36.72 78.435 ;
     RECT  2.16 78.705 36.72 78.975 ;
     RECT  2.16 79.245 36.72 79.515 ;
     RECT  2.16 79.785 36.72 80.055 ;
     RECT  2.16 80.325 36.72 80.595 ;
     RECT  2.16 80.865 36.72 81.135 ;
     RECT  2.16 81.405 36.72 81.675 ;
     RECT  2.16 81.945 36.72 82.215 ;
     RECT  2.16 82.485 36.72 82.755 ;
     RECT  2.16 83.025 36.72 83.295 ;
     RECT  2.16 83.565 36.72 83.835 ;
     RECT  2.16 84.105 36.72 84.375 ;
     RECT  2.16 84.645 36.72 84.915 ;
     RECT  2.16 85.185 36.72 85.455 ;
     RECT  2.16 85.725 36.72 85.995 ;
     RECT  2.16 86.265 36.72 86.535 ;
     RECT  2.16 86.805 36.72 87.075 ;
     RECT  2.16 87.345 36.72 87.615 ;
     RECT  2.16 87.885 36.72 88.155 ;
     RECT  2.16 88.425 36.72 88.695 ;
     RECT  2.16 88.965 36.72 89.235 ;
     RECT  2.16 89.505 36.72 89.775 ;
     RECT  2.16 90.045 36.72 90.315 ;
     RECT  2.16 90.585 36.72 90.855 ;
     RECT  2.16 91.125 36.72 91.395 ;
     RECT  2.16 91.665 36.72 91.935 ;
     RECT  2.16 92.205 36.72 92.475 ;
     RECT  2.16 92.745 36.72 92.88 ;
    LAYER RVTP ;
     RECT  2.16 2.295 36.72 2.565 ;
     RECT  2.16 2.835 36.72 3.105 ;
     RECT  2.16 3.375 36.72 3.645 ;
     RECT  2.16 3.915 36.72 4.185 ;
     RECT  2.16 4.455 36.72 4.725 ;
     RECT  2.16 4.995 36.72 5.265 ;
     RECT  2.16 5.535 36.72 5.805 ;
     RECT  2.16 6.075 36.72 6.345 ;
     RECT  2.16 6.615 36.72 6.885 ;
     RECT  2.16 7.155 36.72 7.425 ;
     RECT  2.16 7.695 36.72 7.965 ;
     RECT  2.16 8.235 36.72 8.505 ;
     RECT  2.16 8.775 36.72 9.045 ;
     RECT  2.16 9.315 36.72 9.585 ;
     RECT  2.16 9.855 36.72 10.125 ;
     RECT  2.16 10.395 36.72 10.665 ;
     RECT  2.16 10.935 36.72 11.205 ;
     RECT  2.16 11.475 36.72 11.745 ;
     RECT  2.16 12.015 36.72 12.285 ;
     RECT  2.16 12.555 36.72 12.825 ;
     RECT  2.16 13.095 36.72 13.365 ;
     RECT  2.16 13.635 36.72 13.905 ;
     RECT  2.16 14.175 36.72 14.445 ;
     RECT  2.16 14.715 36.72 14.985 ;
     RECT  2.16 15.255 36.72 15.525 ;
     RECT  2.16 15.795 36.72 16.065 ;
     RECT  2.16 16.335 36.72 16.605 ;
     RECT  2.16 16.875 36.72 17.145 ;
     RECT  2.16 17.415 36.72 17.685 ;
     RECT  2.16 17.955 36.72 18.225 ;
     RECT  2.16 18.495 36.72 18.765 ;
     RECT  2.16 19.035 36.72 19.305 ;
     RECT  2.16 19.575 36.72 19.845 ;
     RECT  2.16 20.115 36.72 20.385 ;
     RECT  2.16 20.655 36.72 20.925 ;
     RECT  2.16 21.195 36.72 21.465 ;
     RECT  2.16 21.735 36.72 22.005 ;
     RECT  2.16 22.275 36.72 22.545 ;
     RECT  2.16 22.815 36.72 23.085 ;
     RECT  2.16 23.355 36.72 23.625 ;
     RECT  2.16 23.895 36.72 24.165 ;
     RECT  2.16 24.435 36.72 24.705 ;
     RECT  2.16 24.975 36.72 25.245 ;
     RECT  2.16 25.515 36.72 25.785 ;
     RECT  2.16 26.055 36.72 26.325 ;
     RECT  2.16 26.595 36.72 26.865 ;
     RECT  2.16 27.135 36.72 27.405 ;
     RECT  2.16 27.675 36.72 27.945 ;
     RECT  2.16 28.215 36.72 28.485 ;
     RECT  2.16 28.755 36.72 29.025 ;
     RECT  2.16 29.295 36.72 29.565 ;
     RECT  2.16 29.835 36.72 30.105 ;
     RECT  2.16 30.375 36.72 30.645 ;
     RECT  2.16 30.915 36.72 31.185 ;
     RECT  2.16 31.455 36.72 31.725 ;
     RECT  2.16 31.995 36.72 32.265 ;
     RECT  2.16 32.535 36.72 32.805 ;
     RECT  2.16 33.075 36.72 33.345 ;
     RECT  2.16 33.615 36.72 33.885 ;
     RECT  2.16 34.155 36.72 34.425 ;
     RECT  2.16 34.695 36.72 34.965 ;
     RECT  2.16 35.235 36.72 35.505 ;
     RECT  2.16 35.775 36.72 36.045 ;
     RECT  2.16 36.315 36.72 36.585 ;
     RECT  2.16 36.855 36.72 37.125 ;
     RECT  2.16 37.395 36.72 37.665 ;
     RECT  2.16 37.935 36.72 38.205 ;
     RECT  2.16 38.475 36.72 38.745 ;
     RECT  2.16 39.015 36.72 39.285 ;
     RECT  2.16 39.555 36.72 39.825 ;
     RECT  2.16 40.095 36.72 40.365 ;
     RECT  2.16 40.635 36.72 40.905 ;
     RECT  2.16 41.175 36.72 41.445 ;
     RECT  2.16 41.715 36.72 41.985 ;
     RECT  2.16 42.255 36.72 42.525 ;
     RECT  2.16 42.795 36.72 43.065 ;
     RECT  2.16 43.335 36.72 43.605 ;
     RECT  2.16 43.875 36.72 44.145 ;
     RECT  2.16 44.415 36.72 44.685 ;
     RECT  2.16 44.955 36.72 45.225 ;
     RECT  2.16 45.495 36.72 45.765 ;
     RECT  2.16 46.035 36.72 46.305 ;
     RECT  2.16 46.575 36.72 46.845 ;
     RECT  2.16 47.115 36.72 47.385 ;
     RECT  2.16 47.655 36.72 47.925 ;
     RECT  2.16 48.195 36.72 48.465 ;
     RECT  2.16 48.735 36.72 49.005 ;
     RECT  2.16 49.275 36.72 49.545 ;
     RECT  2.16 49.815 36.72 50.085 ;
     RECT  2.16 50.355 36.72 50.625 ;
     RECT  2.16 50.895 36.72 51.165 ;
     RECT  2.16 51.435 36.72 51.705 ;
     RECT  2.16 51.975 36.72 52.245 ;
     RECT  2.16 52.515 36.72 52.785 ;
     RECT  2.16 53.055 36.72 53.325 ;
     RECT  2.16 53.595 36.72 53.865 ;
     RECT  2.16 54.135 36.72 54.405 ;
     RECT  2.16 54.675 36.72 54.945 ;
     RECT  2.16 55.215 36.72 55.485 ;
     RECT  2.16 55.755 36.72 56.025 ;
     RECT  2.16 56.295 36.72 56.565 ;
     RECT  2.16 56.835 36.72 57.105 ;
     RECT  2.16 57.375 36.72 57.645 ;
     RECT  2.16 57.915 36.72 58.185 ;
     RECT  2.16 58.455 36.72 58.725 ;
     RECT  2.16 58.995 36.72 59.265 ;
     RECT  2.16 59.535 36.72 59.805 ;
     RECT  2.16 60.075 36.72 60.345 ;
     RECT  2.16 60.615 36.72 60.885 ;
     RECT  2.16 61.155 36.72 61.425 ;
     RECT  2.16 61.695 36.72 61.965 ;
     RECT  2.16 62.235 36.72 62.505 ;
     RECT  2.16 62.775 36.72 63.045 ;
     RECT  2.16 63.315 36.72 63.585 ;
     RECT  2.16 63.855 36.72 64.125 ;
     RECT  2.16 64.395 36.72 64.665 ;
     RECT  2.16 64.935 36.72 65.205 ;
     RECT  2.16 65.475 36.72 65.745 ;
     RECT  2.16 66.015 36.72 66.285 ;
     RECT  2.16 66.555 36.72 66.825 ;
     RECT  2.16 67.095 36.72 67.365 ;
     RECT  2.16 67.635 36.72 67.905 ;
     RECT  2.16 68.175 36.72 68.445 ;
     RECT  2.16 68.715 36.72 68.985 ;
     RECT  2.16 69.255 36.72 69.525 ;
     RECT  2.16 69.795 36.72 70.065 ;
     RECT  2.16 70.335 36.72 70.605 ;
     RECT  2.16 70.875 36.72 71.145 ;
     RECT  2.16 71.415 36.72 71.685 ;
     RECT  2.16 71.955 36.72 72.225 ;
     RECT  2.16 72.495 36.72 72.765 ;
     RECT  2.16 73.035 36.72 73.305 ;
     RECT  2.16 73.575 36.72 73.845 ;
     RECT  2.16 74.115 36.72 74.385 ;
     RECT  2.16 74.655 36.72 74.925 ;
     RECT  2.16 75.195 36.72 75.465 ;
     RECT  2.16 75.735 36.72 76.005 ;
     RECT  2.16 76.275 36.72 76.545 ;
     RECT  2.16 76.815 36.72 77.085 ;
     RECT  2.16 77.355 36.72 77.625 ;
     RECT  2.16 77.895 36.72 78.165 ;
     RECT  2.16 78.435 36.72 78.705 ;
     RECT  2.16 78.975 36.72 79.245 ;
     RECT  2.16 79.515 36.72 79.785 ;
     RECT  2.16 80.055 36.72 80.325 ;
     RECT  2.16 80.595 36.72 80.865 ;
     RECT  2.16 81.135 36.72 81.405 ;
     RECT  2.16 81.675 36.72 81.945 ;
     RECT  2.16 82.215 36.72 82.485 ;
     RECT  2.16 82.755 36.72 83.025 ;
     RECT  2.16 83.295 36.72 83.565 ;
     RECT  2.16 83.835 36.72 84.105 ;
     RECT  2.16 84.375 36.72 84.645 ;
     RECT  2.16 84.915 36.72 85.185 ;
     RECT  2.16 85.455 36.72 85.725 ;
     RECT  2.16 85.995 36.72 86.265 ;
     RECT  2.16 86.535 36.72 86.805 ;
     RECT  2.16 87.075 36.72 87.345 ;
     RECT  2.16 87.615 36.72 87.885 ;
     RECT  2.16 88.155 36.72 88.425 ;
     RECT  2.16 88.695 36.72 88.965 ;
     RECT  2.16 89.235 36.72 89.505 ;
     RECT  2.16 89.775 36.72 90.045 ;
     RECT  2.16 90.315 36.72 90.585 ;
     RECT  2.16 90.855 36.72 91.125 ;
     RECT  2.16 91.395 36.72 91.665 ;
     RECT  2.16 91.935 36.72 92.205 ;
     RECT  2.16 92.475 36.72 92.745 ;
    LAYER M1 ;
     RECT  2.16 2.151 36.72 92.889 ;
    LAYER M2 ;
     RECT  0.031 50.526 0.103 50.544 ;
     RECT  0.031 51.48 0.103 51.498 ;
     RECT  0.103 50.364 0.131 51.498 ;
     RECT  0.103 4.626 0.139 4.644 ;
     RECT  0.103 22.176 0.139 22.194 ;
     RECT  0.103 27.306 0.139 28.44 ;
     RECT  0.103 68.922 0.139 69.246 ;
     RECT  0.103 48.708 0.175 49.464 ;
     RECT  0.103 72.936 0.175 74.034 ;
     RECT  0.103 30.42 0.203 30.978 ;
     RECT  0.103 39.87 0.203 39.888 ;
     RECT  0.103 47.052 0.203 47.07 ;
     RECT  0.103 81.882 0.203 81.9 ;
     RECT  0.139 27.036 0.211 28.44 ;
     RECT  0.103 62.514 0.211 62.532 ;
     RECT  0.139 68.922 0.211 69.444 ;
     RECT  0.103 39.024 0.239 39.042 ;
     RECT  0.103 45.198 0.239 45.216 ;
     RECT  0.103 10.521 0.347 10.62 ;
     RECT  0.203 30.42 0.383 30.438 ;
     RECT  0.131 50.364 0.383 50.814 ;
     RECT  0.211 80.028 0.499 80.046 ;
     RECT  0.103 82.656 0.499 82.674 ;
     RECT  0.499 6.048 0.535 6.066 ;
     RECT  0.499 10.296 0.535 10.314 ;
     RECT  0.103 12.996 0.535 13.014 ;
     RECT  0.103 18.126 0.535 18.792 ;
     RECT  0.211 26.946 0.535 28.44 ;
     RECT  0.499 38.178 0.535 38.196 ;
     RECT  0.031 42.498 0.535 42.786 ;
     RECT  0.103 56.196 0.535 56.214 ;
     RECT  0.211 62.514 0.535 62.694 ;
     RECT  0.211 68.922 0.535 70.092 ;
     RECT  0.175 72.666 0.535 74.034 ;
     RECT  0.499 80.028 0.535 80.352 ;
     RECT  0.499 82.656 0.535 83.124 ;
     RECT  0.103 84.816 0.535 84.834 ;
     RECT  0.535 42.498 1.147 43.128 ;
     RECT  0.499 43.884 1.147 43.902 ;
     RECT  0.535 26.946 1.175 28.944 ;
     RECT  1.147 42.336 1.175 43.128 ;
     RECT  1.147 43.884 1.175 43.974 ;
     RECT  0.535 72.036 1.183 74.034 ;
     RECT  0.139 4.626 2.16 5.094 ;
     RECT  0.535 6.048 2.16 6.372 ;
     RECT  0.499 7.668 2.16 7.686 ;
     RECT  0.535 9.594 2.16 10.314 ;
     RECT  0.463 11.214 2.16 11.232 ;
     RECT  0.535 12.294 2.16 13.014 ;
     RECT  0.535 17.928 2.16 19.296 ;
     RECT  0.139 22.176 2.16 22.608 ;
     RECT  1.175 26.946 2.16 28.134 ;
     RECT  1.175 28.926 2.16 28.944 ;
     RECT  0.535 31.428 2.16 31.446 ;
     RECT  0.103 32.436 2.16 33.066 ;
     RECT  0.535 37.368 2.16 38.7 ;
     RECT  0.535 39.798 2.16 39.816 ;
     RECT  1.175 42.336 2.16 42.354 ;
     RECT  1.175 43.11 2.16 43.128 ;
     RECT  1.175 43.956 2.16 43.974 ;
     RECT  0.535 45.468 2.16 45.486 ;
     RECT  0.175 48.636 2.16 49.464 ;
     RECT  0.383 50.526 2.16 50.814 ;
     RECT  0.535 52.254 2.16 52.272 ;
     RECT  0.535 55.656 2.16 56.214 ;
     RECT  0.103 58.086 2.16 58.104 ;
     RECT  0.535 62.514 2.16 64.152 ;
     RECT  2.155 64.98 2.16 64.998 ;
     RECT  0.535 68.886 2.16 70.092 ;
     RECT  1.183 71.964 2.16 74.034 ;
     RECT  0.535 78.606 2.16 78.624 ;
     RECT  0.535 79.686 2.16 80.352 ;
     RECT  0.535 82.188 2.16 83.124 ;
     RECT  0.535 84.186 2.16 84.834 ;
     RECT  0.103 85.896 2.16 86.634 ;
     RECT  16.375 94.986 16.511 95.004 ;
     RECT  2.16 2.151 20.299 92.889 ;
     RECT  20.299 2.106 20.471 92.889 ;
     RECT  20.471 2.151 22.747 92.889 ;
     RECT  22.747 2.106 23.891 92.889 ;
     RECT  23.891 2.151 36.72 92.889 ;
     RECT  36.72 63.828 36.995 67.428 ;
     RECT  36.72 27.18 37.031 38.736 ;
     RECT  36.72 68.382 37.031 88.344 ;
     RECT  36.72 89.316 37.031 90.414 ;
     RECT  37.031 35.82 37.067 38.736 ;
     RECT  37.031 68.382 37.067 84.708 ;
     RECT  37.031 89.478 37.067 90.414 ;
     RECT  36.72 4.464 37.103 18.72 ;
     RECT  37.103 4.464 37.319 6.804 ;
     RECT  36.72 21.816 37.319 25.812 ;
     RECT  36.72 41.49 37.319 41.508 ;
     RECT  37.103 7.74 37.571 18.72 ;
     RECT  36.72 57.078 37.571 58.824 ;
     RECT  37.571 7.74 37.607 16.974 ;
     RECT  37.571 17.73 37.607 18.72 ;
     RECT  37.031 27.18 37.607 34.956 ;
     RECT  36.72 52.56 37.607 56.016 ;
     RECT  36.995 63.828 37.607 66.618 ;
     RECT  37.067 68.382 37.607 78.624 ;
     RECT  37.067 79.524 37.607 84.366 ;
     RECT  37.031 85.536 37.607 88.344 ;
     RECT  37.319 4.5 37.643 6.804 ;
     RECT  37.607 7.74 37.643 15.858 ;
     RECT  37.607 27.18 37.643 32.292 ;
     RECT  37.607 52.56 37.643 54.972 ;
     RECT  37.607 68.382 37.643 70.596 ;
     RECT  37.607 79.524 37.643 81.126 ;
     RECT  37.607 86.85 37.643 88.344 ;
     RECT  37.643 5.85 37.679 6.804 ;
     RECT  37.643 79.524 37.679 80.964 ;
     RECT  37.319 21.816 37.895 25.038 ;
     RECT  36.72 62.946 37.895 62.964 ;
     RECT  37.607 71.46 37.895 78.624 ;
     RECT  37.679 80.64 37.895 80.964 ;
     RECT  36.72 46.08 38.083 51.804 ;
     RECT  37.643 7.74 38.119 8.496 ;
     RECT  37.607 55.764 38.119 56.016 ;
     RECT  36.72 19.584 38.155 20.448 ;
     RECT  37.643 4.5 38.183 5.058 ;
     RECT  37.643 9.288 38.183 15.858 ;
     RECT  37.643 27.18 38.183 31.248 ;
     RECT  36.72 43.776 38.183 45.018 ;
     RECT  38.083 46.08 38.183 51.849 ;
     RECT  37.067 89.55 38.183 90.414 ;
     RECT  38.183 4.5 38.219 4.986 ;
     RECT  38.183 9.288 38.219 10.764 ;
     RECT  38.183 11.52 38.219 15.858 ;
     RECT  37.607 17.73 38.219 18.324 ;
     RECT  38.183 27.18 38.219 28.476 ;
     RECT  38.183 29.61 38.219 31.248 ;
     RECT  37.607 33.048 38.219 34.524 ;
     RECT  37.067 36.558 38.219 38.736 ;
     RECT  38.119 55.764 38.219 56.25 ;
     RECT  37.571 57.078 38.219 57.708 ;
     RECT  37.607 63.828 38.219 65.538 ;
     RECT  37.607 66.6 38.219 66.618 ;
     RECT  37.895 80.91 38.219 80.964 ;
     RECT  37.607 81.918 38.219 84.366 ;
     RECT  37.643 87.084 38.219 88.344 ;
     RECT  38.183 89.55 38.219 89.604 ;
     RECT  38.219 4.5 38.255 4.554 ;
     RECT  38.119 7.632 38.255 8.496 ;
     RECT  38.219 11.52 38.255 13.464 ;
     RECT  38.155 19.584 38.255 20.529 ;
     RECT  37.643 32.166 38.255 32.184 ;
     RECT  38.219 36.558 38.255 37.584 ;
     RECT  38.183 43.776 38.255 44.784 ;
     RECT  38.183 46.08 38.255 51.804 ;
     RECT  37.643 52.596 38.255 54.972 ;
     RECT  38.219 57.114 38.255 57.708 ;
     RECT  37.895 71.46 38.255 77.454 ;
     RECT  37.895 21.816 38.291 24.534 ;
     RECT  38.219 29.61 38.291 30.672 ;
     RECT  38.219 33.156 38.291 34.524 ;
     RECT  38.255 46.08 38.291 49.104 ;
     RECT  38.255 50.094 38.291 51.804 ;
     RECT  37.679 79.524 38.291 79.659 ;
     RECT  38.219 81.954 38.291 84.366 ;
     RECT  38.255 11.556 38.327 13.464 ;
     RECT  38.291 33.156 38.327 33.408 ;
     RECT  38.255 57.15 38.327 57.708 ;
     RECT  38.291 21.816 38.363 22.914 ;
     RECT  38.363 22.716 38.435 22.914 ;
     RECT  37.643 68.382 38.515 70.398 ;
     RECT  38.219 63.828 38.543 63.846 ;
     RECT  38.291 79.524 38.543 79.542 ;
     RECT  38.219 89.55 38.551 89.568 ;
     RECT  38.255 37.098 38.579 37.584 ;
     RECT  38.219 64.872 38.579 65.538 ;
     RECT  37.679 6.12 38.615 6.804 ;
     RECT  38.255 19.584 38.615 20.034 ;
     RECT  38.255 71.46 38.615 73.872 ;
     RECT  38.443 36.126 38.623 36.342 ;
     RECT  37.895 78.21 38.623 78.624 ;
     RECT  38.255 7.632 38.651 8.379 ;
     RECT  38.219 14.652 38.651 15.858 ;
     RECT  38.291 23.67 38.651 24.534 ;
     RECT  38.219 27.18 38.651 27.666 ;
     RECT  38.291 50.13 38.651 51.804 ;
     RECT  36.72 59.886 38.651 61.488 ;
     RECT  38.515 68.382 38.651 70.704 ;
     RECT  38.615 71.694 38.651 73.872 ;
     RECT  38.255 4.536 38.687 4.554 ;
     RECT  38.291 29.61 38.687 29.628 ;
     RECT  38.327 57.348 38.687 57.708 ;
     RECT  37.571 58.464 38.687 58.824 ;
     RECT  38.291 46.08 38.695 46.908 ;
     RECT  38.651 70.074 38.695 70.704 ;
     RECT  37.607 85.698 38.695 86.094 ;
     RECT  38.219 87.084 38.695 87.876 ;
     RECT  38.551 89.244 38.695 89.568 ;
     RECT  38.327 11.952 38.723 13.464 ;
     RECT  38.363 21.816 38.723 21.834 ;
     RECT  38.327 33.156 38.723 33.264 ;
     RECT  38.291 47.7 38.723 49.104 ;
     RECT  38.687 57.348 38.723 57.672 ;
     RECT  38.651 59.886 38.723 59.904 ;
     RECT  38.579 64.944 38.723 65.538 ;
     RECT  38.651 68.382 38.723 69.318 ;
     RECT  38.255 74.628 38.723 77.454 ;
     RECT  38.695 85.698 38.723 87.876 ;
     RECT  36.72 91.368 38.723 91.386 ;
     RECT  38.623 78.21 38.731 78.696 ;
     RECT  38.615 6.12 38.759 6.138 ;
     RECT  38.723 13.176 38.759 13.464 ;
     RECT  38.651 14.652 38.759 15.588 ;
     RECT  38.219 17.73 38.759 17.946 ;
     RECT  38.615 19.584 38.759 19.602 ;
     RECT  38.435 22.824 38.759 22.914 ;
     RECT  38.291 30.654 38.759 30.672 ;
     RECT  38.623 35.28 38.759 36.342 ;
     RECT  38.579 37.521 38.759 37.584 ;
     RECT  38.255 43.776 38.759 44.442 ;
     RECT  38.723 47.7 38.759 48.258 ;
     RECT  38.651 51.516 38.759 51.804 ;
     RECT  38.255 52.83 38.759 54.972 ;
     RECT  38.723 57.654 38.759 57.672 ;
     RECT  38.723 64.944 38.759 65.43 ;
     RECT  38.723 68.382 38.759 68.814 ;
     RECT  38.651 71.694 38.759 72.288 ;
     RECT  38.651 73.386 38.759 73.872 ;
     RECT  38.291 81.954 38.759 82.548 ;
     RECT  38.723 86.076 38.759 87.876 ;
     RECT  38.291 84.348 38.767 84.366 ;
     RECT  38.651 7.938 38.795 8.379 ;
     RECT  38.219 9.288 38.795 10.386 ;
     RECT  38.723 11.952 38.795 12.348 ;
     RECT  38.759 13.446 38.795 13.464 ;
     RECT  38.759 14.652 38.795 14.778 ;
     RECT  38.759 15.57 38.795 15.588 ;
     RECT  37.607 16.956 38.795 16.974 ;
     RECT  38.759 17.766 38.795 17.946 ;
     RECT  38.651 23.976 38.795 24.534 ;
     RECT  38.651 27.648 38.795 27.666 ;
     RECT  38.291 34.506 38.795 34.524 ;
     RECT  38.219 38.718 38.795 38.736 ;
     RECT  38.695 45.774 38.795 46.908 ;
     RECT  38.759 47.934 38.795 48.258 ;
     RECT  38.651 50.13 38.795 50.616 ;
     RECT  38.759 53.496 38.795 54.972 ;
     RECT  38.687 58.464 38.795 58.482 ;
     RECT  38.695 66.366 38.795 66.384 ;
     RECT  36.995 67.41 38.795 67.428 ;
     RECT  38.695 70.074 38.795 70.794 ;
     RECT  38.759 71.694 38.795 71.874 ;
     RECT  38.759 73.386 38.795 73.404 ;
     RECT  38.723 75.168 38.795 77.454 ;
     RECT  38.219 80.91 38.795 80.928 ;
     RECT  38.759 81.954 38.795 82.512 ;
     RECT  38.291 83.376 38.795 83.394 ;
     RECT  38.759 86.076 38.795 87.714 ;
     RECT  38.695 88.974 38.795 89.568 ;
     RECT  36.72 3.69 38.831 3.708 ;
     RECT  38.795 8.28 38.831 8.379 ;
     RECT  37.319 25.794 38.831 25.812 ;
     RECT  38.731 26.802 38.831 26.82 ;
     RECT  38.795 46.89 38.831 46.908 ;
     RECT  38.795 54.378 38.831 54.702 ;
     RECT  38.219 55.836 38.831 56.169 ;
     RECT  38.731 78.21 38.831 78.768 ;
     RECT  38.767 84.348 38.831 84.474 ;
     RECT  38.795 87.696 38.831 87.714 ;
     RECT  36.72 2.646 38.867 2.664 ;
     RECT  38.831 8.28 38.867 8.298 ;
     RECT  38.795 9.288 38.867 9.306 ;
     RECT  38.795 12.33 38.867 12.348 ;
     RECT  38.795 17.928 38.867 17.946 ;
     RECT  38.795 24.516 38.867 24.534 ;
     RECT  38.219 28.458 38.867 28.476 ;
     RECT  38.723 33.156 38.867 33.174 ;
     RECT  38.759 37.521 38.867 37.539 ;
     RECT  36.72 40.338 38.867 40.356 ;
     RECT  38.759 44.424 38.867 44.442 ;
     RECT  38.831 54.378 38.867 54.396 ;
     RECT  38.831 56.151 38.867 56.169 ;
     RECT  38.651 60.966 38.867 61.488 ;
     RECT  38.759 65.412 38.867 65.43 ;
     RECT  38.759 68.796 38.867 68.814 ;
     RECT  38.795 70.686 38.867 70.794 ;
     RECT  38.795 71.856 38.867 71.874 ;
     RECT  38.795 77.364 38.867 77.382 ;
     RECT  38.795 82.224 38.867 82.242 ;
     RECT  38.831 84.456 38.867 84.474 ;
     RECT  38.183 90.396 38.867 90.414 ;
    LAYER M3 ;
     RECT  23.868 2.101 23.886 2.143 ;
     RECT  7.815 2.143 7.905 2.191 ;
     RECT  10.515 2.143 10.605 2.191 ;
     RECT  15.915 2.143 16.005 2.191 ;
     RECT  20.304 2.101 20.466 2.191 ;
     RECT  21.315 2.143 21.405 2.191 ;
     RECT  22.752 2.101 22.77 2.191 ;
     RECT  23.868 2.143 24.105 2.191 ;
     RECT  26.715 2.143 26.805 2.191 ;
     RECT  32.115 2.143 32.205 2.191 ;
     RECT  2.415 2.143 2.505 2.227 ;
     RECT  5.115 2.143 5.205 2.227 ;
     RECT  5.94 2.191 6.498 2.227 ;
     RECT  7.815 2.191 8.55 2.227 ;
     RECT  10.515 2.191 11.538 2.227 ;
     RECT  13.215 2.143 13.305 2.227 ;
     RECT  29.415 2.143 29.505 2.227 ;
     RECT  32.004 2.191 32.205 2.227 ;
     RECT  5.004 2.227 5.205 2.251 ;
     RECT  5.94 2.227 9.126 2.251 ;
     RECT  17.208 2.191 17.226 2.251 ;
     RECT  32.004 2.227 32.598 2.251 ;
     RECT  13.215 2.227 14.382 2.263 ;
     RECT  15.408 2.191 16.005 2.263 ;
     RECT  16.812 2.251 17.226 2.299 ;
     RECT  23.616 2.191 24.714 2.299 ;
     RECT  16.812 2.299 17.838 2.335 ;
     RECT  18.615 2.143 18.705 2.335 ;
     RECT  26.604 2.191 26.805 2.335 ;
     RECT  27.972 2.191 27.99 2.335 ;
     RECT  23.616 2.299 25.002 2.347 ;
     RECT  4.14 2.191 4.158 2.371 ;
     RECT  10.476 2.227 11.538 2.371 ;
     RECT  13.215 2.263 16.005 2.371 ;
     RECT  16.812 2.335 18.705 2.371 ;
     RECT  19.872 2.191 22.77 2.371 ;
     RECT  23.616 2.347 25.11 2.371 ;
     RECT  27.972 2.335 28.026 2.371 ;
     RECT  12.6 2.371 16.005 2.413 ;
     RECT  16.812 2.371 19.098 2.413 ;
     RECT  26.604 2.335 26.874 2.413 ;
     RECT  34.815 2.143 34.905 2.413 ;
     RECT  10.332 2.371 11.826 2.443 ;
     RECT  12.6 2.413 19.098 2.443 ;
     RECT  26.604 2.413 26.997 2.461 ;
     RECT  5.004 2.251 9.126 2.491 ;
     RECT  3.708 2.371 4.158 2.587 ;
     RECT  19.872 2.371 25.11 2.605 ;
     RECT  31.608 2.251 32.598 2.605 ;
     RECT  19.872 2.605 25.542 2.618 ;
     RECT  26.424 2.461 26.997 2.618 ;
     RECT  2.415 2.227 2.862 2.641 ;
     RECT  3.708 2.587 4.194 2.641 ;
     RECT  5.004 2.491 9.45 2.641 ;
     RECT  10.332 2.443 19.098 2.641 ;
     RECT  19.872 2.618 26.997 2.641 ;
     RECT  27.972 2.371 28.098 2.641 ;
     RECT  29.016 2.227 30.222 2.641 ;
     RECT  31.14 2.605 32.598 2.641 ;
     RECT  2.415 2.641 19.098 2.731 ;
     RECT  19.872 2.641 28.098 2.731 ;
     RECT  28.872 2.641 32.598 2.911 ;
     RECT  2.415 2.731 28.098 3.001 ;
     RECT  28.836 2.911 32.598 3.001 ;
     RECT  2.415 3.001 32.598 3.037 ;
     RECT  33.408 2.911 33.426 3.037 ;
     RECT  36.144 2.605 36.162 3.145 ;
     RECT  2.34 3.037 33.426 3.355 ;
     RECT  36.144 3.145 36.558 3.415 ;
     RECT  36.108 3.415 36.558 3.451 ;
     RECT  2.34 3.355 33.534 3.613 ;
     RECT  38.844 2.641 38.862 3.685 ;
     RECT  2.34 3.613 33.966 3.983 ;
     RECT  36.108 3.451 36.594 3.991 ;
     RECT  2.415 3.983 33.966 4.216 ;
     RECT  34.815 2.413 35.097 4.216 ;
     RECT  35.892 3.991 36.594 4.379 ;
     RECT  38.808 3.685 38.862 4.495 ;
     RECT  38.232 4.495 38.862 4.963 ;
     RECT  38.196 4.963 38.862 5.035 ;
     RECT  0.108 4.621 0.126 5.071 ;
     RECT  2.415 4.216 35.097 5.071 ;
     RECT  35.892 4.379 36.558 5.071 ;
     RECT  37.296 4.459 37.314 5.161 ;
     RECT  38.16 5.035 38.862 5.161 ;
     RECT  0.108 5.071 0.162 5.261 ;
     RECT  2.415 5.071 36.558 5.323 ;
     RECT  0.144 5.261 0.162 5.453 ;
     RECT  0.504 6.043 0.522 6.241 ;
     RECT  0.504 6.241 0.558 6.379 ;
     RECT  2.304 5.323 36.558 6.385 ;
     RECT  37.296 5.161 38.862 6.385 ;
     RECT  0.504 6.379 0.63 6.413 ;
     RECT  0.54 6.413 0.63 6.509 ;
     RECT  2.304 6.385 38.862 6.989 ;
     RECT  2.304 6.989 37.314 7.099 ;
     RECT  1.98 7.099 37.314 7.277 ;
     RECT  2.268 7.277 36.342 7.373 ;
     RECT  37.08 7.277 37.314 7.373 ;
     RECT  0.54 6.509 0.558 7.663 ;
     RECT  38.124 6.989 38.862 7.723 ;
     RECT  0.504 7.663 0.558 7.853 ;
     RECT  2.304 7.373 36.342 8.011 ;
     RECT  0.504 7.853 0.522 8.251 ;
     RECT  38.088 7.723 38.862 8.303 ;
     RECT  38.088 8.303 38.826 8.384 ;
     RECT  2.304 8.011 36.522 8.429 ;
     RECT  37.296 7.373 37.314 8.509 ;
     RECT  38.088 8.384 38.754 8.509 ;
     RECT  0.144 8.251 0.522 8.621 ;
     RECT  0.144 8.621 0.162 9.005 ;
     RECT  2.304 8.429 36.342 9.197 ;
     RECT  2.304 9.197 36.09 9.239 ;
     RECT  1.26 9.163 1.278 9.259 ;
     RECT  37.296 8.509 38.754 9.283 ;
     RECT  1.152 9.259 1.278 9.293 ;
     RECT  37.296 9.283 38.862 9.293 ;
     RECT  1.152 9.293 1.17 9.589 ;
     RECT  0.54 9.589 1.17 10.109 ;
     RECT  37.548 9.293 38.862 10.165 ;
     RECT  2.304 9.239 36.054 10.201 ;
     RECT  37.044 10.165 38.862 10.201 ;
     RECT  2.304 10.201 38.862 10.291 ;
     RECT  0.504 10.291 0.522 10.315 ;
     RECT  2.268 10.291 38.862 10.349 ;
     RECT  0.324 10.315 0.522 10.411 ;
     RECT  0.108 10.411 0.522 10.637 ;
     RECT  2.304 10.349 38.862 11.165 ;
     RECT  0.216 10.637 0.522 11.309 ;
     RECT  2.304 11.165 36.234 11.399 ;
     RECT  2.304 11.399 36.09 11.947 ;
     RECT  0.216 11.309 0.486 11.995 ;
     RECT  2.196 11.947 36.09 12.047 ;
     RECT  37.044 11.165 38.862 12.077 ;
     RECT  0.144 11.995 0.486 12.289 ;
     RECT  2.304 12.047 36.09 12.289 ;
     RECT  37.368 12.077 38.862 12.353 ;
     RECT  37.368 12.353 38.79 12.461 ;
     RECT  2.304 12.289 36.45 12.479 ;
     RECT  0.144 12.289 0.558 12.523 ;
     RECT  0.144 12.523 1.17 12.557 ;
     RECT  1.152 12.557 1.17 12.571 ;
     RECT  1.152 12.571 1.242 12.845 ;
     RECT  1.152 12.845 1.17 12.893 ;
     RECT  37.512 12.461 38.79 12.893 ;
     RECT  0.144 12.557 0.162 12.991 ;
     RECT  0.108 12.991 0.162 13.037 ;
     RECT  0.108 13.037 0.126 13.133 ;
     RECT  2.304 12.479 36.378 13.297 ;
     RECT  2.304 13.297 36.522 13.396 ;
     RECT  37.62 12.893 38.79 13.469 ;
     RECT  2.304 13.396 36.558 13.595 ;
     RECT  37.62 13.469 38.718 13.945 ;
     RECT  0.144 13.771 0.162 13.949 ;
     RECT  37.008 13.945 38.718 13.997 ;
     RECT  0.216 13.963 0.234 14.141 ;
     RECT  2.304 13.595 36.018 14.341 ;
     RECT  37.584 13.997 38.718 14.573 ;
     RECT  38.664 14.573 38.718 14.635 ;
     RECT  2.304 14.341 36.342 14.639 ;
     RECT  37.584 14.573 37.602 14.711 ;
     RECT  2.376 14.639 36.342 14.923 ;
     RECT  2.376 14.923 36.522 15.053 ;
     RECT  38.664 14.635 38.79 15.403 ;
     RECT  2.376 15.053 36.234 15.449 ;
     RECT  38.592 15.403 38.79 15.593 ;
     RECT  38.592 15.593 38.754 15.595 ;
     RECT  37.872 15.595 38.754 15.725 ;
     RECT  36.972 15.565 36.99 15.791 ;
     RECT  37.872 15.725 38.646 15.917 ;
     RECT  37.872 15.917 37.89 15.979 ;
     RECT  2.376 15.449 35.91 16.267 ;
     RECT  38.628 15.917 38.646 16.459 ;
     RECT  2.376 16.267 36.342 16.529 ;
     RECT  37.296 15.979 37.89 16.843 ;
     RECT  38.628 16.459 38.79 16.843 ;
     RECT  37.296 16.843 38.79 17.077 ;
     RECT  37.044 17.077 38.79 17.261 ;
     RECT  37.296 17.261 38.79 17.357 ;
     RECT  2.376 16.529 36.09 17.491 ;
     RECT  2.376 17.491 36.234 17.581 ;
     RECT  38.7 17.357 38.79 17.923 ;
     RECT  2.376 17.581 36.342 17.989 ;
     RECT  2.376 17.989 36.522 18.029 ;
     RECT  0.54 17.923 0.558 18.121 ;
     RECT  37.296 17.357 37.89 18.283 ;
     RECT  38.7 17.923 38.862 18.283 ;
     RECT  2.376 18.029 36.342 18.301 ;
     RECT  2.304 18.301 36.342 18.761 ;
     RECT  0.108 18.121 0.558 18.893 ;
     RECT  2.304 18.761 36.27 18.959 ;
     RECT  0.144 18.893 0.558 19.469 ;
     RECT  0.144 19.469 0.234 19.853 ;
     RECT  0.216 19.853 0.234 19.949 ;
     RECT  2.304 18.959 35.622 20.011 ;
     RECT  2.268 20.011 35.622 20.047 ;
     RECT  2.268 20.047 35.658 20.119 ;
     RECT  2.268 20.119 35.766 20.191 ;
     RECT  2.268 20.191 35.802 20.579 ;
     RECT  2.304 20.579 35.802 20.821 ;
     RECT  2.304 20.821 36.45 20.921 ;
     RECT  0.324 20.971 0.342 21.101 ;
     RECT  0.108 21.163 0.126 21.389 ;
     RECT  2.304 20.921 36.342 21.389 ;
     RECT  2.415 21.389 36.342 22.045 ;
     RECT  37.296 18.283 38.862 22.045 ;
     RECT  2.415 22.045 38.862 22.441 ;
     RECT  2.376 22.441 38.862 22.469 ;
     RECT  0.108 22.171 0.126 22.513 ;
     RECT  2.376 22.469 36.198 22.603 ;
     RECT  0.108 22.513 0.558 22.829 ;
     RECT  0.144 22.829 0.558 22.925 ;
     RECT  0.144 22.925 0.162 23.021 ;
     RECT  2.304 22.603 36.198 23.563 ;
     RECT  2.304 23.563 36.234 23.755 ;
     RECT  2.268 23.755 36.234 24.169 ;
     RECT  2.268 24.169 36.45 24.331 ;
     RECT  2.232 24.331 36.522 24.368 ;
     RECT  2.268 24.368 36.522 24.467 ;
     RECT  37.296 22.469 38.862 24.539 ;
     RECT  37.296 24.539 38.646 24.557 ;
     RECT  2.268 24.467 36.342 24.629 ;
     RECT  38.628 24.557 38.646 24.653 ;
     RECT  37.296 24.557 37.89 25.043 ;
     RECT  37.296 25.043 37.314 25.079 ;
     RECT  2.304 24.629 36.342 25.205 ;
     RECT  2.304 25.205 36.234 25.349 ;
     RECT  2.415 25.349 36.234 26.095 ;
     RECT  2.415 26.095 36.27 26.347 ;
     RECT  2.415 26.347 36.45 26.365 ;
     RECT  2.415 26.365 36.486 26.671 ;
     RECT  38.808 25.789 38.826 26.797 ;
     RECT  38.736 26.797 38.826 26.825 ;
     RECT  2.415 26.671 36.522 26.861 ;
     RECT  0.216 26.941 0.234 27.031 ;
     RECT  0.144 27.031 0.234 27.139 ;
     RECT  38.736 26.825 38.754 27.175 ;
     RECT  2.415 26.861 36.45 27.211 ;
     RECT  0.144 27.139 0.558 27.301 ;
     RECT  0.108 27.301 0.558 27.409 ;
     RECT  2.304 27.211 36.45 27.635 ;
     RECT  38.628 27.175 38.754 27.643 ;
     RECT  0.108 27.409 1.17 27.679 ;
     RECT  2.412 27.635 36.45 27.715 ;
     RECT  0.108 27.679 1.242 27.905 ;
     RECT  38.628 27.643 38.79 27.913 ;
     RECT  38.196 27.913 38.79 28.021 ;
     RECT  2.412 27.715 36.594 28.417 ;
     RECT  0.108 27.905 1.17 28.445 ;
     RECT  37.872 28.021 38.79 28.453 ;
     RECT  0.108 28.445 0.558 28.589 ;
     RECT  0.504 28.589 0.558 28.781 ;
     RECT  2.304 28.417 36.594 28.795 ;
     RECT  2.304 28.795 37.062 28.993 ;
     RECT  37.872 28.453 38.862 28.993 ;
     RECT  0.54 28.781 0.558 29.741 ;
     RECT  0.144 29.899 0.378 30.379 ;
     RECT  0.108 30.379 0.378 30.509 ;
     RECT  2.304 28.993 38.862 31.085 ;
     RECT  0.108 30.509 0.234 31.181 ;
     RECT  2.304 31.085 36.09 31.243 ;
     RECT  0.144 31.181 0.234 31.423 ;
     RECT  0.144 31.423 0.558 31.517 ;
     RECT  2.268 31.243 36.09 31.915 ;
     RECT  1.728 31.915 36.09 31.999 ;
     RECT  1.728 31.999 36.198 32.233 ;
     RECT  37.044 31.085 38.862 32.233 ;
     RECT  0.54 31.517 0.558 32.237 ;
     RECT  1.728 32.233 38.862 32.525 ;
     RECT  1.728 32.525 37.098 32.531 ;
     RECT  2.196 32.531 37.098 32.813 ;
     RECT  37.872 32.525 38.862 32.813 ;
     RECT  2.304 32.813 37.098 32.909 ;
     RECT  0.108 32.431 0.162 33.101 ;
     RECT  38.16 32.813 38.862 33.179 ;
     RECT  38.16 33.179 38.79 33.197 ;
     RECT  0.18 33.307 0.198 33.451 ;
     RECT  2.304 32.909 36.558 33.539 ;
     RECT  0.18 33.451 0.342 33.581 ;
     RECT  2.34 33.539 36.558 33.683 ;
     RECT  2.34 33.683 36.09 33.809 ;
     RECT  38.16 33.197 38.718 34.219 ;
     RECT  38.16 34.219 38.79 34.411 ;
     RECT  37.584 34.411 38.79 34.529 ;
     RECT  2.415 33.809 36.09 34.619 ;
     RECT  37.584 34.529 38.646 34.637 ;
     RECT  37.584 34.637 37.602 34.663 ;
     RECT  2.415 34.619 16.254 34.781 ;
     RECT  16.992 34.619 36.09 34.861 ;
     RECT  37.008 34.663 37.602 35.021 ;
     RECT  16.992 34.861 36.126 35.231 ;
     RECT  38.556 34.637 38.646 35.275 ;
     RECT  2.415 34.781 16.197 35.357 ;
     RECT  16.992 35.231 35.982 35.501 ;
     RECT  16.992 35.501 35.73 35.581 ;
     RECT  3.528 35.357 16.197 35.659 ;
     RECT  16.92 35.581 35.73 35.659 ;
     RECT  38.556 35.275 38.754 35.659 ;
     RECT  3.528 35.659 35.73 35.744 ;
     RECT  38.52 35.659 38.754 36.091 ;
     RECT  37.008 35.021 37.314 36.235 ;
     RECT  38.448 36.091 38.754 36.365 ;
     RECT  2.415 35.357 2.697 36.475 ;
     RECT  3.528 35.744 35.658 36.475 ;
     RECT  37.008 36.235 37.566 36.553 ;
     RECT  38.448 36.365 38.574 36.553 ;
     RECT  37.008 36.553 38.574 36.653 ;
     RECT  2.415 36.475 35.658 36.895 ;
     RECT  2.415 36.895 36.234 36.931 ;
     RECT  2.415 36.931 36.522 37.049 ;
     RECT  2.415 37.049 36.198 37.291 ;
     RECT  2.304 37.291 36.198 37.421 ;
     RECT  37.296 36.653 38.574 37.483 ;
     RECT  37.296 37.483 38.79 37.516 ;
     RECT  2.304 37.421 36.126 37.517 ;
     RECT  0.54 37.363 0.558 37.675 ;
     RECT  0.54 37.675 0.666 37.805 ;
     RECT  0.54 37.805 0.558 38.173 ;
     RECT  37.296 37.516 38.862 38.201 ;
     RECT  2.412 37.517 36.126 38.281 ;
     RECT  38.124 38.201 38.862 38.309 ;
     RECT  0.504 38.173 0.558 38.539 ;
     RECT  38.772 38.309 38.862 38.741 ;
     RECT  2.304 38.281 36.126 38.821 ;
     RECT  0.504 38.539 1.17 38.861 ;
     RECT  2.304 38.821 36.162 38.939 ;
     RECT  0.216 38.875 0.342 39.019 ;
     RECT  0.108 39.019 0.342 39.053 ;
     RECT  0.108 39.053 0.162 39.056 ;
     RECT  2.415 38.939 36.162 39.181 ;
     RECT  2.415 39.181 36.45 39.325 ;
     RECT  1.152 38.861 1.17 39.403 ;
     RECT  2.415 39.325 36.522 39.479 ;
     RECT  1.152 39.403 1.278 39.533 ;
     RECT  2.415 39.479 36.378 39.721 ;
     RECT  2.412 39.721 36.378 39.749 ;
     RECT  0.144 39.056 0.162 39.793 ;
     RECT  1.152 39.533 1.17 39.793 ;
     RECT  0.144 39.793 1.17 39.865 ;
     RECT  2.412 39.749 36.054 39.865 ;
     RECT  0.108 39.865 1.17 39.869 ;
     RECT  0.108 39.869 0.558 39.917 ;
     RECT  0.108 39.917 0.198 40.013 ;
     RECT  0.18 40.013 0.198 40.061 ;
     RECT  2.304 39.865 36.054 40.325 ;
     RECT  38.844 38.741 38.862 40.361 ;
     RECT  2.304 40.325 27.054 40.363 ;
     RECT  2.268 40.363 27.054 40.459 ;
     RECT  27.792 40.325 36.054 40.493 ;
     RECT  2.232 40.459 27.054 40.559 ;
     RECT  27.9 40.493 36.054 40.567 ;
     RECT  3.42 40.559 27.054 40.595 ;
     RECT  27.9 40.567 36.198 40.981 ;
     RECT  2.304 40.559 2.697 41.009 ;
     RECT  3.528 40.595 27.054 41.179 ;
     RECT  3.528 41.179 27.162 41.213 ;
     RECT  5.115 41.213 27.162 41.251 ;
     RECT  27.9 40.981 36.342 41.251 ;
     RECT  2.415 41.009 2.697 41.371 ;
     RECT  3.528 41.213 4.302 41.371 ;
     RECT  37.296 38.201 37.314 41.513 ;
     RECT  5.115 41.251 36.414 41.521 ;
     RECT  2.415 41.371 4.302 41.675 ;
     RECT  3.6 41.675 4.302 41.933 ;
     RECT  5.115 41.521 36.522 41.989 ;
     RECT  3.852 41.933 4.302 42.151 ;
     RECT  5.04 41.989 36.522 42.151 ;
     RECT  1.152 42.331 1.17 42.521 ;
     RECT  0.036 42.493 0.054 42.763 ;
     RECT  3.852 42.151 36.522 42.763 ;
     RECT  0.036 42.763 0.126 42.791 ;
     RECT  0.108 42.791 0.126 43.105 ;
     RECT  2.415 41.675 2.697 43.141 ;
     RECT  3.78 42.763 36.522 43.295 ;
     RECT  3.78 43.295 36.27 43.411 ;
     RECT  2.415 43.141 2.826 43.501 ;
     RECT  38.736 43.771 38.754 43.867 ;
     RECT  0.108 43.105 0.558 43.879 ;
     RECT  3.6 43.411 36.27 44.041 ;
     RECT  3.564 44.041 36.342 44.093 ;
     RECT  38.736 43.867 38.826 44.107 ;
     RECT  38.124 44.107 38.826 44.155 ;
     RECT  2.304 43.501 2.826 44.185 ;
     RECT  3.564 44.093 36.162 44.185 ;
     RECT  38.052 44.155 38.826 44.185 ;
     RECT  0.108 43.879 1.17 44.333 ;
     RECT  2.304 44.185 36.162 44.411 ;
     RECT  37.62 44.185 38.826 44.419 ;
     RECT  0.108 44.333 0.522 44.525 ;
     RECT  1.26 44.587 1.278 44.717 ;
     RECT  0.108 44.525 0.234 45.221 ;
     RECT  2.304 44.411 36.126 45.265 ;
     RECT  37.62 44.419 38.862 45.389 ;
     RECT  0.144 45.221 0.234 45.437 ;
     RECT  0.216 45.437 0.234 45.463 ;
     RECT  0.216 45.463 0.558 45.533 ;
     RECT  2.304 45.265 36.522 45.571 ;
     RECT  2.304 45.571 36.558 45.661 ;
     RECT  0.54 45.533 0.558 45.691 ;
     RECT  2.268 45.661 36.558 45.965 ;
     RECT  2.304 45.965 36.558 46.157 ;
     RECT  0.54 45.691 1.17 46.219 ;
     RECT  2.304 46.157 36.414 46.265 ;
     RECT  0.54 46.219 1.278 46.349 ;
     RECT  38.052 45.389 38.862 46.543 ;
     RECT  2.304 46.265 21.798 46.571 ;
     RECT  22.68 46.265 36.414 46.637 ;
     RECT  0.54 46.349 0.558 46.733 ;
     RECT  0.144 46.843 0.234 47.047 ;
     RECT  2.376 46.571 21.798 47.047 ;
     RECT  22.68 46.637 36.342 47.047 ;
     RECT  0.108 47.047 0.234 47.117 ;
     RECT  2.376 47.047 36.342 47.117 ;
     RECT  1.152 47.083 1.17 47.213 ;
     RECT  0.144 47.117 0.234 47.501 ;
     RECT  37.62 46.543 38.862 47.501 ;
     RECT  2.376 47.117 36.234 47.551 ;
     RECT  38.088 47.501 38.862 47.597 ;
     RECT  0.144 47.501 0.162 47.789 ;
     RECT  2.304 47.551 36.234 47.929 ;
     RECT  0.108 47.851 0.126 48.619 ;
     RECT  0.108 48.619 0.162 48.631 ;
     RECT  0.108 48.631 0.198 48.667 ;
     RECT  2.304 47.929 36.342 48.739 ;
     RECT  1.26 48.523 1.278 48.763 ;
     RECT  38.124 47.597 38.862 48.775 ;
     RECT  1.152 48.763 1.278 48.797 ;
     RECT  0.108 48.667 0.234 48.941 ;
     RECT  37.584 48.775 38.862 48.941 ;
     RECT  1.152 48.797 1.242 48.989 ;
     RECT  1.224 48.989 1.242 49.181 ;
     RECT  2.304 48.739 36.558 49.469 ;
     RECT  2.304 49.469 36.234 49.541 ;
     RECT  2.304 49.541 30.402 49.577 ;
     RECT  2.304 49.577 22.95 49.613 ;
     RECT  0.108 48.941 0.198 49.675 ;
     RECT  23.724 49.577 30.402 50.045 ;
     RECT  37.62 48.941 38.862 50.189 ;
     RECT  0.108 49.675 0.342 50.359 ;
     RECT  23.832 50.045 30.402 50.359 ;
     RECT  31.176 49.541 36.234 50.359 ;
     RECT  0.108 50.359 0.378 50.395 ;
     RECT  23.832 50.359 36.234 50.431 ;
     RECT  0.108 50.395 0.414 50.521 ;
     RECT  2.304 49.613 22.914 50.521 ;
     RECT  2.232 50.521 22.914 50.621 ;
     RECT  0.036 50.521 0.414 50.669 ;
     RECT  23.832 50.431 36.486 50.693 ;
     RECT  2.268 50.621 22.914 50.779 ;
     RECT  23.832 50.693 36.234 50.779 ;
     RECT  2.268 50.779 36.234 50.819 ;
     RECT  1.152 50.779 1.17 50.827 ;
     RECT  38.196 50.189 38.862 50.935 ;
     RECT  1.152 50.827 1.278 50.957 ;
     RECT  37.044 51.169 37.062 51.341 ;
     RECT  38.16 50.935 38.862 51.475 ;
     RECT  1.152 50.957 1.17 51.485 ;
     RECT  0.036 50.669 0.234 51.503 ;
     RECT  38.124 51.475 38.862 51.739 ;
     RECT  0.108 51.503 0.234 51.917 ;
     RECT  2.268 50.819 35.874 51.943 ;
     RECT  2.268 51.943 35.946 52.051 ;
     RECT  2.268 52.051 36.27 52.205 ;
     RECT  0.324 52.171 0.342 52.249 ;
     RECT  2.268 52.205 35.91 52.363 ;
     RECT  0.324 52.249 0.558 52.493 ;
     RECT  38.088 51.739 38.862 52.555 ;
     RECT  2.196 52.363 35.91 52.619 ;
     RECT  0.324 52.493 0.342 52.747 ;
     RECT  0.108 52.747 0.342 52.781 ;
     RECT  37.584 52.555 38.862 52.877 ;
     RECT  2.304 52.619 35.91 52.987 ;
     RECT  0.108 52.781 0.126 53.021 ;
     RECT  37.584 52.877 37.638 53.035 ;
     RECT  37.548 53.035 37.638 53.261 ;
     RECT  38.52 52.877 38.862 53.309 ;
     RECT  37.548 53.261 37.602 53.419 ;
     RECT  2.304 52.987 36.45 53.789 ;
     RECT  2.304 53.789 36.378 53.825 ;
     RECT  37.512 53.419 37.602 53.969 ;
     RECT  2.304 53.825 36.27 54.095 ;
     RECT  37.584 53.969 37.602 54.211 ;
     RECT  38.556 53.309 38.862 54.211 ;
     RECT  2.304 54.095 36.234 54.239 ;
     RECT  37.584 54.211 38.862 54.401 ;
     RECT  37.584 54.401 38.826 54.913 ;
     RECT  2.415 54.239 36.234 55.021 ;
     RECT  2.415 55.021 36.594 55.139 ;
     RECT  37.548 54.913 38.826 55.181 ;
     RECT  37.584 55.181 38.826 55.915 ;
     RECT  37.548 55.915 38.826 56.021 ;
     RECT  37.584 56.021 38.826 56.146 ;
     RECT  0.54 55.651 0.558 56.191 ;
     RECT  2.415 55.139 36.198 56.371 ;
     RECT  2.415 56.371 36.486 56.633 ;
     RECT  2.415 56.633 36.27 56.683 ;
     RECT  0.108 56.191 0.558 56.813 ;
     RECT  37.584 56.146 38.862 56.971 ;
     RECT  0.108 56.813 0.162 57.005 ;
     RECT  2.304 56.683 36.27 57.541 ;
     RECT  2.304 57.541 36.522 57.577 ;
     RECT  37.548 56.971 38.862 57.577 ;
     RECT  2.304 57.577 38.862 57.713 ;
     RECT  37.548 57.713 38.862 57.911 ;
     RECT  0.144 57.005 0.162 58.061 ;
     RECT  0.108 58.081 0.126 58.157 ;
     RECT  0.144 58.795 0.162 59.213 ;
     RECT  2.304 57.713 36.522 59.459 ;
     RECT  2.34 59.459 36.522 59.729 ;
     RECT  0.108 59.659 0.126 59.789 ;
     RECT  2.415 59.729 36.522 59.999 ;
     RECT  37.872 57.911 38.862 60.449 ;
     RECT  38.628 60.449 38.862 60.539 ;
     RECT  2.415 59.999 36.486 61.151 ;
     RECT  2.415 61.151 36.27 61.889 ;
     RECT  0.108 62.509 0.126 62.581 ;
     RECT  15.696 61.889 36.27 62.671 ;
     RECT  2.415 61.889 14.958 62.779 ;
     RECT  15.696 62.671 36.594 62.779 ;
     RECT  0.108 62.581 0.558 62.957 ;
     RECT  37.872 60.449 37.89 62.969 ;
     RECT  2.415 62.779 36.594 63.112 ;
     RECT  0.144 62.957 0.558 63.581 ;
     RECT  0.216 63.581 0.558 63.629 ;
     RECT  2.304 63.112 36.594 63.653 ;
     RECT  0.324 63.629 0.558 63.725 ;
     RECT  38.844 60.539 38.862 63.823 ;
     RECT  38.52 63.823 38.862 64.165 ;
     RECT  2.304 63.653 36.27 64.363 ;
     RECT  0.54 63.725 0.558 64.493 ;
     RECT  2.196 64.363 36.27 64.555 ;
     RECT  2.196 64.555 36.522 64.705 ;
     RECT  0.144 64.555 0.162 64.733 ;
     RECT  1.332 64.699 1.35 64.795 ;
     RECT  2.196 64.705 37.062 64.795 ;
     RECT  1.152 64.795 1.35 64.843 ;
     RECT  2.16 64.795 37.062 64.967 ;
     RECT  1.152 64.843 1.422 64.973 ;
     RECT  2.16 64.967 36.27 65.003 ;
     RECT  38.196 64.165 38.862 65.261 ;
     RECT  38.52 65.261 38.862 65.435 ;
     RECT  38.52 65.435 38.79 65.453 ;
     RECT  37.044 64.967 37.062 65.741 ;
     RECT  2.304 65.003 36.27 65.899 ;
     RECT  2.304 65.899 36.522 65.939 ;
     RECT  2.415 65.939 36.522 66.083 ;
     RECT  37.548 65.785 37.602 66.353 ;
     RECT  38.52 65.453 38.718 66.361 ;
     RECT  38.52 66.361 38.79 66.475 ;
     RECT  38.196 66.475 38.79 66.623 ;
     RECT  38.232 66.623 38.79 66.701 ;
     RECT  2.415 66.083 36.27 66.859 ;
     RECT  2.415 66.859 36.99 67.091 ;
     RECT  38.592 66.701 38.79 67.181 ;
     RECT  38.736 67.181 38.79 67.433 ;
     RECT  2.415 67.091 36.378 67.531 ;
     RECT  38.736 67.433 38.754 68.155 ;
     RECT  2.376 67.531 36.378 68.215 ;
     RECT  2.376 68.215 36.414 68.369 ;
     RECT  38.664 68.155 38.754 68.485 ;
     RECT  38.196 68.485 38.754 68.791 ;
     RECT  0.54 68.881 0.558 68.917 ;
     RECT  0.108 68.917 0.558 69.005 ;
     RECT  2.415 68.369 36.414 69.151 ;
     RECT  0.108 69.005 0.198 69.581 ;
     RECT  38.196 68.791 38.862 69.835 ;
     RECT  0.144 69.581 0.198 70.033 ;
     RECT  2.304 69.151 36.414 70.123 ;
     RECT  2.268 70.123 36.414 70.259 ;
     RECT  0.144 70.033 0.558 70.459 ;
     RECT  0.144 70.459 1.17 70.507 ;
     RECT  37.872 69.835 38.862 70.573 ;
     RECT  0.144 70.507 1.278 70.637 ;
     RECT  2.304 70.259 36.414 70.645 ;
     RECT  37.62 70.573 38.862 70.891 ;
     RECT  2.304 70.645 36.486 71.083 ;
     RECT  2.304 71.083 36.522 71.213 ;
     RECT  37.584 70.891 38.862 71.659 ;
     RECT  37.512 71.659 38.862 71.753 ;
     RECT  2.304 71.213 36.414 71.851 ;
     RECT  37.584 71.753 38.862 71.879 ;
     RECT  0.144 70.637 0.558 71.959 ;
     RECT  37.584 71.879 38.79 71.981 ;
     RECT  2.268 71.851 36.414 72.059 ;
     RECT  0.144 71.959 1.206 72.427 ;
     RECT  2.304 72.059 36.414 72.535 ;
     RECT  0.144 72.427 1.278 72.557 ;
     RECT  0.144 72.557 1.17 72.653 ;
     RECT  2.304 72.535 36.522 72.653 ;
     RECT  37.584 71.981 38.754 72.811 ;
     RECT  0.144 72.653 0.558 72.931 ;
     RECT  37.584 72.811 38.79 73.133 ;
     RECT  2.304 72.653 36.414 73.291 ;
     RECT  2.196 73.291 36.414 73.409 ;
     RECT  37.872 73.133 38.79 73.409 ;
     RECT  0.108 72.931 0.558 73.421 ;
     RECT  2.304 73.409 36.414 73.651 ;
     RECT  0.108 73.421 0.522 73.709 ;
     RECT  0.108 73.709 0.198 73.805 ;
     RECT  2.304 73.651 36.558 74.183 ;
     RECT  0.108 73.805 0.162 74.285 ;
     RECT  37.872 73.409 38.754 74.347 ;
     RECT  0.144 74.285 0.162 74.573 ;
     RECT  2.304 74.183 36.414 75.019 ;
     RECT  2.268 75.019 36.414 75.119 ;
     RECT  2.304 75.119 36.414 75.389 ;
     RECT  2.415 75.389 36.414 75.569 ;
     RECT  2.415 75.569 35.766 76.315 ;
     RECT  2.376 76.315 35.766 76.549 ;
     RECT  37.044 76.513 37.062 76.685 ;
     RECT  37.872 74.347 38.79 76.739 ;
     RECT  2.376 76.549 35.838 76.891 ;
     RECT  2.376 76.891 36.054 77.153 ;
     RECT  2.415 77.153 35.442 77.189 ;
     RECT  38.772 76.739 38.79 77.359 ;
     RECT  2.415 77.189 35.406 77.947 ;
     RECT  37.872 76.739 37.89 77.999 ;
     RECT  2.415 77.947 35.658 78.061 ;
     RECT  38.772 77.359 38.862 78.601 ;
     RECT  2.415 78.061 35.91 78.637 ;
     RECT  38.7 78.601 38.862 78.673 ;
     RECT  2.415 78.637 35.982 78.709 ;
     RECT  2.415 78.709 36.09 78.745 ;
     RECT  0.54 78.601 0.558 79.051 ;
     RECT  2.34 78.745 36.09 79.051 ;
     RECT  0.144 79.051 0.558 79.229 ;
     RECT  0.54 79.229 0.558 79.291 ;
     RECT  0.54 79.291 1.17 79.339 ;
     RECT  0.54 79.339 1.386 79.469 ;
     RECT  38.628 78.673 38.862 79.519 ;
     RECT  38.52 79.519 38.862 79.555 ;
     RECT  38.232 79.555 38.862 79.591 ;
     RECT  0.54 79.469 1.314 79.757 ;
     RECT  2.304 79.051 36.09 79.825 ;
     RECT  2.304 79.825 36.198 79.861 ;
     RECT  37.044 79.015 37.062 79.861 ;
     RECT  0.54 79.757 0.666 79.949 ;
     RECT  2.304 79.861 37.062 79.951 ;
     RECT  38.196 79.591 38.862 79.951 ;
     RECT  0.54 79.949 0.558 80.023 ;
     RECT  2.304 79.951 38.862 80.123 ;
     RECT  0.216 80.023 0.558 80.429 ;
     RECT  2.304 80.123 36.09 80.539 ;
     RECT  1.98 80.539 36.09 80.717 ;
     RECT  0.216 80.429 0.522 80.909 ;
     RECT  0.216 80.909 0.234 81.293 ;
     RECT  2.304 80.717 36.09 81.409 ;
     RECT  0.144 81.691 0.198 81.868 ;
     RECT  2.304 81.409 36.234 81.869 ;
     RECT  2.304 81.869 36.126 82.139 ;
     RECT  0.108 81.868 0.198 82.183 ;
     RECT  37.044 80.123 38.862 82.247 ;
     RECT  2.304 82.139 35.982 82.445 ;
     RECT  37.044 82.247 38.79 82.541 ;
     RECT  37.044 82.541 38.754 82.637 ;
     RECT  0.108 82.183 0.558 82.679 ;
     RECT  37.044 82.637 38.718 82.829 ;
     RECT  2.304 82.445 35.91 82.993 ;
     RECT  0.504 82.679 0.558 83.117 ;
     RECT  2.268 82.993 35.91 83.191 ;
     RECT  2.268 83.191 35.946 83.213 ;
     RECT  37.584 82.829 38.718 83.371 ;
     RECT  0.504 83.117 0.522 83.405 ;
     RECT  37.584 83.371 38.79 83.408 ;
     RECT  2.304 83.213 35.946 83.569 ;
     RECT  37.584 83.408 38.286 83.755 ;
     RECT  2.304 83.569 36.306 83.795 ;
     RECT  2.415 83.795 36.306 84.073 ;
     RECT  0.324 83.659 0.342 84.091 ;
     RECT  0.144 84.091 0.342 84.181 ;
     RECT  37.512 83.755 38.286 84.209 ;
     RECT  37.872 84.209 38.286 84.235 ;
     RECT  37.872 84.235 38.718 84.343 ;
     RECT  2.415 84.073 36.522 84.371 ;
     RECT  37.872 84.343 38.826 84.451 ;
     RECT  0.144 84.181 0.558 84.461 ;
     RECT  2.415 84.371 35.946 84.541 ;
     RECT  2.412 84.541 35.946 84.712 ;
     RECT  0.144 84.461 0.342 84.811 ;
     RECT  0.108 84.811 0.342 84.941 ;
     RECT  37.008 84.415 37.062 85.099 ;
     RECT  37.872 84.451 38.862 85.099 ;
     RECT  0.108 84.941 0.126 85.133 ;
     RECT  2.304 84.712 35.946 85.291 ;
     RECT  37.008 85.099 38.862 85.291 ;
     RECT  2.304 85.291 38.862 85.451 ;
     RECT  0.108 85.891 0.126 86.059 ;
     RECT  0.108 86.059 0.162 86.203 ;
     RECT  0.108 86.203 0.306 86.573 ;
     RECT  0.108 86.573 0.126 86.669 ;
     RECT  2.304 85.451 36.522 86.809 ;
     RECT  37.548 85.451 38.862 86.809 ;
     RECT  2.304 86.809 38.862 87.421 ;
     RECT  2.268 87.421 38.862 87.437 ;
     RECT  2.268 87.437 37.062 87.533 ;
     RECT  0.324 87.979 0.342 88.075 ;
     RECT  0.108 88.075 0.342 88.109 ;
     RECT  2.304 87.533 37.062 88.159 ;
     RECT  37.908 87.437 38.862 88.159 ;
     RECT  0.108 88.109 0.126 88.205 ;
     RECT  2.304 88.159 38.862 88.223 ;
     RECT  2.304 88.223 36.594 88.259 ;
     RECT  2.34 88.259 36.594 88.349 ;
     RECT  37.62 88.223 38.862 88.493 ;
     RECT  2.376 88.349 36.594 89.311 ;
     RECT  2.376 89.311 37.026 89.473 ;
     RECT  2.376 89.473 37.062 89.735 ;
     RECT  36.54 89.735 37.062 89.741 ;
     RECT  37.908 88.493 38.862 89.789 ;
     RECT  38.16 89.789 38.862 89.879 ;
     RECT  36.54 89.741 36.558 90.149 ;
     RECT  38.7 89.879 38.862 90.419 ;
     RECT  2.376 89.735 35.766 90.617 ;
     RECT  2.376 90.617 35.694 90.659 ;
     RECT  23.112 90.659 35.694 90.887 ;
     RECT  2.376 90.659 22.374 91.319 ;
     RECT  23.112 90.887 35.478 91.319 ;
     RECT  38.7 90.419 38.718 91.391 ;
     RECT  33.408 91.319 33.93 91.469 ;
     RECT  2.415 91.319 22.374 91.471 ;
     RECT  23.112 91.319 32.526 91.471 ;
     RECT  33.912 91.469 33.93 91.499 ;
     RECT  34.815 91.319 35.478 91.769 ;
     RECT  2.415 91.471 32.526 92.399 ;
     RECT  2.415 92.399 30.294 92.435 ;
     RECT  2.415 92.435 28.026 92.551 ;
     RECT  2.376 92.551 28.026 92.579 ;
     RECT  34.815 91.769 35.097 92.627 ;
     RECT  4.212 92.579 17.442 92.669 ;
     RECT  18.216 92.579 28.026 92.669 ;
     RECT  28.944 92.435 30.294 92.669 ;
     RECT  31.212 92.399 32.526 92.669 ;
     RECT  25.776 92.669 28.026 92.675 ;
     RECT  6.012 92.669 8.01 92.705 ;
     RECT  10.44 92.669 11.07 92.705 ;
     RECT  11.916 92.669 14.13 92.705 ;
     RECT  31.212 92.669 32.205 92.705 ;
     RECT  2.376 92.579 3.294 92.717 ;
     RECT  20.664 92.669 21.726 92.717 ;
     RECT  26.715 92.675 28.026 92.717 ;
     RECT  29.052 92.669 29.505 92.717 ;
     RECT  30.276 92.669 30.294 92.717 ;
     RECT  2.415 92.717 3.258 92.741 ;
     RECT  18.216 92.669 19.89 92.741 ;
     RECT  6.696 92.705 6.714 92.777 ;
     RECT  14.112 92.705 14.13 92.777 ;
     RECT  23.4 92.669 24.498 92.777 ;
     RECT  3.24 92.741 3.258 92.813 ;
     RECT  4.536 92.669 5.205 92.813 ;
     RECT  7.704 92.705 8.01 92.813 ;
     RECT  8.748 92.669 9.486 92.813 ;
     RECT  10.512 92.705 10.998 92.813 ;
     RECT  11.916 92.705 12.294 92.813 ;
     RECT  15.192 92.669 17.442 92.813 ;
     RECT  18.216 92.741 19.566 92.813 ;
     RECT  21.132 92.717 21.726 92.813 ;
     RECT  24.015 92.777 24.498 92.813 ;
     RECT  25.776 92.675 25.794 92.813 ;
     RECT  26.715 92.717 27.414 92.813 ;
     RECT  29.088 92.717 29.505 92.813 ;
     RECT  8.928 92.813 9.054 92.819 ;
     RECT  7.815 92.813 8.01 92.849 ;
     RECT  8.928 92.819 8.946 92.849 ;
     RECT  10.515 92.813 10.998 92.849 ;
     RECT  15.192 92.813 17.154 92.849 ;
     RECT  18.216 92.813 18.705 92.849 ;
     RECT  2.415 92.741 2.505 92.897 ;
     RECT  5.115 92.813 5.205 92.897 ;
     RECT  7.815 92.849 7.905 92.897 ;
     RECT  10.515 92.849 10.605 92.897 ;
     RECT  13.215 92.705 13.305 92.897 ;
     RECT  15.915 92.849 16.506 92.897 ;
     RECT  18.615 92.849 18.705 92.897 ;
     RECT  21.315 92.813 21.405 92.897 ;
     RECT  24.015 92.813 24.105 92.897 ;
     RECT  26.715 92.813 26.805 92.897 ;
     RECT  29.415 92.813 29.505 92.897 ;
     RECT  32.115 92.705 32.205 92.897 ;
     RECT  34.815 92.627 34.905 92.897 ;
     RECT  16.308 92.897 16.506 94.843 ;
     RECT  16.236 94.843 16.506 94.939 ;
     RECT  16.164 94.939 16.506 95.009 ;
     RECT  16.164 95.009 16.398 95.021 ;
    LAYER M4 ;
     RECT  0.06 18.288 0.097 21.288 ;
     RECT  0.06 43.632 0.097 52.776 ;
     RECT  0.06 56.688 0.097 59.688 ;
     RECT  0.06 78.96 0.097 88.104 ;
     RECT  0.06 5.232 0.137 14.376 ;
     RECT  0.097 18.288 0.137 21.384 ;
     RECT  0.06 27.504 0.137 33.576 ;
     RECT  0.097 43.632 0.181 53.016 ;
     RECT  0.181 42.768 0.323 53.016 ;
     RECT  0.137 27.6 0.569 33.576 ;
     RECT  0.06 62.832 0.569 65.832 ;
     RECT  0.06 68.976 0.569 75.048 ;
     RECT  0.097 78.96 0.569 88.2 ;
     RECT  0.137 5.328 2.365 14.376 ;
     RECT  0.569 79.152 2.365 88.2 ;
     RECT  2.365 5.328 2.408 15.24 ;
     RECT  2.365 16.896 2.408 16.92 ;
     RECT  0.137 18.384 2.408 21.384 ;
     RECT  0.06 22.512 2.408 24.36 ;
     RECT  0.569 27.792 2.408 33.576 ;
     RECT  0.06 37.488 2.408 40.488 ;
     RECT  0.323 43.632 2.408 53.016 ;
     RECT  0.097 56.688 2.408 59.784 ;
     RECT  0.569 63.024 2.408 65.832 ;
     RECT  0.569 69.168 2.408 75.048 ;
     RECT  2.365 76.32 2.408 76.344 ;
     RECT  2.365 79.152 2.408 88.92 ;
     RECT  2.365 90.048 2.408 90.072 ;
     RECT  2.365 92.688 2.408 92.712 ;
     RECT  2.408 2.148 2.512 92.892 ;
     RECT  2.512 2.418 2.704 92.712 ;
     RECT  2.704 36.48 3.089 40.392 ;
     RECT  2.704 43.824 3.125 66.744 ;
     RECT  2.704 4.512 3.148 26.808 ;
     RECT  2.704 92.16 3.305 92.712 ;
     RECT  3.089 36.48 3.34 40.056 ;
     RECT  3.34 36.48 3.557 36.504 ;
     RECT  2.704 90.048 3.692 90.264 ;
     RECT  3.692 90 3.733 90.264 ;
     RECT  2.704 3.024 3.74 3.048 ;
     RECT  3.148 4.512 3.74 24.984 ;
     RECT  2.704 27.888 3.769 33.576 ;
     RECT  2.704 41.376 3.769 41.928 ;
     RECT  3.125 54.768 3.769 66.744 ;
     RECT  3.125 43.824 3.773 53.736 ;
     RECT  3.733 90 3.805 90.312 ;
     RECT  2.704 68.88 3.829 88.92 ;
     RECT  3.829 68.88 3.841 88.968 ;
     RECT  3.841 68.592 3.877 88.968 ;
     RECT  3.805 90 3.877 90.792 ;
     RECT  2.704 34.848 3.884 35.352 ;
     RECT  3.769 54.768 3.925 66.984 ;
     RECT  3.148 26.112 3.949 26.808 ;
     RECT  3.769 27.888 3.949 33.624 ;
     RECT  3.769 41.376 3.949 42.792 ;
     RECT  3.773 43.824 3.949 53.544 ;
     RECT  3.305 92.16 3.949 92.232 ;
     RECT  3.949 26.112 3.98 33.624 ;
     RECT  3.884 34.848 3.98 35.448 ;
     RECT  3.877 68.592 4.021 90.792 ;
     RECT  3.98 26.112 4.093 35.448 ;
     RECT  3.949 41.376 4.129 53.544 ;
     RECT  3.74 3.024 4.165 24.984 ;
     RECT  3.925 54.768 4.165 67.512 ;
     RECT  3.949 91.824 4.273 92.232 ;
     RECT  4.165 54.72 4.357 67.512 ;
     RECT  4.021 68.592 4.357 90.84 ;
     RECT  4.165 2.592 4.389 24.984 ;
     RECT  4.093 26.112 4.389 36.264 ;
     RECT  4.389 2.592 4.525 36.264 ;
     RECT  4.357 54.72 4.561 90.84 ;
     RECT  4.273 91.824 4.561 92.376 ;
     RECT  3.34 37.584 4.669 40.056 ;
     RECT  4.129 41.136 4.669 53.544 ;
     RECT  4.561 54.72 4.741 92.376 ;
     RECT  4.669 37.584 4.777 53.544 ;
     RECT  4.741 54.624 4.777 92.376 ;
     RECT  4.525 2.592 4.789 36.408 ;
     RECT  4.777 37.584 4.789 92.376 ;
     RECT  4.789 2.592 4.981 92.376 ;
     RECT  4.981 2.256 5.029 92.376 ;
     RECT  5.029 2.256 5.108 92.424 ;
     RECT  5.108 2.148 5.212 92.892 ;
     RECT  5.212 2.256 5.404 92.622 ;
     RECT  5.404 2.256 5.861 92.424 ;
     RECT  5.861 2.256 6.149 92.28 ;
     RECT  6.149 2.256 7.117 56.28 ;
     RECT  6.149 57.312 7.117 92.28 ;
     RECT  7.117 2.256 7.808 92.28 ;
     RECT  7.808 2.148 7.912 92.892 ;
     RECT  7.912 2.418 8.104 92.808 ;
     RECT  8.104 2.496 8.741 92.808 ;
     RECT  8.741 34.656 9.065 92.808 ;
     RECT  9.065 34.656 9.353 91.224 ;
     RECT  9.353 34.656 9.497 90.888 ;
     RECT  9.497 67.584 10.357 90.888 ;
     RECT  8.741 2.496 10.508 33.624 ;
     RECT  9.497 34.656 10.508 66.6 ;
     RECT  10.357 67.584 10.508 91.08 ;
     RECT  10.508 2.148 10.612 92.892 ;
     RECT  10.612 2.418 10.804 92.622 ;
     RECT  10.804 92.352 11.945 92.376 ;
     RECT  10.804 2.448 12.017 91.176 ;
     RECT  12.017 2.496 12.053 90.024 ;
     RECT  12.053 3.936 12.125 90.024 ;
     RECT  12.017 91.056 13.057 91.176 ;
     RECT  12.125 3.936 13.093 60.456 ;
     RECT  12.125 61.44 13.093 90.024 ;
     RECT  13.057 91.056 13.093 91.608 ;
     RECT  12.053 2.496 13.208 2.52 ;
     RECT  13.093 3.936 13.208 91.608 ;
     RECT  13.208 2.148 13.312 92.892 ;
     RECT  13.312 2.418 13.504 92.622 ;
     RECT  13.504 35.184 13.619 92.376 ;
     RECT  13.619 35.184 13.781 91.896 ;
     RECT  13.781 61.392 13.853 91.896 ;
     RECT  13.853 61.44 14.105 91.896 ;
     RECT  13.504 4.368 14.465 33.96 ;
     RECT  14.465 4.368 14.569 25.368 ;
     RECT  14.465 26.352 14.713 33.96 ;
     RECT  14.713 26.352 14.821 34.104 ;
     RECT  13.781 35.184 14.821 60.408 ;
     RECT  14.821 26.352 14.857 60.408 ;
     RECT  14.105 61.44 14.857 68.424 ;
     RECT  14.105 69.552 15.349 91.896 ;
     RECT  14.569 4.224 15.361 25.368 ;
     RECT  15.361 3.648 15.469 25.368 ;
     RECT  15.469 3.408 15.541 25.368 ;
     RECT  15.541 2.88 15.577 25.368 ;
     RECT  14.857 26.352 15.577 68.424 ;
     RECT  15.577 2.88 15.901 68.424 ;
     RECT  15.901 2.832 15.908 68.424 ;
     RECT  15.349 69.552 15.908 92.424 ;
     RECT  15.908 2.148 16.012 92.892 ;
     RECT  16.012 2.256 16.204 92.622 ;
     RECT  16.153 94.944 16.225 94.968 ;
     RECT  16.225 94.848 16.403 94.968 ;
     RECT  16.403 94.848 16.451 94.872 ;
     RECT  16.204 2.256 16.547 92.376 ;
     RECT  16.547 2.256 16.876 92.136 ;
     RECT  16.876 2.736 18.025 92.136 ;
     RECT  18.025 2.736 18.061 92.232 ;
     RECT  18.061 2.736 18.373 92.376 ;
     RECT  18.373 2.736 18.608 92.808 ;
     RECT  18.608 2.148 18.712 92.892 ;
     RECT  18.712 2.418 18.904 92.808 ;
     RECT  18.904 4.224 19.037 92.808 ;
     RECT  19.037 4.224 19.469 92.76 ;
     RECT  18.904 2.88 19.897 3 ;
     RECT  19.897 2.784 20.005 3 ;
     RECT  20.005 2.784 20.113 3.096 ;
     RECT  19.469 4.224 20.113 92.664 ;
     RECT  20.113 2.784 20.153 92.664 ;
     RECT  20.153 2.784 20.725 91.464 ;
     RECT  20.725 2.352 21.157 91.464 ;
     RECT  21.157 2.352 21.308 91.608 ;
     RECT  20.653 92.688 21.308 92.712 ;
     RECT  21.308 2.148 21.412 92.892 ;
     RECT  21.412 2.352 21.604 92.712 ;
     RECT  21.604 35.184 21.737 92.712 ;
     RECT  21.737 35.184 21.772 92.376 ;
     RECT  21.604 2.352 22.097 34.152 ;
     RECT  21.772 35.184 22.097 91.752 ;
     RECT  22.097 78.96 22.277 91.752 ;
     RECT  22.097 2.352 22.313 19.8 ;
     RECT  22.277 78.96 22.349 91.224 ;
     RECT  22.097 20.88 22.457 34.152 ;
     RECT  22.349 78.96 22.493 90.648 ;
     RECT  22.457 27.936 22.777 34.152 ;
     RECT  22.097 35.184 22.777 77.544 ;
     RECT  22.457 20.88 22.933 26.904 ;
     RECT  22.777 27.936 22.961 77.544 ;
     RECT  22.313 2.352 23.281 19.656 ;
     RECT  22.933 20.88 23.281 23.976 ;
     RECT  23.137 92.352 23.353 92.376 ;
     RECT  22.493 78.96 23.461 90.6 ;
     RECT  23.461 78.96 23.533 91.32 ;
     RECT  22.933 25.008 23.821 26.904 ;
     RECT  22.961 27.936 23.821 77.4 ;
     RECT  23.533 78.624 23.893 91.32 ;
     RECT  23.353 92.352 23.893 92.472 ;
     RECT  23.281 2.352 24.008 23.976 ;
     RECT  23.821 25.008 24.008 77.4 ;
     RECT  23.893 78.624 24.008 92.472 ;
     RECT  24.008 2.148 24.112 92.892 ;
     RECT  24.112 2.352 24.304 92.622 ;
     RECT  24.304 2.352 24.473 91.8 ;
     RECT  24.473 2.352 24.797 70.344 ;
     RECT  24.473 71.328 24.803 91.8 ;
     RECT  24.797 3.456 24.905 70.344 ;
     RECT  24.797 2.352 25.121 2.376 ;
     RECT  24.803 71.424 25.229 91.8 ;
     RECT  24.905 3.456 25.337 62.52 ;
     RECT  25.337 4.08 25.516 62.52 ;
     RECT  25.516 41.232 25.945 62.52 ;
     RECT  24.905 63.504 25.945 70.344 ;
     RECT  25.945 41.232 25.981 70.344 ;
     RECT  25.229 71.424 25.981 91.176 ;
     RECT  26.125 92.64 26.197 92.664 ;
     RECT  25.801 2.64 26.449 2.664 ;
     RECT  25.516 4.08 26.449 40.152 ;
     RECT  25.981 41.232 26.593 91.176 ;
     RECT  26.449 2.64 26.708 40.152 ;
     RECT  26.593 41.184 26.708 91.176 ;
     RECT  26.197 92.16 26.708 92.664 ;
     RECT  26.708 2.148 26.812 92.892 ;
     RECT  26.812 2.418 27.004 92.622 ;
     RECT  27.004 3.264 27.245 41.208 ;
     RECT  27.245 3.264 27.317 39.288 ;
     RECT  27.004 42.192 27.877 92.622 ;
     RECT  27.877 42.192 27.923 92.712 ;
     RECT  27.923 42.192 28.259 91.704 ;
     RECT  27.317 20.304 28.453 34.2 ;
     RECT  27.317 35.184 28.453 39.288 ;
     RECT  27.317 3.264 28.46 19.08 ;
     RECT  28.46 3.264 28.465 19.128 ;
     RECT  28.453 20.304 28.465 39.288 ;
     RECT  28.465 3.264 28.717 39.288 ;
     RECT  27.245 40.32 28.717 41.208 ;
     RECT  28.717 3.264 29.041 41.208 ;
     RECT  29.041 2.832 29.077 41.208 ;
     RECT  29.077 2.256 29.173 41.208 ;
     RECT  28.259 42.192 29.173 76.872 ;
     RECT  28.259 78.192 29.221 91.704 ;
     RECT  29.173 2.256 29.408 76.872 ;
     RECT  29.221 77.952 29.408 91.704 ;
     RECT  27.923 92.688 29.408 92.712 ;
     RECT  29.408 2.148 29.512 92.892 ;
     RECT  29.512 2.418 29.704 92.712 ;
     RECT  29.704 77.712 30.233 91.464 ;
     RECT  29.704 2.64 30.241 76.536 ;
     RECT  29.704 92.544 30.305 92.712 ;
     RECT  30.241 2.64 30.413 39.288 ;
     RECT  30.233 77.712 30.413 78.936 ;
     RECT  30.233 80.208 30.449 91.464 ;
     RECT  30.413 2.64 30.604 39 ;
     RECT  30.413 77.712 30.803 77.736 ;
     RECT  30.241 40.56 30.877 76.536 ;
     RECT  30.449 80.256 31.025 91.464 ;
     RECT  30.604 2.64 31.597 22.92 ;
     RECT  31.597 2.256 31.669 22.92 ;
     RECT  30.604 23.904 31.669 39 ;
     RECT  31.669 2.256 31.705 39 ;
     RECT  30.877 40.56 31.82 76.872 ;
     RECT  31.705 2.256 31.841 39.288 ;
     RECT  30.413 78.72 31.957 78.936 ;
     RECT  31.025 80.256 31.957 91.224 ;
     RECT  31.841 2.256 31.993 39.336 ;
     RECT  31.82 40.512 31.993 76.872 ;
     RECT  31.993 2.256 32.108 76.872 ;
     RECT  31.957 78.72 32.108 91.224 ;
     RECT  30.305 92.544 32.108 92.568 ;
     RECT  32.108 2.148 32.212 92.892 ;
     RECT  32.212 2.418 32.404 92.622 ;
     RECT  32.404 78.048 32.573 91.464 ;
     RECT  32.404 20.064 32.753 76.872 ;
     RECT  32.753 42.576 32.825 76.872 ;
     RECT  32.753 20.064 33.221 41.592 ;
     RECT  32.825 42.72 33.257 76.872 ;
     RECT  32.573 91.44 33.437 91.464 ;
     RECT  32.404 3.36 33.505 19.08 ;
     RECT  33.221 20.064 33.505 41.496 ;
     RECT  32.573 78.048 33.505 90.12 ;
     RECT  33.505 3.36 33.517 41.496 ;
     RECT  33.517 3.36 33.545 20.664 ;
     RECT  33.505 77.952 33.613 90.12 ;
     RECT  33.613 77.952 33.797 90.6 ;
     RECT  33.257 42.768 33.901 76.872 ;
     RECT  33.797 77.952 33.901 90.12 ;
     RECT  33.517 21.792 34.333 41.496 ;
     RECT  33.901 42.768 34.333 90.12 ;
     RECT  33.545 4.224 34.808 20.664 ;
     RECT  34.333 21.792 34.808 90.12 ;
     RECT  34.808 2.148 34.912 92.892 ;
     RECT  34.912 2.418 35.104 92.622 ;
     RECT  35.104 20.448 35.165 41.496 ;
     RECT  35.104 58.128 35.165 58.44 ;
     RECT  35.104 60.288 35.165 63.288 ;
     RECT  35.165 58.416 35.201 58.44 ;
     RECT  35.165 20.448 35.26 38.232 ;
     RECT  35.26 20.448 35.267 20.616 ;
     RECT  35.104 42.72 35.273 57.048 ;
     RECT  35.104 64.416 35.273 76.584 ;
     RECT  35.267 20.592 35.381 20.616 ;
     RECT  35.165 61.632 35.381 63.288 ;
     RECT  35.104 6.912 35.417 19.272 ;
     RECT  35.273 42.72 35.453 44.184 ;
     RECT  35.165 39.84 35.489 41.496 ;
     RECT  35.453 42.72 35.489 42.744 ;
     RECT  35.165 60.288 35.489 60.408 ;
     RECT  35.273 69.264 35.489 76.584 ;
     RECT  35.104 77.952 35.489 78.648 ;
     RECT  35.26 21.648 35.525 38.232 ;
     RECT  35.489 39.84 35.525 40.968 ;
     RECT  35.525 21.648 35.597 24.936 ;
     RECT  35.381 62.544 35.597 63.288 ;
     RECT  35.597 21.648 35.633 24.744 ;
     RECT  35.525 39.84 35.633 39.864 ;
     RECT  35.489 60.288 35.633 60.312 ;
     RECT  35.104 79.776 35.633 89.784 ;
     RECT  35.525 26.112 35.651 38.232 ;
     RECT  35.597 62.544 35.669 62.568 ;
     RECT  35.489 77.952 35.669 78.312 ;
     RECT  35.651 26.256 35.741 38.232 ;
     RECT  35.489 69.84 35.849 76.584 ;
     RECT  35.669 78.192 35.849 78.312 ;
     RECT  35.741 28.272 35.885 34.152 ;
     RECT  35.849 78.192 35.885 78.216 ;
     RECT  35.885 28.272 35.957 33.96 ;
     RECT  35.633 80.064 35.993 89.784 ;
     RECT  35.741 26.304 36.029 27.192 ;
     RECT  35.993 80.064 36.029 81.672 ;
     RECT  35.273 45.264 36.133 57.048 ;
     RECT  36.029 26.304 36.173 26.376 ;
     RECT  35.525 40.944 36.173 40.968 ;
     RECT  35.741 35.232 36.209 38.232 ;
     RECT  35.633 22.032 36.245 24.744 ;
     RECT  36.173 26.352 36.461 26.376 ;
     RECT  35.273 64.608 36.493 68.184 ;
     RECT  35.957 29.232 36.997 33.96 ;
     RECT  36.209 35.232 36.997 36.936 ;
     RECT  35.849 69.84 37.033 76.488 ;
     RECT  36.029 80.88 37.033 81.672 ;
     RECT  35.993 82.704 37.033 89.784 ;
     RECT  36.997 29.232 37.393 36.936 ;
     RECT  36.209 37.968 37.393 38.232 ;
     RECT  35.417 6.912 37.609 19.08 ;
     RECT  37.033 80.88 37.609 89.784 ;
     RECT  37.033 69.84 37.901 76.68 ;
     RECT  37.609 80.784 37.937 89.784 ;
     RECT  35.453 43.872 38.081 44.184 ;
     RECT  37.393 29.232 38.149 38.232 ;
     RECT  38.149 29.136 38.152 38.232 ;
     RECT  38.081 43.872 38.153 44.136 ;
     RECT  36.245 22.032 38.185 22.824 ;
     RECT  36.245 23.952 38.185 24.744 ;
     RECT  36.493 64.56 38.473 68.184 ;
     RECT  36.133 45.264 38.545 57.48 ;
     RECT  37.937 80.784 38.689 89.736 ;
     RECT  38.473 64.464 38.693 68.184 ;
     RECT  38.545 45.264 38.729 57.576 ;
     RECT  38.185 22.032 38.801 24.744 ;
     RECT  38.689 80.4 38.801 89.736 ;
     RECT  38.153 43.872 38.837 43.896 ;
     RECT  37.609 6.864 38.844 19.08 ;
     RECT  38.801 22.992 38.844 24.744 ;
     RECT  38.152 29.136 38.844 38.28 ;
     RECT  38.729 45.264 38.844 57.48 ;
     RECT  38.693 64.464 38.844 67.464 ;
     RECT  37.901 70.608 38.844 76.68 ;
     RECT  38.801 80.592 38.844 89.736 ;
    LAYER M5 ;
     RECT  2.4 2.137 2.52 2.151 ;
     RECT  5.1 2.137 5.22 2.151 ;
     RECT  7.8 2.137 7.92 2.151 ;
     RECT  10.5 2.137 10.62 2.151 ;
     RECT  13.2 2.137 13.32 2.151 ;
     RECT  15.9 2.137 16.02 2.151 ;
     RECT  18.6 2.137 18.72 2.151 ;
     RECT  21.3 2.137 21.42 2.151 ;
     RECT  24 2.137 24.12 2.151 ;
     RECT  26.7 2.137 26.82 2.151 ;
     RECT  29.4 2.137 29.52 2.151 ;
     RECT  32.1 2.137 32.22 2.151 ;
     RECT  34.8 2.137 34.92 2.151 ;
     RECT  5.1 2.151 5.412 2.245 ;
     RECT  15.9 2.151 16.212 2.245 ;
     RECT  32.1 2.151 32.412 2.245 ;
     RECT  7.8 2.151 8.112 2.485 ;
     RECT  15.9 2.245 16.824 2.917 ;
     RECT  15.9 2.917 17.112 3.059 ;
     RECT  31.968 2.245 32.412 3.155 ;
     RECT  7.8 2.485 8.424 3.299 ;
     RECT  10.5 2.151 10.812 3.301 ;
     RECT  24 2.151 24.312 3.829 ;
     RECT  4.992 2.245 5.412 3.877 ;
     RECT  10.368 3.301 10.812 3.925 ;
     RECT  29.4 2.151 29.712 4.117 ;
     RECT  3.792 3.877 5.412 4.211 ;
     RECT  17.568 4.357 17.592 4.405 ;
     RECT  19.92 4.261 19.944 4.501 ;
     RECT  21.3 2.151 21.612 4.501 ;
     RECT  26.7 2.151 27.012 4.501 ;
     RECT  29.28 4.117 29.712 4.693 ;
     RECT  15.9 3.059 16.212 4.789 ;
     RECT  17.28 4.405 17.592 4.789 ;
     RECT  28.608 4.693 29.712 4.835 ;
     RECT  7.8 3.299 8.112 4.981 ;
     RECT  26.016 4.501 27.012 4.981 ;
     RECT  32.1 3.155 32.412 5.077 ;
     RECT  18.6 2.151 18.912 5.317 ;
     RECT  19.92 4.501 21.612 5.317 ;
     RECT  18.6 5.317 21.612 5.461 ;
     RECT  29.088 4.835 29.712 5.461 ;
     RECT  4.032 4.211 5.412 5.507 ;
     RECT  9.792 3.925 10.812 5.701 ;
     RECT  18.6 5.461 22.008 5.747 ;
     RECT  9.216 5.701 10.812 5.749 ;
     RECT  15.9 4.789 17.592 5.845 ;
     RECT  18.6 5.747 19.944 5.845 ;
     RECT  29.088 5.461 29.832 5.891 ;
     RECT  15.9 5.845 19.944 6.035 ;
     RECT  4.08 5.507 5.412 6.133 ;
     RECT  6.864 4.981 8.112 6.133 ;
     RECT  4.08 6.133 8.112 6.179 ;
     RECT  13.2 2.151 13.512 6.229 ;
     RECT  14.784 5.749 14.808 6.229 ;
     RECT  15.9 6.035 19.704 6.229 ;
     RECT  26.016 4.981 27.624 6.229 ;
     RECT  26.016 6.229 27.672 6.275 ;
     RECT  13.2 6.229 13.608 6.277 ;
     RECT  14.784 6.229 19.704 6.277 ;
     RECT  31.2 5.077 32.412 6.277 ;
     RECT  4.08 6.179 6.264 6.323 ;
     RECT  11.952 4.693 11.976 6.323 ;
     RECT  31.2 6.277 32.52 6.371 ;
     RECT  7.392 6.179 8.112 6.709 ;
     RECT  9.12 5.749 10.812 6.709 ;
     RECT  21.12 5.747 22.008 6.805 ;
     RECT  13.2 6.277 19.704 6.851 ;
     RECT  26.7 6.275 27.672 7.331 ;
     RECT  13.2 6.851 18.912 7.475 ;
     RECT  13.2 7.475 16.488 7.523 ;
     RECT  5.1 6.323 6.264 7.859 ;
     RECT  17.568 7.475 18.912 7.957 ;
     RECT  29.184 5.891 29.832 7.957 ;
     RECT  30.816 7.045 30.84 7.957 ;
     RECT  31.92 6.371 32.52 7.957 ;
     RECT  17.568 7.957 19.896 8.003 ;
     RECT  21.024 6.805 22.008 8.053 ;
     RECT  25.68 6.805 25.704 8.099 ;
     RECT  31.92 7.957 32.568 8.197 ;
     RECT  20.976 8.053 22.008 8.339 ;
     RECT  31.92 8.197 32.664 8.341 ;
     RECT  26.7 7.331 27.624 8.437 ;
     RECT  29.184 7.957 30.84 8.437 ;
     RECT  4.08 6.323 4.104 8.485 ;
     RECT  7.392 6.709 10.812 8.579 ;
     RECT  23.52 3.829 24.312 8.819 ;
     RECT  23.856 8.819 24.312 8.963 ;
     RECT  3.936 8.485 4.104 9.011 ;
     RECT  31.92 8.341 33.24 9.011 ;
     RECT  18.192 8.003 19.896 9.059 ;
     RECT  5.1 7.859 5.412 9.061 ;
     RECT  7.68 8.579 10.812 9.061 ;
     RECT  11.904 8.773 11.928 9.061 ;
     RECT  18.192 9.059 19.032 9.203 ;
     RECT  26.7 8.437 30.84 9.203 ;
     RECT  4.08 9.011 4.104 9.253 ;
     RECT  5.1 9.061 6.264 9.253 ;
     RECT  7.68 9.061 11.928 9.637 ;
     RECT  13.2 7.523 16.212 9.637 ;
     RECT  28.464 9.203 30.84 9.779 ;
     RECT  4.08 9.253 6.264 9.829 ;
     RECT  7.632 9.637 16.212 9.829 ;
     RECT  24 8.963 24.312 10.117 ;
     RECT  21.072 8.339 22.008 10.165 ;
     RECT  4.08 9.829 16.212 10.307 ;
     RECT  7.2 10.307 16.212 10.645 ;
     RECT  23.904 10.117 24.312 10.883 ;
     RECT  18.24 9.203 19.032 10.885 ;
     RECT  7.2 10.645 16.344 11.027 ;
     RECT  7.68 11.027 16.344 11.125 ;
     RECT  31.968 9.011 33.24 11.171 ;
     RECT  0.192 11.029 0.216 11.219 ;
     RECT  20.352 10.165 22.008 11.221 ;
     RECT  31.968 11.171 32.412 11.221 ;
     RECT  20.352 11.221 22.248 11.267 ;
     RECT  7.68 11.125 16.824 11.315 ;
     RECT  4.08 10.307 6.12 11.363 ;
     RECT  7.68 11.315 16.68 11.459 ;
     RECT  28.464 9.779 30.504 11.461 ;
     RECT  7.68 11.459 13.656 11.507 ;
     RECT  26.7 9.203 27.012 11.557 ;
     RECT  11.952 11.507 13.656 11.795 ;
     RECT  11.952 11.795 13.608 11.891 ;
     RECT  28.416 11.461 30.504 11.939 ;
     RECT  24 10.883 24.312 11.941 ;
     RECT  20.784 11.267 22.248 12.083 ;
     RECT  24 11.941 24.504 12.083 ;
     RECT  26.112 11.557 27.012 12.083 ;
     RECT  20.784 12.083 21.912 12.131 ;
     RECT  14.784 11.459 16.68 12.275 ;
     RECT  34.8 2.151 35.112 12.325 ;
     RECT  4.512 11.363 6.12 12.469 ;
     RECT  26.7 12.083 27.012 12.517 ;
     RECT  28.416 11.939 30.12 12.517 ;
     RECT  11.952 11.891 13.512 12.899 ;
     RECT  26.7 12.517 30.12 12.901 ;
     RECT  31.824 11.221 32.412 12.997 ;
     RECT  34.8 12.325 35.208 13.093 ;
     RECT  4.512 12.469 6.264 13.139 ;
     RECT  4.512 13.139 6.12 13.187 ;
     RECT  18.24 10.885 19.08 13.429 ;
     RECT  26.7 12.901 30.312 13.523 ;
     RECT  18.24 13.429 19.368 13.571 ;
     RECT  31.344 12.997 32.412 13.571 ;
     RECT  7.68 11.507 10.92 13.573 ;
     RECT  11.952 12.899 12.024 13.573 ;
     RECT  24 12.083 24.312 13.573 ;
     RECT  31.44 13.571 32.412 13.573 ;
     RECT  4.512 13.187 6.072 13.619 ;
     RECT  18.384 13.571 19.368 13.619 ;
     RECT  29.4 13.523 30.312 13.619 ;
     RECT  7.68 13.573 12.024 13.621 ;
     RECT  26.7 13.523 27.96 13.621 ;
     RECT  21.12 12.131 21.912 13.669 ;
     RECT  21.072 13.669 21.912 13.909 ;
     RECT  13.104 12.899 13.512 14.003 ;
     RECT  26.448 13.621 27.96 14.099 ;
     RECT  7.584 13.621 12.024 14.197 ;
     RECT  20.592 13.909 21.912 14.197 ;
     RECT  2.4 2.151 2.712 14.389 ;
     RECT  7.392 14.197 12.024 14.485 ;
     RECT  29.4 13.619 29.712 14.581 ;
     RECT  7.344 14.485 12.024 14.725 ;
     RECT  20.544 14.197 21.912 14.773 ;
     RECT  23.136 13.573 24.312 14.773 ;
     RECT  6.672 14.725 12.024 14.819 ;
     RECT  20.544 14.773 24.312 14.819 ;
     RECT  31.44 13.573 32.904 14.915 ;
     RECT  26.448 14.099 27.912 15.013 ;
     RECT  2.4 14.389 3.336 15.061 ;
     RECT  4.512 13.619 5.412 15.061 ;
     RECT  14.784 12.275 16.212 15.109 ;
     RECT  25.584 15.013 27.912 15.155 ;
     RECT  14.784 15.109 17.112 15.251 ;
     RECT  13.2 14.003 13.512 15.301 ;
     RECT  14.784 15.251 16.212 15.301 ;
     RECT  18.48 13.619 19.368 15.301 ;
     RECT  2.4 15.061 5.412 15.349 ;
     RECT  6.672 14.819 8.712 15.349 ;
     RECT  31.44 14.915 32.412 15.349 ;
     RECT  17.616 15.301 19.368 15.491 ;
     RECT  26.448 15.155 27.912 15.635 ;
     RECT  9.888 14.819 12.024 15.637 ;
     RECT  13.104 15.301 16.212 15.637 ;
     RECT  34.224 13.093 35.208 15.637 ;
     RECT  9.888 15.637 16.212 16.067 ;
     RECT  34.224 15.637 35.688 16.165 ;
     RECT  2.4 15.349 8.712 16.259 ;
     RECT  31.344 15.349 32.412 16.261 ;
     RECT  33.456 16.165 35.688 16.261 ;
     RECT  9.888 16.067 14.808 16.595 ;
     RECT  31.344 16.261 35.688 16.595 ;
     RECT  20.544 14.819 22.824 16.643 ;
     RECT  28.896 14.581 29.712 16.643 ;
     RECT  9.888 16.595 14.52 16.691 ;
     RECT  21.072 16.643 22.824 16.691 ;
     RECT  22.8 16.691 22.824 16.883 ;
     RECT  37.008 16.789 37.032 17.123 ;
     RECT  31.344 16.595 33.48 17.413 ;
     RECT  34.8 16.595 35.688 17.507 ;
     RECT  2.4 16.259 5.688 17.605 ;
     RECT  6.864 16.259 8.712 17.605 ;
     RECT  13.2 16.691 14.52 17.605 ;
     RECT  15.9 16.067 16.212 17.605 ;
     RECT  38.688 17.461 38.712 17.651 ;
     RECT  29.088 16.643 29.712 18.133 ;
     RECT  24 14.819 24.312 18.181 ;
     RECT  31.296 17.413 33.48 18.323 ;
     RECT  26.448 15.635 27.672 18.421 ;
     RECT  2.4 17.605 8.712 18.469 ;
     RECT  9.888 16.691 12.216 18.709 ;
     RECT  13.2 17.605 16.212 18.709 ;
     RECT  17.616 15.491 18.912 18.709 ;
     RECT  29.088 18.133 30.072 18.709 ;
     RECT  21.072 16.691 21.816 18.757 ;
     RECT  38.688 18.613 38.712 18.803 ;
     RECT  9.888 18.709 18.912 18.947 ;
     RECT  2.4 18.469 8.856 18.949 ;
     RECT  9.888 18.947 12.216 18.949 ;
     RECT  24 18.181 24.552 18.995 ;
     RECT  26.208 18.421 27.672 19.093 ;
     RECT  29.088 18.709 30.792 19.093 ;
     RECT  13.2 18.947 18.912 19.333 ;
     RECT  26.208 19.093 30.792 19.333 ;
     RECT  2.4 18.949 12.216 19.427 ;
     RECT  4.608 19.427 8.856 19.667 ;
     RECT  21.072 18.757 22.056 19.811 ;
     RECT  21.168 19.811 22.056 20.003 ;
     RECT  13.2 19.333 19.848 20.195 ;
     RECT  25.68 19.333 30.792 20.339 ;
     RECT  9.888 19.427 12.216 20.389 ;
     RECT  13.2 20.195 19.032 20.389 ;
     RECT  9.888 20.389 19.032 20.435 ;
     RECT  9.888 20.435 14.28 20.579 ;
     RECT  29.04 20.339 30.792 20.579 ;
     RECT  24 18.995 24.408 20.581 ;
     RECT  25.68 20.339 27.672 20.581 ;
     RECT  9.888 20.579 12.12 20.723 ;
     RECT  13.104 20.579 14.28 20.723 ;
     RECT  15.408 20.435 19.032 20.819 ;
     RECT  2.4 19.427 3.528 20.869 ;
     RECT  4.608 19.667 5.832 20.869 ;
     RECT  2.4 20.869 5.832 21.155 ;
     RECT  32.1 18.323 33.48 21.155 ;
     RECT  21.168 20.003 21.816 21.203 ;
     RECT  0.144 20.965 0.168 21.251 ;
     RECT  13.2 20.723 14.28 21.299 ;
     RECT  32.1 21.155 33.288 21.637 ;
     RECT  2.4 21.155 2.904 21.683 ;
     RECT  7.2 19.667 8.856 21.683 ;
     RECT  21.168 21.203 21.72 21.779 ;
     RECT  13.2 21.299 13.752 22.115 ;
     RECT  31.872 21.637 33.288 22.117 ;
     RECT  31.872 22.117 33.672 22.163 ;
     RECT  7.8 21.683 8.856 22.165 ;
     RECT  10.5 20.723 12.12 22.165 ;
     RECT  4.128 21.155 5.832 22.259 ;
     RECT  24 20.581 27.672 22.259 ;
     RECT  34.8 17.507 35.352 22.501 ;
     RECT  33.648 22.163 33.672 22.549 ;
     RECT  34.8 22.501 35.4 22.549 ;
     RECT  31.872 22.163 32.412 22.595 ;
     RECT  29.04 20.579 30.072 22.597 ;
     RECT  2.4 21.683 2.712 22.645 ;
     RECT  4.128 22.259 5.736 22.645 ;
     RECT  15.9 20.819 19.032 22.739 ;
     RECT  21.3 21.779 21.72 22.741 ;
     RECT  24 22.259 24.312 22.741 ;
     RECT  21.12 22.741 21.72 22.837 ;
     RECT  21.12 22.837 21.768 22.885 ;
     RECT  21.12 22.885 22.296 22.981 ;
     RECT  29.04 22.597 30.36 23.027 ;
     RECT  21.072 22.981 22.296 23.077 ;
     RECT  32.1 22.595 32.412 23.173 ;
     RECT  33.648 22.549 35.4 23.173 ;
     RECT  15.9 22.739 17.208 23.317 ;
     RECT  20.112 23.077 22.296 23.317 ;
     RECT  23.568 22.741 24.312 23.317 ;
     RECT  25.344 22.259 27.672 23.363 ;
     RECT  2.4 22.645 5.736 23.411 ;
     RECT  2.4 23.411 5.688 23.459 ;
     RECT  29.28 23.027 30.36 23.557 ;
     RECT  7.8 22.165 12.12 23.605 ;
     RECT  13.2 22.115 13.656 23.605 ;
     RECT  26.7 23.363 27.672 23.699 ;
     RECT  29.28 23.557 30.552 23.747 ;
     RECT  20.112 23.317 24.312 23.797 ;
     RECT  25.296 23.413 25.32 23.797 ;
     RECT  7.8 23.605 13.656 23.893 ;
     RECT  7.8 23.893 13.848 23.939 ;
     RECT  32.1 23.173 35.4 23.939 ;
     RECT  20.112 23.797 25.32 24.083 ;
     RECT  21.072 24.083 25.32 24.227 ;
     RECT  33.888 23.939 35.4 24.277 ;
     RECT  7.8 23.939 8.328 24.325 ;
     RECT  18.288 22.739 19.032 24.373 ;
     RECT  21.072 24.227 24.312 24.563 ;
     RECT  9.312 23.939 13.848 24.659 ;
     RECT  2.4 23.459 3.48 24.805 ;
     RECT  4.512 23.459 5.688 24.805 ;
     RECT  9.312 24.659 9.528 24.899 ;
     RECT  29.28 23.747 30.36 24.901 ;
     RECT  15.792 23.317 17.208 25.091 ;
     RECT  9.504 24.899 9.528 25.187 ;
     RECT  21.12 24.563 22.296 25.187 ;
     RECT  18.288 24.373 19.368 25.189 ;
     RECT  15.792 25.091 16.968 25.237 ;
     RECT  18.288 25.189 19.512 25.331 ;
     RECT  28.512 24.901 30.36 25.331 ;
     RECT  32.1 23.939 32.412 25.525 ;
     RECT  7.68 24.325 8.328 25.813 ;
     RECT  25.296 24.227 25.32 26.051 ;
     RECT  2.4 24.805 5.688 26.243 ;
     RECT  7.68 25.813 8.376 26.245 ;
     RECT  2.4 26.243 3.096 26.291 ;
     RECT  4.416 26.243 5.688 26.291 ;
     RECT  7.68 26.245 8.424 26.387 ;
     RECT  18.288 25.331 19.368 26.387 ;
     RECT  29.4 25.331 30.36 26.485 ;
     RECT  10.5 24.659 13.848 26.533 ;
     RECT  18.384 26.387 19.368 26.629 ;
     RECT  26.7 23.699 27.336 26.675 ;
     RECT  31.968 25.525 32.412 26.677 ;
     RECT  33.888 24.277 35.64 26.723 ;
     RECT  18.384 26.629 19.464 26.725 ;
     RECT  34.032 26.723 35.64 26.725 ;
     RECT  34.032 26.725 35.688 26.771 ;
     RECT  29.4 26.485 30.696 26.773 ;
     RECT  2.4 26.291 2.904 26.819 ;
     RECT  21.12 25.187 22.2 26.819 ;
     RECT  23.568 24.563 24.312 26.821 ;
     RECT  26.7 26.675 27.24 26.869 ;
     RECT  31.968 26.677 32.616 26.869 ;
     RECT  10.5 26.533 14.184 27.109 ;
     RECT  4.416 26.291 5.64 27.253 ;
     RECT  7.68 26.387 8.376 27.397 ;
     RECT  15.312 25.237 16.968 27.443 ;
     RECT  7.2 27.397 8.376 27.493 ;
     RECT  4.416 27.253 5.688 27.587 ;
     RECT  10.5 27.109 14.232 27.635 ;
     RECT  31.92 26.869 32.616 27.635 ;
     RECT  26.352 26.869 27.24 27.685 ;
     RECT  18.384 26.725 20.088 27.829 ;
     RECT  21.12 26.819 21.612 27.829 ;
     RECT  2.4 26.819 2.712 27.877 ;
     RECT  7.104 27.493 8.376 27.877 ;
     RECT  15.9 27.443 16.968 27.877 ;
     RECT  18.384 27.829 21.612 27.877 ;
     RECT  32.1 27.635 32.616 27.923 ;
     RECT  11.904 27.635 14.232 27.925 ;
     RECT  26.208 27.685 27.24 27.925 ;
     RECT  10.5 27.635 10.812 28.021 ;
     RECT  34.8 26.771 35.688 28.115 ;
     RECT  15.9 27.877 21.612 28.165 ;
     RECT  28.512 26.773 30.696 28.307 ;
     RECT  10.368 28.021 10.812 28.405 ;
     RECT  26.064 27.925 27.24 28.451 ;
     RECT  4.512 27.587 5.688 28.453 ;
     RECT  6.864 27.877 8.376 28.453 ;
     RECT  2.4 27.877 3.432 28.547 ;
     RECT  4.512 28.453 8.376 28.547 ;
     RECT  9.6 28.405 10.812 28.739 ;
     RECT  11.904 27.925 14.808 28.981 ;
     RECT  15.9 28.165 22.392 28.981 ;
     RECT  11.904 28.981 22.392 29.029 ;
     RECT  11.856 29.029 22.392 29.219 ;
     RECT  23.568 26.821 25.032 29.363 ;
     RECT  4.8 28.547 8.376 29.365 ;
     RECT  11.856 29.219 20.04 29.605 ;
     RECT  28.8 28.307 30.696 29.605 ;
     RECT  21.12 29.219 22.392 30.083 ;
     RECT  26.064 28.451 27.012 30.083 ;
     RECT  24 29.363 25.032 30.181 ;
     RECT  32.1 27.923 32.52 30.181 ;
     RECT  26.112 30.083 27.012 30.227 ;
     RECT  11.808 29.605 20.04 30.371 ;
     RECT  10.5 28.739 10.812 30.373 ;
     RECT  11.808 30.371 16.44 30.419 ;
     RECT  28.8 29.605 31.032 30.757 ;
     RECT  17.568 30.371 20.04 30.853 ;
     RECT  21.12 30.083 21.612 30.853 ;
     RECT  11.856 30.419 16.44 30.899 ;
     RECT  26.7 30.227 27.012 30.901 ;
     RECT  28.032 30.757 31.032 30.901 ;
     RECT  4.8 29.365 8.52 30.949 ;
     RECT  9.648 30.373 10.812 30.949 ;
     RECT  11.856 30.899 16.212 30.995 ;
     RECT  34.8 28.115 35.112 31.285 ;
     RECT  13.104 30.995 16.212 31.379 ;
     RECT  17.568 30.853 21.612 31.379 ;
     RECT  26.7 30.901 31.032 31.573 ;
     RECT  32.1 30.181 33 31.573 ;
     RECT  4.8 30.949 10.812 31.957 ;
     RECT  11.856 30.995 11.88 31.957 ;
     RECT  24 30.181 25.128 31.957 ;
     RECT  26.7 31.573 33 32.003 ;
     RECT  31.248 32.003 33 32.053 ;
     RECT  13.104 31.379 14.856 32.099 ;
     RECT  4.8 31.957 11.976 32.243 ;
     RECT  31.248 32.053 33.096 32.483 ;
     RECT  17.616 31.379 21.612 32.531 ;
     RECT  23.904 31.957 25.128 32.531 ;
     RECT  21.12 32.531 21.612 32.771 ;
     RECT  4.8 32.243 10.968 33.011 ;
     RECT  23.904 32.531 24.552 33.107 ;
     RECT  4.8 33.011 10.812 33.109 ;
     RECT  13.2 32.099 14.856 33.109 ;
     RECT  15.9 31.379 16.212 33.349 ;
     RECT  17.616 32.531 19.992 33.349 ;
     RECT  13.104 33.109 14.856 33.395 ;
     RECT  11.952 32.243 11.976 33.683 ;
     RECT  26.7 32.003 29.712 33.683 ;
     RECT  21.168 32.771 21.612 33.731 ;
     RECT  28.032 33.683 29.712 33.923 ;
     RECT  31.248 32.483 33 33.923 ;
     RECT  28.464 33.923 29.712 34.069 ;
     RECT  31.248 33.923 32.952 34.069 ;
     RECT  15.9 33.349 19.992 34.117 ;
     RECT  4.032 33.109 10.812 34.691 ;
     RECT  15.9 34.117 20.04 34.691 ;
     RECT  13.2 33.395 14.856 34.693 ;
     RECT  15.9 34.691 17.16 34.693 ;
     RECT  13.2 34.693 17.16 34.741 ;
     RECT  21.3 33.731 21.612 34.741 ;
     RECT  4.032 34.691 9.096 34.787 ;
     RECT  4.032 34.787 4.056 34.835 ;
     RECT  28.464 34.069 32.952 34.835 ;
     RECT  22.896 32.965 22.92 34.931 ;
     RECT  26.7 33.683 27.012 35.173 ;
     RECT  28.464 34.835 30.504 35.173 ;
     RECT  26.7 35.173 30.504 35.315 ;
     RECT  2.4 28.547 2.712 35.317 ;
     RECT  3.936 34.837 3.96 35.317 ;
     RECT  34.32 31.285 35.112 35.317 ;
     RECT  2.4 35.317 3.96 35.459 ;
     RECT  18.6 34.691 20.04 35.509 ;
     RECT  21.168 34.741 21.612 35.509 ;
     RECT  32.1 34.835 32.952 35.701 ;
     RECT  33.984 35.317 35.112 35.701 ;
     RECT  18.6 35.509 21.612 35.939 ;
     RECT  28.464 35.315 30.504 36.085 ;
     RECT  38.64 36.037 38.664 36.371 ;
     RECT  10.5 34.691 10.812 36.421 ;
     RECT  5.1 34.787 9.096 36.515 ;
     RECT  12.72 34.741 17.16 36.515 ;
     RECT  32.1 35.701 35.112 36.515 ;
     RECT  10.224 36.421 10.812 36.517 ;
     RECT  24 33.107 24.552 36.611 ;
     RECT  12.72 36.515 13.848 36.613 ;
     RECT  14.928 36.515 17.16 36.613 ;
     RECT  18.6 35.939 20.04 36.613 ;
     RECT  28.464 36.085 30.744 36.613 ;
     RECT  28.464 36.613 30.84 36.659 ;
     RECT  5.1 36.515 6.456 36.853 ;
     RECT  29.4 36.659 30.84 36.949 ;
     RECT  24 36.611 24.408 36.997 ;
     RECT  10.224 36.517 11.448 37.091 ;
     RECT  12.576 36.613 13.848 37.091 ;
     RECT  4.8 36.853 6.456 37.139 ;
     RECT  29.4 36.949 31.128 37.331 ;
     RECT  14.928 36.613 20.04 37.427 ;
     RECT  18.24 37.427 20.04 37.573 ;
     RECT  21.168 35.939 21.612 37.573 ;
     RECT  32.1 36.515 33.048 37.667 ;
     RECT  30.816 37.331 31.128 37.669 ;
     RECT  32.1 37.667 33 37.669 ;
     RECT  14.928 37.427 17.16 37.715 ;
     RECT  10.5 37.091 11.448 37.763 ;
     RECT  30.816 37.669 33 37.763 ;
     RECT  29.4 37.331 29.712 37.861 ;
     RECT  30.816 37.763 30.84 37.907 ;
     RECT  23.088 36.997 24.408 38.003 ;
     RECT  31.92 37.763 33 38.291 ;
     RECT  29.28 37.861 29.712 38.437 ;
     RECT  7.44 36.515 9.096 38.819 ;
     RECT  2.4 35.459 3.288 38.963 ;
     RECT  23.088 38.003 24.312 39.013 ;
     RECT  28.944 38.437 29.712 39.013 ;
     RECT  12.576 37.091 13.512 39.061 ;
     RECT  18.24 37.573 21.612 39.205 ;
     RECT  31.92 38.291 32.412 39.301 ;
     RECT  23.088 39.013 25.176 39.491 ;
     RECT  15.9 37.715 17.16 39.493 ;
     RECT  18.24 39.205 22.008 39.493 ;
     RECT  34.224 36.515 35.112 39.541 ;
     RECT  12.576 39.061 13.608 39.685 ;
     RECT  15.9 39.493 22.008 39.779 ;
     RECT  7.8 38.819 8.904 39.781 ;
     RECT  4.8 37.139 6.216 39.877 ;
     RECT  7.2 39.781 8.904 39.877 ;
     RECT  28.752 39.013 29.712 39.877 ;
     RECT  4.8 39.877 8.904 40.021 ;
     RECT  12 39.685 13.608 40.309 ;
     RECT  4.8 40.021 9.096 40.499 ;
     RECT  15.9 39.779 19.848 40.547 ;
     RECT  5.1 40.499 9.096 40.837 ;
     RECT  23.088 39.491 24.312 41.027 ;
     RECT  28.752 39.877 30.216 41.075 ;
     RECT  10.5 37.763 10.812 41.413 ;
     RECT  18.48 40.547 19.848 41.509 ;
     RECT  21.12 39.779 22.008 41.509 ;
     RECT  10.368 41.413 10.812 41.699 ;
     RECT  10.5 41.699 10.812 42.085 ;
     RECT  12 40.309 13.656 42.085 ;
     RECT  15.9 40.547 17.496 42.133 ;
     RECT  18.48 41.509 22.008 42.133 ;
     RECT  31.872 39.301 32.412 42.181 ;
     RECT  24 41.027 24.312 42.469 ;
     RECT  25.44 40.981 25.464 42.469 ;
     RECT  5.1 40.837 9.192 42.515 ;
     RECT  0.192 30.565 0.216 42.757 ;
     RECT  0.192 42.757 0.312 42.803 ;
     RECT  24 42.469 25.464 42.901 ;
     RECT  26.7 35.315 27.012 42.901 ;
     RECT  15.9 42.133 22.152 42.995 ;
     RECT  10.5 42.085 13.656 43.043 ;
     RECT  28.752 41.075 29.712 43.189 ;
     RECT  5.1 42.515 9.048 43.235 ;
     RECT  10.5 43.043 12.024 43.283 ;
     RECT  31.104 42.181 32.412 43.379 ;
     RECT  31.104 43.379 31.128 43.523 ;
     RECT  32.1 43.379 32.412 43.525 ;
     RECT  33.936 39.541 35.112 43.525 ;
     RECT  32.1 43.525 35.112 43.571 ;
     RECT  21.168 42.995 22.152 43.811 ;
     RECT  5.1 43.235 6.216 43.861 ;
     RECT  24 42.901 27.012 43.907 ;
     RECT  26.16 43.907 27.012 44.003 ;
     RECT  2.4 38.963 2.712 44.053 ;
     RECT  2.304 44.053 2.712 44.243 ;
     RECT  7.2 43.235 9.048 44.483 ;
     RECT  14.832 42.325 14.856 44.483 ;
     RECT  10.5 43.283 11.688 44.531 ;
     RECT  4.608 43.861 6.216 44.581 ;
     RECT  7.2 44.483 8.52 44.581 ;
     RECT  0.288 42.803 0.312 44.677 ;
     RECT  28.608 43.189 29.712 44.723 ;
     RECT  13.056 43.043 13.656 44.917 ;
     RECT  0.288 44.677 1.176 44.963 ;
     RECT  26.7 44.003 27.012 44.965 ;
     RECT  26.7 44.965 27.144 45.107 ;
     RECT  32.1 43.571 33.528 45.155 ;
     RECT  0.288 44.963 0.312 45.251 ;
     RECT  32.1 45.155 33.288 45.395 ;
     RECT  32.1 45.395 32.412 45.445 ;
     RECT  4.608 44.581 8.52 45.685 ;
     RECT  15.9 42.995 19.944 45.973 ;
     RECT  21.168 43.811 21.612 45.973 ;
     RECT  15.9 45.973 21.612 46.115 ;
     RECT  31.584 45.445 32.412 46.213 ;
     RECT  1.152 46.165 1.176 46.355 ;
     RECT  21.168 46.115 21.612 46.451 ;
     RECT  22.8 45.973 22.824 46.597 ;
     RECT  22.8 46.597 22.92 46.643 ;
     RECT  15.9 46.115 19.944 46.885 ;
     RECT  4.608 45.685 9.096 47.029 ;
     RECT  10.5 44.531 11.448 47.029 ;
     RECT  12.912 44.917 13.656 47.029 ;
     RECT  4.128 47.029 9.096 47.075 ;
     RECT  15.792 46.885 19.944 47.125 ;
     RECT  15.792 47.125 20.088 47.267 ;
     RECT  34.8 43.571 35.112 47.269 ;
     RECT  7.392 47.075 9.096 47.363 ;
     RECT  22.896 46.643 22.92 47.461 ;
     RECT  21.3 46.451 21.612 47.557 ;
     RECT  28.656 44.723 29.712 47.557 ;
     RECT  22.896 47.461 22.968 47.749 ;
     RECT  21.168 47.557 21.612 47.845 ;
     RECT  22.8 47.749 22.968 47.845 ;
     RECT  26.7 45.107 27.012 47.941 ;
     RECT  26.112 47.941 27.012 47.989 ;
     RECT  28.512 47.557 29.712 47.989 ;
     RECT  4.128 47.075 6.264 48.131 ;
     RECT  26.112 47.989 29.712 48.131 ;
     RECT  10.5 47.029 13.656 48.227 ;
     RECT  15.792 47.267 19.944 48.229 ;
     RECT  21.168 47.845 22.968 48.229 ;
     RECT  7.392 47.363 8.52 48.421 ;
     RECT  28.512 48.131 29.712 48.659 ;
     RECT  24 43.907 24.504 48.757 ;
     RECT  24 48.757 24.984 48.805 ;
     RECT  5.1 48.131 6.264 48.853 ;
     RECT  7.392 48.421 9.144 48.853 ;
     RECT  2.4 44.243 2.712 48.901 ;
     RECT  31.296 46.213 32.412 48.901 ;
     RECT  24 48.805 25.128 48.947 ;
     RECT  15.792 48.229 22.968 48.949 ;
     RECT  24 48.947 24.984 48.949 ;
     RECT  15.792 48.949 24.984 49.043 ;
     RECT  31.296 48.901 33.048 49.043 ;
     RECT  5.1 48.853 9.144 49.091 ;
     RECT  11.952 48.227 13.656 49.091 ;
     RECT  26.112 48.131 27.012 49.139 ;
     RECT  1.152 48.997 1.176 49.187 ;
     RECT  7.44 49.091 9.144 49.187 ;
     RECT  34.8 47.269 35.352 49.189 ;
     RECT  7.44 49.187 8.52 49.235 ;
     RECT  34.608 49.189 35.352 49.235 ;
     RECT  15.792 49.043 24.312 49.619 ;
     RECT  34.608 49.235 35.112 49.763 ;
     RECT  20.64 49.619 24.312 50.005 ;
     RECT  0.144 49.813 0.168 50.099 ;
     RECT  5.1 49.091 6.264 50.101 ;
     RECT  2.4 48.901 3.48 50.437 ;
     RECT  4.944 50.101 6.264 50.437 ;
     RECT  12 49.091 13.656 50.531 ;
     RECT  25.68 50.005 25.704 50.533 ;
     RECT  2.4 50.437 6.264 50.579 ;
     RECT  20.64 50.005 24.408 50.579 ;
     RECT  7.8 49.235 8.52 50.677 ;
     RECT  12 50.531 12.216 50.677 ;
     RECT  34.8 49.763 35.112 50.773 ;
     RECT  7.8 50.677 9.48 50.965 ;
     RECT  10.5 48.227 10.812 50.965 ;
     RECT  20.64 50.579 24.312 51.251 ;
     RECT  34.704 50.773 35.112 51.299 ;
     RECT  34.8 51.299 35.112 51.301 ;
     RECT  13.2 50.531 13.656 51.349 ;
     RECT  31.296 49.043 32.412 51.443 ;
     RECT  34.8 51.301 35.304 51.491 ;
     RECT  21.168 51.251 24.312 51.635 ;
     RECT  11.952 50.677 12.216 51.733 ;
     RECT  13.2 51.349 14.232 51.733 ;
     RECT  15.792 49.619 19.464 51.733 ;
     RECT  21.3 51.635 24.312 51.877 ;
     RECT  7.8 50.965 10.812 51.923 ;
     RECT  11.952 51.733 14.232 52.163 ;
     RECT  21.3 51.877 24.408 52.211 ;
     RECT  28.896 48.659 29.712 52.259 ;
     RECT  31.824 51.443 32.412 52.355 ;
     RECT  25.392 50.533 25.704 52.405 ;
     RECT  26.7 49.139 27.012 52.405 ;
     RECT  0.192 52.261 0.216 52.451 ;
     RECT  31.92 52.355 32.412 52.499 ;
     RECT  25.392 52.405 27.012 52.595 ;
     RECT  13.104 52.163 14.232 52.741 ;
     RECT  15.36 51.733 19.464 52.741 ;
     RECT  4.848 50.579 6.264 52.885 ;
     RECT  7.8 51.923 9.096 52.885 ;
     RECT  10.176 51.923 10.812 52.885 ;
     RECT  2.4 50.579 3.384 52.981 ;
     RECT  4.512 52.885 6.264 52.981 ;
     RECT  7.8 52.885 10.812 52.981 ;
     RECT  25.392 52.595 25.416 53.075 ;
     RECT  31.968 52.499 32.412 53.077 ;
     RECT  29.04 52.259 29.712 53.171 ;
     RECT  7.248 52.981 10.812 53.269 ;
     RECT  11.952 52.163 11.976 53.269 ;
     RECT  7.248 53.269 11.976 53.315 ;
     RECT  29.184 53.171 29.712 53.315 ;
     RECT  21.3 52.211 22.536 53.509 ;
     RECT  20.496 53.509 22.536 53.557 ;
     RECT  34.8 51.491 35.112 53.557 ;
     RECT  7.248 53.315 11.64 53.603 ;
     RECT  7.8 53.603 11.64 53.939 ;
     RECT  20.496 53.557 22.776 54.085 ;
     RECT  23.808 52.211 24.312 54.085 ;
     RECT  31.968 53.077 32.952 54.085 ;
     RECT  9.552 53.939 11.64 54.227 ;
     RECT  13.104 52.741 19.464 54.371 ;
     RECT  26.592 52.595 27.012 54.421 ;
     RECT  2.4 52.981 6.264 54.755 ;
     RECT  25.68 54.421 27.012 55.139 ;
     RECT  26.592 55.139 27.012 55.189 ;
     RECT  29.28 53.315 29.712 55.189 ;
     RECT  20.496 54.085 24.312 55.331 ;
     RECT  31.296 54.085 33.144 55.331 ;
     RECT  26.592 55.189 27.816 55.477 ;
     RECT  9.552 54.227 11.448 55.717 ;
     RECT  9.552 55.717 11.544 55.763 ;
     RECT  7.8 53.939 8.112 55.813 ;
     RECT  9.936 55.763 11.544 55.813 ;
     RECT  31.296 55.331 32.412 55.907 ;
     RECT  34.8 53.557 35.496 55.955 ;
     RECT  26.592 55.477 28.248 56.051 ;
     RECT  2.4 54.755 3.384 56.195 ;
     RECT  9.936 55.813 12.024 56.195 ;
     RECT  21.168 55.331 24.312 56.243 ;
     RECT  13.2 54.371 19.464 56.341 ;
     RECT  7.8 55.813 8.952 56.389 ;
     RECT  29.28 55.189 29.832 56.437 ;
     RECT  26.7 56.051 28.248 56.485 ;
     RECT  29.28 56.437 30.216 56.485 ;
     RECT  38.16 56.341 38.184 56.531 ;
     RECT  21.168 56.243 21.612 56.627 ;
     RECT  31.968 55.907 32.412 56.821 ;
     RECT  22.608 56.243 24.312 56.867 ;
     RECT  26.7 56.485 30.216 56.965 ;
     RECT  12 56.195 12.024 57.109 ;
     RECT  13.008 56.341 19.464 57.109 ;
     RECT  7.68 56.389 8.952 57.155 ;
     RECT  31.968 56.821 32.616 57.155 ;
     RECT  9.936 56.195 10.812 57.349 ;
     RECT  12 57.109 19.464 57.349 ;
     RECT  9.936 57.349 19.464 57.397 ;
     RECT  23.904 56.867 24.312 57.829 ;
     RECT  26.7 56.965 30.6 57.875 ;
     RECT  31.968 57.155 32.568 57.875 ;
     RECT  2.4 56.195 2.712 57.877 ;
     RECT  9.888 57.397 19.464 57.971 ;
     RECT  26.7 57.875 30.264 57.971 ;
     RECT  2.4 57.877 2.808 58.069 ;
     RECT  23.808 57.829 24.312 58.117 ;
     RECT  25.536 57.877 25.56 58.117 ;
     RECT  9.888 57.971 14.232 58.163 ;
     RECT  29.28 57.971 30.216 58.163 ;
     RECT  26.7 57.971 28.248 58.211 ;
     RECT  9.888 58.163 11.688 58.213 ;
     RECT  28.224 58.211 28.248 58.259 ;
     RECT  7.68 57.155 8.112 58.261 ;
     RECT  9.12 58.213 11.688 58.261 ;
     RECT  21.3 56.627 21.612 58.309 ;
     RECT  4.512 54.755 6.264 58.355 ;
     RECT  22.608 56.867 22.632 58.405 ;
     RECT  23.616 58.117 24.312 58.405 ;
     RECT  25.536 58.117 25.704 58.405 ;
     RECT  7.68 58.261 11.688 58.451 ;
     RECT  2.4 58.069 3.24 58.453 ;
     RECT  21.12 58.309 21.612 58.453 ;
     RECT  22.608 58.405 25.704 58.453 ;
     RECT  12.96 58.163 14.232 58.547 ;
     RECT  21.12 58.453 25.704 58.645 ;
     RECT  26.7 58.211 27.012 58.645 ;
     RECT  32.1 57.875 32.568 59.029 ;
     RECT  32.1 59.029 33.096 59.221 ;
     RECT  21.12 58.645 27.012 59.507 ;
     RECT  2.4 58.453 3.48 59.557 ;
     RECT  4.656 58.355 6.264 59.557 ;
     RECT  2.4 59.557 6.264 59.605 ;
     RECT  7.68 58.451 8.28 59.605 ;
     RECT  9.888 58.451 11.688 59.605 ;
     RECT  12.96 58.547 13.656 59.605 ;
     RECT  25.728 59.507 27.012 59.605 ;
     RECT  29.28 58.163 29.712 59.701 ;
     RECT  2.4 59.605 8.28 59.749 ;
     RECT  9.888 59.605 13.656 59.749 ;
     RECT  21.12 59.507 24.312 59.749 ;
     RECT  31.968 59.221 33.096 60.085 ;
     RECT  28.992 59.701 29.712 60.181 ;
     RECT  25.728 59.605 27.96 60.565 ;
     RECT  28.992 60.181 30.36 60.565 ;
     RECT  2.4 59.749 13.656 60.611 ;
     RECT  25.728 60.565 30.36 60.947 ;
     RECT  26.496 60.947 30.36 60.995 ;
     RECT  31.872 60.085 33.096 61.091 ;
     RECT  28.752 60.995 30.36 61.139 ;
     RECT  4.704 60.611 13.656 61.235 ;
     RECT  20.544 59.749 24.312 61.235 ;
     RECT  28.944 61.139 30.36 61.475 ;
     RECT  9.36 61.235 13.656 61.667 ;
     RECT  15.9 57.971 19.464 62.053 ;
     RECT  20.544 61.235 21.612 62.053 ;
     RECT  10.5 61.667 13.656 62.147 ;
     RECT  25.392 61.525 25.416 62.147 ;
     RECT  28.944 61.475 30.312 62.149 ;
     RECT  26.496 60.995 27.012 62.243 ;
     RECT  31.872 61.091 32.616 62.483 ;
     RECT  31.92 62.483 32.616 62.579 ;
     RECT  11.952 62.147 13.656 62.581 ;
     RECT  2.4 60.611 3.336 62.629 ;
     RECT  4.704 61.235 8.376 62.677 ;
     RECT  26.544 62.243 27.012 62.723 ;
     RECT  4.464 62.677 8.376 62.771 ;
     RECT  22.608 61.235 24.312 62.821 ;
     RECT  4.464 62.771 8.112 62.963 ;
     RECT  9.36 61.667 9.384 63.157 ;
     RECT  10.5 62.147 10.812 63.157 ;
     RECT  28.464 62.149 30.312 63.205 ;
     RECT  2.4 62.629 3.48 63.491 ;
     RECT  4.464 62.963 6.264 63.587 ;
     RECT  26.7 62.723 27.012 63.685 ;
     RECT  4.464 63.587 6.168 63.779 ;
     RECT  7.68 62.963 8.112 63.781 ;
     RECT  9.36 63.157 10.812 63.781 ;
     RECT  31.968 62.579 32.616 63.781 ;
     RECT  28.224 63.205 30.312 63.875 ;
     RECT  33.648 62.821 33.672 64.357 ;
     RECT  34.8 55.955 35.112 64.357 ;
     RECT  11.952 62.581 14.28 64.403 ;
     RECT  4.512 63.779 6.168 64.451 ;
     RECT  22.608 62.821 24.6 64.691 ;
     RECT  31.344 63.781 32.616 64.741 ;
     RECT  33.648 64.357 35.112 64.741 ;
     RECT  28.464 63.875 30.312 64.837 ;
     RECT  31.344 64.741 35.112 64.883 ;
     RECT  7.68 63.781 10.812 64.885 ;
     RECT  11.952 64.403 13.656 64.885 ;
     RECT  23.616 64.691 24.6 64.979 ;
     RECT  23.856 64.979 24.6 64.981 ;
     RECT  26.592 63.685 27.012 65.027 ;
     RECT  28.176 64.837 30.312 65.125 ;
     RECT  31.344 64.883 33.288 65.125 ;
     RECT  23.856 64.981 24.648 65.507 ;
     RECT  2.4 63.491 3.432 65.509 ;
     RECT  4.512 64.451 6.024 65.509 ;
     RECT  7.68 64.885 13.656 65.795 ;
     RECT  26.7 65.027 27.012 65.797 ;
     RECT  28.176 65.125 33.288 65.797 ;
     RECT  26.7 65.797 33.288 65.987 ;
     RECT  26.7 65.987 33.24 66.179 ;
     RECT  2.4 65.509 6.024 66.373 ;
     RECT  7.8 65.795 13.656 66.515 ;
     RECT  23.856 65.507 24.6 66.517 ;
     RECT  22.608 64.691 22.632 66.613 ;
     RECT  26.7 66.179 29.712 66.661 ;
     RECT  2.4 66.373 6.408 66.755 ;
     RECT  31.2 66.179 33.24 66.803 ;
     RECT  22.608 66.613 22.776 66.899 ;
     RECT  10.5 66.515 13.656 67.141 ;
     RECT  23.856 66.517 25.128 67.331 ;
     RECT  34.368 64.883 35.112 67.429 ;
     RECT  3.936 66.755 6.408 67.573 ;
     RECT  3.936 67.573 6.552 67.669 ;
     RECT  7.8 66.515 9.384 67.669 ;
     RECT  26.256 66.661 29.712 67.715 ;
     RECT  3.936 67.669 9.384 67.813 ;
     RECT  10.5 67.141 14.232 67.813 ;
     RECT  24 67.331 25.128 67.859 ;
     RECT  3.936 67.813 14.232 67.907 ;
     RECT  26.256 67.715 28.392 68.243 ;
     RECT  26.256 68.243 28.2 68.387 ;
     RECT  31.2 66.803 32.412 68.533 ;
     RECT  33.648 67.429 35.112 68.533 ;
     RECT  31.2 68.533 35.112 68.675 ;
     RECT  33.648 68.675 35.112 68.723 ;
     RECT  2.4 66.755 2.712 68.869 ;
     RECT  2.4 68.869 2.856 68.917 ;
     RECT  3.936 67.907 13.944 68.917 ;
     RECT  24 67.859 24.6 68.917 ;
     RECT  2.4 68.917 13.944 69.491 ;
     RECT  6.864 69.491 13.944 69.587 ;
     RECT  22.752 66.899 22.776 69.587 ;
     RECT  9.168 69.587 13.944 69.731 ;
     RECT  2.4 69.491 5.592 70.259 ;
     RECT  10.08 69.731 13.944 70.259 ;
     RECT  2.4 70.259 2.856 70.307 ;
     RECT  15.9 62.053 21.612 70.355 ;
     RECT  24 68.917 24.792 70.501 ;
     RECT  31.2 68.675 32.412 70.501 ;
     RECT  17.808 70.355 21.612 70.547 ;
     RECT  15.9 70.355 16.632 70.645 ;
     RECT  26.352 68.387 28.2 70.645 ;
     RECT  3.84 70.259 5.592 70.981 ;
     RECT  26.352 70.645 28.392 71.125 ;
     RECT  29.4 67.715 29.712 71.125 ;
     RECT  26.352 71.125 29.712 71.605 ;
     RECT  30.768 70.501 32.412 71.605 ;
     RECT  20.256 70.547 21.612 71.653 ;
     RECT  3.84 70.981 5.688 71.699 ;
     RECT  15.792 70.645 16.632 71.701 ;
     RECT  17.808 70.547 18.912 71.701 ;
     RECT  10.272 70.259 13.944 71.749 ;
     RECT  26.352 71.605 32.412 71.749 ;
     RECT  6.864 69.587 8.112 71.797 ;
     RECT  15.792 71.701 18.912 71.843 ;
     RECT  17.808 71.843 18.912 71.891 ;
     RECT  23.664 70.501 24.792 71.891 ;
     RECT  6.864 71.797 8.808 72.035 ;
     RECT  2.4 70.307 2.712 72.181 ;
     RECT  5.1 71.699 5.688 72.277 ;
     RECT  25.92 71.749 32.412 72.325 ;
     RECT  2.304 72.181 2.712 72.371 ;
     RECT  3.84 71.699 3.96 72.419 ;
     RECT  3.84 72.419 3.864 72.467 ;
     RECT  15.792 71.843 16.776 72.707 ;
     RECT  23.664 71.891 24.408 72.755 ;
     RECT  17.856 71.891 18.912 72.853 ;
     RECT  19.968 71.653 21.612 72.853 ;
     RECT  10.272 71.749 14.232 72.899 ;
     RECT  12.528 72.899 14.232 72.901 ;
     RECT  10.272 72.899 11.448 72.995 ;
     RECT  7.296 72.035 8.808 73.091 ;
     RECT  12.528 72.901 14.76 73.283 ;
     RECT  33.792 68.723 35.112 73.283 ;
     RECT  25.728 72.325 32.412 73.285 ;
     RECT  17.856 72.853 21.612 73.333 ;
     RECT  24 72.755 24.408 73.333 ;
     RECT  7.344 73.091 8.808 73.477 ;
     RECT  25.728 73.285 32.52 73.477 ;
     RECT  34.224 73.283 35.112 73.523 ;
     RECT  15.9 72.707 16.776 73.765 ;
     RECT  12.96 73.283 14.76 73.811 ;
     RECT  25.728 73.477 33.048 73.811 ;
     RECT  25.728 73.811 30.216 73.957 ;
     RECT  15.792 73.765 16.776 74.053 ;
     RECT  7.344 73.477 9 74.147 ;
     RECT  31.2 73.811 33.048 74.147 ;
     RECT  5.1 72.277 6.264 74.195 ;
     RECT  31.392 74.147 33.048 74.195 ;
     RECT  7.8 74.147 9 74.435 ;
     RECT  17.856 73.333 21.768 74.483 ;
     RECT  31.392 74.195 32.52 74.483 ;
     RECT  10.5 72.995 11.448 74.485 ;
     RECT  15.696 74.053 16.776 74.581 ;
     RECT  24 73.333 24.504 74.629 ;
     RECT  25.68 73.957 30.216 74.629 ;
     RECT  31.392 74.483 32.412 74.675 ;
     RECT  24 74.629 30.216 74.723 ;
     RECT  12.96 73.811 14.712 74.771 ;
     RECT  28.56 74.723 30.216 74.915 ;
     RECT  18.192 74.483 21.768 75.107 ;
     RECT  4.032 74.005 4.056 75.157 ;
     RECT  5.1 74.195 5.688 75.157 ;
     RECT  3.84 75.157 5.688 75.205 ;
     RECT  10.5 74.485 11.736 75.205 ;
     RECT  29.4 74.915 30.216 75.253 ;
     RECT  3.84 75.205 6.648 75.541 ;
     RECT  9.696 75.205 11.736 75.589 ;
     RECT  12.96 74.771 14.376 75.589 ;
     RECT  2.4 72.371 2.712 75.781 ;
     RECT  3.84 75.541 6.744 75.781 ;
     RECT  9.696 75.589 14.376 75.781 ;
     RECT  22.896 73.957 22.92 75.781 ;
     RECT  24 74.723 27.012 75.781 ;
     RECT  22.896 75.781 27.012 75.923 ;
     RECT  29.4 75.253 30.264 75.971 ;
     RECT  18.192 75.107 21.612 76.067 ;
     RECT  2.4 75.781 6.744 76.355 ;
     RECT  9.696 75.781 14.712 76.357 ;
     RECT  15.696 74.581 17.16 76.357 ;
     RECT  34.8 73.523 35.112 76.357 ;
     RECT  22.896 75.923 24.312 76.403 ;
     RECT  25.632 75.923 27.012 76.547 ;
     RECT  9.696 76.357 17.16 76.597 ;
     RECT  18.192 76.067 18.912 76.597 ;
     RECT  3.696 76.355 6.744 76.643 ;
     RECT  4.896 76.643 6.744 76.933 ;
     RECT  7.8 74.435 8.568 76.933 ;
     RECT  9.696 76.597 18.912 77.411 ;
     RECT  4.896 76.933 8.568 77.509 ;
     RECT  9.696 77.411 16.488 77.509 ;
     RECT  3.696 76.643 3.864 77.555 ;
     RECT  4.896 77.509 16.488 77.555 ;
     RECT  13.104 77.555 16.488 77.603 ;
     RECT  13.2 77.603 16.488 77.651 ;
     RECT  29.4 75.971 29.832 77.701 ;
     RECT  23.232 76.403 24.312 77.941 ;
     RECT  25.68 76.547 27.012 77.941 ;
     RECT  34.704 76.357 35.112 77.987 ;
     RECT  4.896 77.555 8.856 78.757 ;
     RECT  10.224 77.555 11.688 78.757 ;
     RECT  3.744 77.555 3.864 78.851 ;
     RECT  4.896 78.757 11.688 78.899 ;
     RECT  23.232 77.941 27.012 78.899 ;
     RECT  14.688 77.651 16.488 78.947 ;
     RECT  29.4 77.701 30.792 78.947 ;
     RECT  29.4 78.947 29.832 78.949 ;
     RECT  23.232 78.899 25.176 78.995 ;
     RECT  34.8 77.987 35.112 79.141 ;
     RECT  32.1 74.675 32.412 79.477 ;
     RECT  3.84 78.851 3.864 79.715 ;
     RECT  5.1 78.899 11.688 79.715 ;
     RECT  23.328 78.995 25.176 79.763 ;
     RECT  26.496 78.899 27.012 79.765 ;
     RECT  28.224 77.557 28.248 79.765 ;
     RECT  29.232 78.949 29.832 79.765 ;
     RECT  34.56 79.141 35.112 79.811 ;
     RECT  7.392 79.715 11.688 79.859 ;
     RECT  23.328 79.763 24.984 79.907 ;
     RECT  7.8 79.859 11.688 80.005 ;
     RECT  13.2 77.651 13.512 80.005 ;
     RECT  26.496 79.765 29.832 80.099 ;
     RECT  14.832 78.947 16.488 80.197 ;
     RECT  17.616 77.411 18.912 80.197 ;
     RECT  31.968 79.477 32.412 80.245 ;
     RECT  26.496 80.099 28.248 80.291 ;
     RECT  0.144 80.053 0.168 80.339 ;
     RECT  29.28 80.099 29.832 80.387 ;
     RECT  26.496 80.291 27.768 80.531 ;
     RECT  31.968 80.245 32.568 80.581 ;
     RECT  26.592 80.531 27.768 80.627 ;
     RECT  31.968 80.581 32.856 80.627 ;
     RECT  20.688 76.067 21.612 80.725 ;
     RECT  7.8 80.005 13.512 80.869 ;
     RECT  32.1 80.627 32.856 80.965 ;
     RECT  7.392 80.869 13.512 81.011 ;
     RECT  5.1 79.715 5.976 81.061 ;
     RECT  24 79.907 24.984 81.157 ;
     RECT  4.992 81.061 5.976 81.301 ;
     RECT  20.208 80.725 21.612 81.395 ;
     RECT  7.392 81.011 11.688 81.443 ;
     RECT  14.832 80.197 18.912 81.493 ;
     RECT  20.208 81.395 20.232 81.875 ;
     RECT  32.1 80.965 33.048 82.019 ;
     RECT  26.7 80.627 27.768 82.115 ;
     RECT  26.7 82.115 27.576 82.163 ;
     RECT  13.2 81.011 13.512 82.165 ;
     RECT  32.1 82.019 32.808 82.213 ;
     RECT  14.832 81.493 19.128 82.355 ;
     RECT  7.392 81.443 8.856 82.451 ;
     RECT  15.792 82.355 19.128 82.547 ;
     RECT  29.4 80.387 29.832 82.645 ;
     RECT  4.992 81.301 6.216 82.691 ;
     RECT  24 81.157 25.08 82.741 ;
     RECT  12.816 82.165 13.512 82.837 ;
     RECT  14.688 82.741 14.712 82.837 ;
     RECT  21.3 81.395 21.612 82.981 ;
     RECT  31.92 82.213 32.808 82.981 ;
     RECT  15.792 82.547 18.912 83.027 ;
     RECT  10.176 81.443 11.688 83.029 ;
     RECT  12.816 82.837 14.712 83.029 ;
     RECT  15.792 83.027 16.824 83.171 ;
     RECT  21.072 82.981 21.612 83.173 ;
     RECT  28.992 82.645 29.832 83.173 ;
     RECT  2.4 76.355 2.712 83.221 ;
     RECT  2.4 83.221 3.384 83.507 ;
     RECT  4.992 82.691 5.976 83.749 ;
     RECT  7.632 82.451 8.856 83.749 ;
     RECT  31.92 82.981 33.048 83.891 ;
     RECT  15.792 83.171 16.584 84.083 ;
     RECT  24 82.741 25.32 84.277 ;
     RECT  26.7 82.163 27.432 84.277 ;
     RECT  31.968 83.891 33.048 84.325 ;
     RECT  4.512 83.749 6.216 84.419 ;
     RECT  21.072 83.173 22.392 84.419 ;
     RECT  7.632 83.749 9.096 84.467 ;
     RECT  10.176 83.029 14.712 84.515 ;
     RECT  2.4 83.507 3.336 84.611 ;
     RECT  18 83.027 18.912 84.613 ;
     RECT  31.968 84.325 33.672 84.853 ;
     RECT  7.632 84.467 8.112 84.901 ;
     RECT  24 84.277 27.432 84.901 ;
     RECT  28.464 83.173 29.832 84.901 ;
     RECT  4.512 84.419 5.976 84.995 ;
     RECT  31.872 84.853 33.672 84.995 ;
     RECT  15.9 84.083 16.584 85.043 ;
     RECT  21.168 84.419 22.392 85.235 ;
     RECT  21.168 85.235 21.612 85.523 ;
     RECT  31.872 84.995 33.048 85.667 ;
     RECT  10.176 84.515 13.512 86.005 ;
     RECT  14.688 84.515 14.712 86.005 ;
     RECT  15.9 85.043 16.536 86.197 ;
     RECT  17.904 84.613 18.912 86.197 ;
     RECT  24 84.901 29.832 86.197 ;
     RECT  6.96 84.901 8.112 86.483 ;
     RECT  5.1 84.995 5.976 86.581 ;
     RECT  7.392 86.483 8.112 86.581 ;
     RECT  10.176 86.005 14.712 86.675 ;
     RECT  7.392 86.581 9 86.723 ;
     RECT  0.144 83.605 0.168 86.819 ;
     RECT  12.288 86.675 14.712 86.869 ;
     RECT  15.9 86.197 18.912 86.869 ;
     RECT  4.896 86.581 5.976 87.251 ;
     RECT  23.616 86.197 30.072 87.683 ;
     RECT  23.616 87.683 29.712 87.733 ;
     RECT  23.568 87.733 29.712 87.827 ;
     RECT  23.568 87.827 27.144 88.019 ;
     RECT  31.92 85.667 33.048 88.067 ;
     RECT  32.1 88.067 33.048 88.117 ;
     RECT  5.1 87.251 5.976 88.261 ;
     RECT  7.392 86.723 8.28 88.261 ;
     RECT  5.1 88.261 8.28 88.549 ;
     RECT  5.1 88.549 8.328 88.595 ;
     RECT  25.296 88.019 27.144 88.595 ;
     RECT  12.288 86.869 18.912 88.643 ;
     RECT  32.1 88.117 33.096 88.691 ;
     RECT  15.024 88.643 18.912 88.789 ;
     RECT  3.84 87.109 3.864 88.837 ;
     RECT  5.1 88.595 5.688 88.837 ;
     RECT  3.84 88.837 3.912 88.885 ;
     RECT  4.944 88.837 5.688 88.885 ;
     RECT  15.024 88.789 19.944 88.931 ;
     RECT  6.72 88.595 8.328 88.933 ;
     RECT  26.7 88.595 27.144 88.933 ;
     RECT  28.464 87.827 29.712 88.933 ;
     RECT  3.84 88.885 5.688 88.979 ;
     RECT  10.176 86.675 11.304 88.979 ;
     RECT  15.024 88.931 19.416 88.979 ;
     RECT  12.288 88.643 13.512 89.027 ;
     RECT  6.72 88.933 8.712 89.029 ;
     RECT  6.72 89.029 9.144 89.315 ;
     RECT  10.5 88.979 11.304 89.461 ;
     RECT  23.568 88.019 24.312 89.555 ;
     RECT  23.712 89.555 24.312 89.603 ;
     RECT  18.144 88.979 19.416 89.651 ;
     RECT  32.1 88.691 32.568 89.701 ;
     RECT  3.888 88.979 5.688 89.989 ;
     RECT  25.296 88.595 25.704 90.083 ;
     RECT  26.7 88.933 29.712 90.083 ;
     RECT  21.3 85.523 21.612 90.085 ;
     RECT  25.296 90.083 25.656 90.227 ;
     RECT  3.744 89.989 5.688 90.323 ;
     RECT  7.8 89.315 9.144 90.515 ;
     RECT  28.944 90.083 29.712 90.515 ;
     RECT  4.32 90.323 5.688 90.803 ;
     RECT  10.5 89.461 11.544 90.803 ;
     RECT  15.024 88.979 17.064 90.803 ;
     RECT  25.632 90.227 25.656 90.803 ;
     RECT  7.8 90.515 8.52 90.899 ;
     RECT  26.7 90.083 27.72 91.141 ;
     RECT  10.5 90.803 11.448 91.187 ;
     RECT  18.144 89.651 18.912 91.331 ;
     RECT  21.3 90.085 21.96 91.379 ;
     RECT  32.1 89.701 33.288 91.475 ;
     RECT  26.208 91.141 27.72 91.477 ;
     RECT  13.2 89.027 13.512 91.573 ;
     RECT  23.904 89.603 24.312 91.619 ;
     RECT  6.72 89.315 6.744 91.811 ;
     RECT  15.9 90.803 17.064 91.861 ;
     RECT  15.36 91.861 17.064 92.147 ;
     RECT  4.32 90.803 5.412 92.387 ;
     RECT  13.2 91.573 13.608 92.387 ;
     RECT  15.36 92.147 16.536 92.387 ;
     RECT  21.3 91.379 21.72 92.387 ;
     RECT  15.36 92.387 16.44 92.435 ;
     RECT  26.208 91.477 27.912 92.675 ;
     RECT  26.7 92.675 27.912 92.723 ;
     RECT  29.232 90.515 29.712 92.723 ;
     RECT  18.384 91.331 18.912 92.819 ;
     RECT  2.4 84.611 2.712 92.889 ;
     RECT  5.1 92.387 5.412 92.889 ;
     RECT  7.8 90.899 8.112 92.889 ;
     RECT  10.5 91.187 10.812 92.889 ;
     RECT  13.2 92.387 13.512 92.889 ;
     RECT  18.6 92.819 18.912 92.889 ;
     RECT  21.3 92.387 21.612 92.889 ;
     RECT  24 91.619 24.312 92.889 ;
     RECT  26.7 92.723 27.012 92.889 ;
     RECT  29.4 92.723 29.712 92.889 ;
     RECT  32.1 91.475 32.412 92.889 ;
     RECT  34.8 79.811 35.112 92.889 ;
     RECT  2.4 92.889 2.52 92.903 ;
     RECT  5.1 92.889 5.22 92.903 ;
     RECT  7.8 92.889 7.92 92.903 ;
     RECT  10.5 92.889 10.62 92.903 ;
     RECT  13.2 92.889 13.32 92.903 ;
     RECT  15.9 92.435 16.44 92.903 ;
     RECT  18.6 92.889 18.72 92.903 ;
     RECT  21.3 92.889 21.42 92.903 ;
     RECT  24 92.889 24.12 92.903 ;
     RECT  26.7 92.889 26.82 92.903 ;
     RECT  29.4 92.889 29.52 92.903 ;
     RECT  32.1 92.889 32.22 92.903 ;
     RECT  34.8 92.889 34.92 92.903 ;
     RECT  16.368 92.903 16.44 94.883 ;
     RECT  16.368 94.883 16.392 94.979 ;
  END
END dsfd_dvland_562
END LIBRARY
